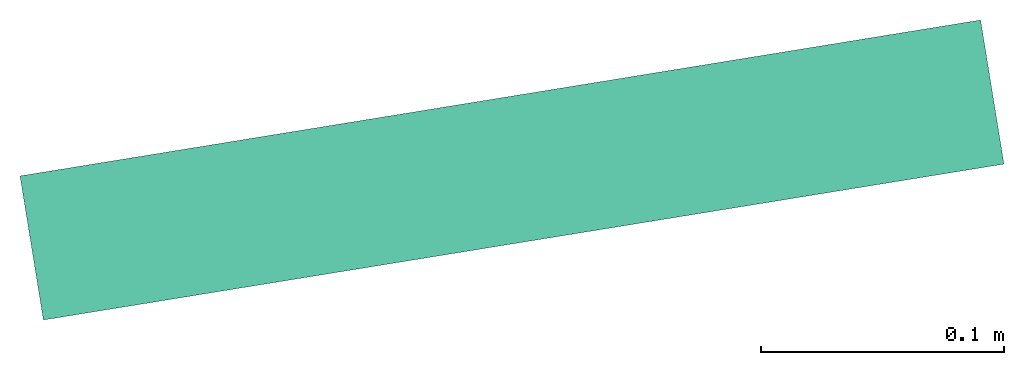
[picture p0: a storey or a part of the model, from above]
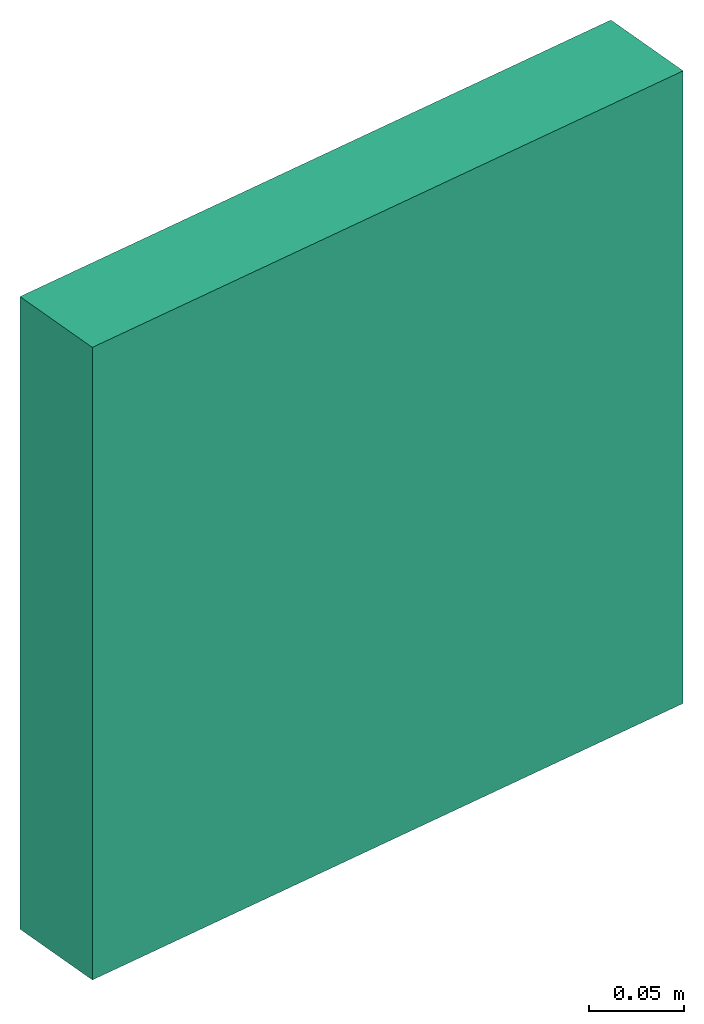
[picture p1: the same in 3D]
Properties of the parts of a building model (IFC2X3), part 1 of 4

# File
Description: ViewDefinition [CoordinationView_V2.0]
File name: BR003-350-201.1 (EDITED).ifc (Edited by Naviate Simple BIM 2022 version 6)
Time: 2026-03-27T08:58:00+01:00
Written by: ODA SDAI 24.12
Made in: Autodesk Revit 25.4.41.14 (ENU) - IFC 25.4.0.27

# IfcProject, 80052
LongName: T3 - Flesland; Phase: Som Bygget

# IfcSite (8)
RefElevation: 0 mm
Name | RefLatitude | RefLongitude
4 x Default | 42, 24, 53, 508911 | -71, -15, -29, -58837
3 x Default | 59, 54, 49, 759826 | 10, 44, 19, 467315
Default | 60, 17, 20, 899658 | 5, 13, 37, 654037

# IfcBuilding (8)
Name
7 x 
TOO | LongName: TOO

# IfcBuildingStorey: Level:8mm Head (19)
Name | LongName | Elevation (mm)
3 x Nivå A | Nivå A | 42100
3 x Nivå B | Nivå B | 44700
5 x Nivå E | Nivå E | 55630
7 x Nivå F | Nivå F | 59000
Nivå C | Nivå C | 48160

# IfcBuildingStorey: Level:Kote (2)
In: TOO
Name | LongName | Elevation (mm)
Nivå F | Nivå F | 59000
Nivå G | Nivå G | 64000

# IfcBuildingStorey: Level:T3 Kote (2)
In: TOO
Name | LongName | Elevation (mm)
Nivå D | Nivå D | 51000
Nivå E | Nivå E | 55630

# IfcAnnotation, Model Lines:32988126
In: Nivå F
ePset_LocationTool - Splitting: ORIGINAL
ePset_Simplebim - Assembly Level: Leaf

# IfcBeam: 223_Bjelker-T3-Prefab DLB:DLB400*815-700*420 (2)
In: Nivå F
Type - PredefinedType: BEAM
Material: Betong Plasstøpt - B1
Pset_BeamCommon - Reference: 223_Bjelker-T3-Prefab DLB:DLB400*815-700*420
ePset_SimplebimBasicQuantities - Area, sides, net (Simplebim): 26.8105 m2; Length (Simplebim): 8550 mm; Height (Simplebim): 815 mm; Volume, net (Simplebim): 3.8646 m3; Width (Simplebim): 700 mm; Weight, as steel (Simplebim): 30337.1 kg
AVINOR - 08_Status: S4; 07_Fase: F30
ePset_Simplebim - Assembly Level: Leaf
ePset_LocationTool - Splitting: ORIGINAL
Name (223_Bjelker-T3-Prefab DLB:DLB400*815-700*420:...)
25848422
25848424

# IfcBeam: A223 - DLB Prefab. Betongbjelke:A223 - DLB Prefab. Betongbjelke - 815 x 700 x 400 mm (2)
In: Nivå F
Type - PredefinedType: BEAM
Material: Concrete - Cast-in-Place Concrete
AVINOR - 08_Status: S3; 07_Fase: F30
Pset_BeamCommon - Reference: A223 - DLB Prefab. Betongbjelke:A223 - DLB Prefab. Betongbjelke - 815 x 700 x 400 mm
ePset_SimplebimBasicQuantities - Weight, as steel (Simplebim): 23976.2 kg; Height (Simplebim): 815 mm; Area, sides, net (Simplebim): 21.3786 m2; Length (Simplebim): 6757.29 mm; Width (Simplebim): 700 mm; Volume, net (Simplebim): 3.0543 m3
ePset_LocationTool - Splitting: ORIGINAL
ePset_Simplebim - Assembly Level: Leaf
Name (A223 - DLB Prefab. Betongbjelke:A223 - DLB Prefab. Betongbjelke - 815 x 700 x 400 mm:...)
15730720
28248135

# IfcBeam: A223 - LB Prefab. Betongbjelke 815x550:A223 - LB Prefab. Betongbjelke - 815 mm x 550 mm (3)
In: Nivå F
Type - PredefinedType: BEAM
ePset_SimplebimBasicQuantities - Height (Simplebim): 815 mm; Width (Simplebim): 550 mm
Pset_BeamCommon - Reference: A223 - LB Prefab. Betongbjelke 815x550:A223 - LB Prefab. Betongbjelke - 815 mm x 550 mm
AVINOR - 08_Status: S3; 07_Fase: F30
ePset_Simplebim - Assembly Level: Leaf
Name (A223 - LB Prefab. Betongbjelke 815x550:A223 - LB Prefab. Betongbjelke - 815 mm x 550 mm:...) | Splitting | Weight, as steel (Simplebim) (kg) | Volume, net (Simplebim) (m3) | Area, sides, net (Simplebim) (m2) | Length (Simplebim) (mm)
18706045 | ORIGINAL | 26575.9 | 3.38547 | 24.5372 | 8703 | Material: Concrete - Cast-in-Place Concrete
18706039 | RESULT | 21742.1 | 2.76969 | 20.2157 | 7120
18706051 | RESULT | 23826.1 | 3.03517 | 22.0788 | 7803

# IfcBeam: Rectangular Hollow Sections_Parameter:RHS100x200x10 (6)
Type - PredefinedType: BEAM
AVINOR - 08_Status: S4; 07_Fase: F90
Pset_BeamCommon - Reference: Rectangular Hollow Sections_Parameter:RHS100x200x10
ePset_SimplebimBasicQuantities - Width (Simplebim): 100 mm; Height (Simplebim): 200 mm
ePset_Simplebim - Assembly Level: Leaf
Name (Rectangular Hollow Sections_Parameter:RHS100x200x10:...) | In | Material | Splitting | Length (Simplebim) (mm) | Volume, net (Simplebim) (m3) | Area, sides, net (Simplebim) (m2) | Weight, as steel (Simplebim) (kg)
27042935 | Nivå F | Metal - Steel 50-355 | ORIGINAL | 4763.41 | 0.0266751 | 5.34622 | 209.4
27042937 | Nivå F | Metal - Steel 50-355 | ORIGINAL | 1605.53 | 0.00899095 | 1.80939 | 70.579
27046365 | Nivå F | Metal - Steel 50-355 | ORIGINAL | 4763.41 | 0.0266751 | 5.34622 | 209.4
27046367 | Nivå F | Metal - Steel 50-355 | ORIGINAL | 1633.53 | 0.00914775 | 1.84075 | 71.8099
29842427 | Nivå G |  | RESULT | 1966 | 0.0100881 | 2.03399 | 79.1917
27042939 | Nivå G |  | RESULT | 2135 | 0.0110374 | 2.22384 | 86.6433

# IfcBuildingElementProxy: 1612510-0001:Junction box1 (10)
In: Nivå F
Type - Material: <Unnamed>
AVINOR - 08_Status: S4; 07_Fase: F90
ePset_SimplebimBasicQuantities - Area, largest surface, net (Simplebim): 0.0121 m2; Volume, net (Simplebim): 0.000515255 m3; Height (Simplebim): 110 mm; Length (Simplebim): 110 mm; Thickness (Simplebim): 46 mm
ePset_LocationTool - Splitting: ORIGINAL
Pset_BuildingElementProxyCommon - Reference: 1612510-0001:Junction box1
ePset_Simplebim - Assembly Level: Leaf
Name (1612510-0001:Junction box1:...)
13268464 | Group: 31
13273142
13273163 | Group: 20
13303722
13303824
13303911
13324208
13324228 | Group: 29
13341823 | Group: 28
14886891 | AVINOR - 05_ID-nummer: +BR003=360.PB114-FA002

# IfcBuildingElementProxy: 248 Sidefoldesjalusi:A248 Sidefoldesjalusi (3)
In: Nivå F
Type - Material: Glass
AVINOR - 08_Status: S4; 07_Fase: F90
ePset_LocationTool - Splitting: ORIGINAL
ePset_SimplebimBasicQuantities - Area, largest surface, net (Simplebim): 0.689 m2; Length (Simplebim): 369.963 mm; Volume, net (Simplebim): 0.0689 m3; Thickness (Simplebim): 260 mm; Height (Simplebim): 2650 mm
Pset_BuildingElementProxyCommon - Reference: 248 Sidefoldesjalusi:A248 Sidefoldesjalusi
ePset_Simplebim - Assembly Level: Leaf
Name (248 Sidefoldesjalusi:A248 Sidefoldesjalusi:...)
26929427
26940893
27625954

# IfcBuildingElementProxy: 258 - gulvboks EL-kvadrat 300 x300:A258 - gulvboks EL-kvadrat 300x300, 258 - gulvboks EL-kvadrat 300 x300:A258 - gulvboks EL-kvadrat 300x300:30005898
In: Nivå F
Type - Material: Default
Pset_BuildingElementProxyCommon - Reference: 258 - gulvboks EL-kvadrat 300 x300:A258 - gulvboks EL-kvadrat 300x300
ePset_SimplebimBasicQuantities - Area, largest surface, net (Simplebim): 0.0587578 m2; Height (Simplebim): 5 mm; Thickness (Simplebim): 300 mm; Length (Simplebim): 300 mm; Volume, net (Simplebim): 0.00045 m3
ePset_LocationTool - Splitting: ORIGINAL
AVINOR - 08_Status: S1; 07_Fase: F30
ePset_Simplebim - Assembly Level: Leaf

# IfcBuildingElementProxy: BRANNSPJELD - - SZ011T:BRANNSPJELD -C-EI60-125 - SZ011T (2)
Type - Material: <Unnamed>
ePset_SimplebimBasicQuantities - Volume, net (Simplebim): 0.00323555 m3; Area, largest surface, net (Simplebim): 0.103933 m2; Thickness (Simplebim): 125 mm; Height (Simplebim): 125 mm; Length (Simplebim): 265 mm
ePset_LocationTool - Splitting: ORIGINAL
Pset_BuildingElementProxyCommon - Reference: BRANNSPJELD - - SZ011T:BRANNSPJELD -C-EI60-125 - SZ011T
AVINOR - 08_Status: S4; 07_Fase: F90
ePset_Simplebim - Assembly Level: Leaf
Group: 360.PB114 A
Name (BRANNSPJELD - - SZ011T:BRANNSPJELD -C-EI60-125 - SZ011T:...) | In | 05_ID-nummer
14787282 | Nivå F | +BR003=360.PB114-SZ005
18961542 | Nivå E | +BR003=360.PB114-SZ021

# IfcBuildingElementProxy: BRANNSPJELD - - SZ011T:BRANNSPJELD -C-EI60-160 - SZ011T, BRANNSPJELD - - SZ011T:BRANNSPJELD -C-EI60-160 - SZ011T:21433908
In: Nivå F
Type - Material: <Unnamed>
ePset_LocationTool - Splitting: ORIGINAL
Pset_BuildingElementProxyCommon - Reference: BRANNSPJELD - - SZ011T:BRANNSPJELD -C-EI60-160 - SZ011T
ePset_SimplebimBasicQuantities - Volume, net (Simplebim): 0.00530113 m3; Area, largest surface, net (Simplebim): 0.133035 m2; Thickness (Simplebim): 160 mm; Height (Simplebim): 160 mm; Length (Simplebim): 265 mm
AVINOR - 08_Status: S4; 07_Fase: F90; 05_ID-nummer: +BR003=360.PB114-SZ028
ePset_Simplebim - Assembly Level: Leaf
Group: 360.PB114 T

# IfcBuildingElementProxy: BRANNSPJELD - - SZ011T:BRANNSPJELD -C-EI60-400 - SZ011T (2)
In: Nivå F
Type - Material: <Unnamed>
ePset_SimplebimBasicQuantities - Area, largest surface, net (Simplebim): 0.561004 m2; Volume, net (Simplebim): 0.0558869 m3; Thickness (Simplebim): 400 mm; Height (Simplebim): 400 mm; Length (Simplebim): 447 mm
Pset_BuildingElementProxyCommon - Reference: BRANNSPJELD - - SZ011T:BRANNSPJELD -C-EI60-400 - SZ011T
ePset_LocationTool - Splitting: ORIGINAL
AVINOR - 08_Status: S4; 07_Fase: F90
ePset_Simplebim - Assembly Level: Leaf
Name (BRANNSPJELD - - SZ011T:BRANNSPJELD -C-EI60-400 - SZ011T:...) | 05_ID-nummer | Group
21341083 | +BR003=360.PB114-SZ025 | 360.PB114 A
21408593 | +BR003=360.PB114-SZ026 | 360.PB114 T

# IfcBuildingElementProxy: BRANNSPJELD - - SZ011T:BRANNSPJELD -C-EI60-500 - SZ011T (5)
In: Nivå F
Type - Material: <Unnamed>
AVINOR - 08_Status: S4; 07_Fase: F90
Pset_BuildingElementProxyCommon - Reference: BRANNSPJELD - - SZ011T:BRANNSPJELD -C-EI60-500 - SZ011T
ePset_LocationTool - Splitting: ORIGINAL
ePset_SimplebimBasicQuantities - Area, largest surface, net (Simplebim): 0.701255 m2; Thickness (Simplebim): 447 mm; Height (Simplebim): 500 mm; Length (Simplebim): 500 mm; Volume, net (Simplebim): 0.0873233 m3
ePset_Simplebim - Assembly Level: Leaf
Name (BRANNSPJELD - - SZ011T:BRANNSPJELD -C-EI60-500 - SZ011T:...) | 05_ID-nummer | Group
13302451 | +BR003=360.PB114-SZ007 | 360.PB114 A
13302491 | +BR003=360.PB114-SZ015 | 360.PB114 T
13302806 | +BR003=360.PB114-SZ008 | 360.PB114 A
14775724 | +BR003=360.PB114-SZ001 | 360.PB114 A
14775863 | +BR003=360.PB114-SZ009 | 360.PB114 T

# IfcBuildingElementProxy: BRANNSPJELD - 1 - SZ06T:BRANNSPJELD -C-EI120-200 - SZ06T, BRANNSPJELD - 1 - SZ06T:BRANNSPJELD -C-EI120-200 - SZ06T:18961634
In: Nivå E
Type - Material: <Unnamed>
AVINOR - 08_Status: S4; 07_Fase: F90; 05_ID-nummer: +BR003=360.PB114-SZ022
ePset_LocationTool - Splitting: ORIGINAL
Pset_BuildingElementProxyCommon - Reference: BRANNSPJELD - 1 - SZ06T:BRANNSPJELD -C-EI120-200 - SZ06T
ePset_SimplebimBasicQuantities - Height (Simplebim): 196 mm; Thickness (Simplebim): 196 mm; Length (Simplebim): 363 mm; Volume, net (Simplebim): 0.0108969 m3; Area, largest surface, net (Simplebim): 0.223234 m2
ePset_Simplebim - Assembly Level: Leaf
Group: 360.PB114 A

# IfcBuildingElementProxy: Bryter 1-polet m_boks:2006015 (5)
In: Nivå F
Type - Material: Material1
AVINOR - 08_Status: S4; 07_Fase: F90; 05_ID-nummer: +BR003=439.OO001-XS001T
Pset_BuildingElementProxyCommon - Reference: Bryter 1-polet m_boks:2006015
ePset_LocationTool - Splitting: ORIGINAL
ePset_SimplebimBasicQuantities - Volume, net (Simplebim): 0.000041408 m3; Thickness (Simplebim): 12 mm; Length (Simplebim): 60 mm; Height (Simplebim): 60 mm; Area, largest surface, net (Simplebim): 0.0036 m2
ePset_Simplebim - Assembly Level: Leaf
Name (Bryter 1-polet m_boks:2006015:...)
13268543
13273152
13273153
13273158
13322008

# IfcBuildingElementProxy: Bryter 2-polet påvegg:2006015, Bryter 2-polet påvegg:2006015:13993074
In: Nivå F
Type - Material: Material1
ePset_LocationTool - Splitting: ORIGINAL
AVINOR - 08_Status: S4; 07_Fase: F90; 05_ID-nummer: +BR003=439.OO001-XS001T
ePset_SimplebimBasicQuantities - Volume, net (Simplebim): 0.000041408 m3; Thickness (Simplebim): 12 mm; Length (Simplebim): 60 mm; Height (Simplebim): 60 mm; Area, largest surface, net (Simplebim): 0.0036 m2
Pset_BuildingElementProxyCommon - Reference: Bryter 2-polet påvegg:2006015
ePset_Simplebim - Assembly Level: Leaf

# IfcBuildingElementProxy: Dobbel stikk i kanal 2P+J hor innfelt:RECESSED-SOCKET-2(HOR) (3)
In: Nivå F
Type - Material: <Unnamed>
ePset_SimplebimBasicQuantities - Area, largest surface, net (Simplebim): 0.0085 m2; Volume, net (Simplebim): 0.0000446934 m3; Thickness (Simplebim): 74.5128 mm; Height (Simplebim): 76.1056 mm; Length (Simplebim): 110.062 mm
Pset_BuildingElementProxyCommon - Reference: Dobbel stikk i kanal 2P+J hor innfelt:RECESSED-SOCKET-2(HOR)
ePset_LocationTool - Splitting: ORIGINAL
AVINOR - 08_Status: S4; 07_Fase: F90; 05_ID-nummer: +BR003=439.OO001-UE001T
ePset_Simplebim - Assembly Level: Leaf
Name (Dobbel stikk i kanal 2P+J hor innfelt:RECESSED-SOCKET-2(HOR):...) | Group
13268198 | =433.PF111-KW38
13268258 | =433.PF111-KW38
13321827 | 37

# IfcBuildingElementProxy: Dobbel stikk i tak m_boks 2P+J PH:Earthed reces socket c2 (6)
In: Nivå F
Type - Material: <Unnamed>
ePset_LocationTool - Splitting: ORIGINAL
ePset_SimplebimBasicQuantities - Area, largest surface, net (Simplebim): 0.010086 m2; Height (Simplebim): 19 mm; Thickness (Simplebim): 82 mm; Length (Simplebim): 123 mm; Volume, net (Simplebim): 0.000118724 m3
Pset_BuildingElementProxyCommon - Reference: Dobbel stikk i tak m_boks 2P+J PH:Earthed reces socket c2
AVINOR - 08_Status: S4; 07_Fase: F90; 05_ID-nummer: +BR003=439.OO001-UE001T
ePset_Simplebim - Assembly Level: Leaf
Name (Dobbel stikk i tak m_boks 2P+J PH:Earthed reces socket c2:...)
13296715
13296716 | Group: 2
13296727
13296728 | Group: 23
13296735
13296736 | Group: 25

# IfcBuildingElementProxy: Dobbel stikk på vegg 2P+J hor PH:EARTHED-SOCKET-2(HOR) (22)
In: Nivå F
Type - Material: <Unnamed>
ePset_SimplebimBasicQuantities - Thickness (Simplebim): 45.1 mm; Length (Simplebim): 98.2 mm; Area, largest surface, net (Simplebim): 0.006174 m2; Height (Simplebim): 63.2 mm; Volume, net (Simplebim): 0.0000063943 m3
Pset_BuildingElementProxyCommon - Reference: Dobbel stikk på vegg 2P+J hor PH:EARTHED-SOCKET-2(HOR)
ePset_LocationTool - Splitting: ORIGINAL
AVINOR - 08_Status: S4; 07_Fase: F90; 05_ID-nummer: +BR003=439.OO001-UE001T
ePset_Simplebim - Assembly Level: Leaf
Name (Dobbel stikk på vegg 2P+J hor PH:EARTHED-SOCKET-2(HOR):...) | Group
13264661 | 1
13264669 | 3
13264673
13264676 | 4
13268019 | 18
13268034 | 13
13268035 | =433.PF111-KW42
13268036 | 13
13268037 | =433.PF111-KW42
13268038 | 13
13268039 | =433.PF111-KW42
13268040 | 13
13268041 | =433.PF111-KW42
13268047 | 30
13268048 | 30
13268049 | 30
13268050 | 30
13268665 | 17
13268686 | 17
13268706 | 17
13268745 | 14
18297994 | 39

# IfcBuildingElementProxy: Dobbel stikk på vegg 2P+J vert PH:EARTHED-SOCKET-2(VER) (3)
In: Nivå F
Type - Material: <Unnamed>
Pset_BuildingElementProxyCommon - Reference: Dobbel stikk på vegg 2P+J vert PH:EARTHED-SOCKET-2(VER)
ePset_LocationTool - Splitting: ORIGINAL
ePset_SimplebimBasicQuantities - Thickness (Simplebim): 45.1 mm; Height (Simplebim): 98.2 mm; Area, largest surface, net (Simplebim): 0.006174 m2; Length (Simplebim): 63.2 mm; Volume, net (Simplebim): 0.00000606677 m3
AVINOR - 08_Status: S4; 07_Fase: F90; 05_ID-nummer: +BR003=439.OO001-UE001T
ePset_Simplebim - Assembly Level: Leaf
Name (Dobbel stikk på vegg 2P+J vert PH:EARTHED-SOCKET-2(VER):...) | Group
4317817 | =433.PF111-KW6
4317895 | =433.PF111-KW6
16224344 | =433.PF111-KW49

# IfcBuildingElementProxy: Dobbel stikk vegg innf 1½ boks 2P+J vert PH:RECESSED-EARTHED-SOCKET-2(VER) (6)
In: Nivå F
Type - Material: Material3, Material2, Material1
ePset_SimplebimBasicQuantities - Thickness (Simplebim): 25.7805 mm; Volume, net (Simplebim): 0.000114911 m3; Length (Simplebim): 139.716 mm; Height (Simplebim): 144.742 mm; Area, largest surface, net (Simplebim): 0.00984 m2
Pset_BuildingElementProxyCommon - Reference: Dobbel stikk vegg innf 1½ boks 2P+J vert PH:RECESSED-EARTHED-SOCKET-2(VER)
AVINOR - 08_Status: S4; 07_Fase: F90; 05_ID-nummer: +BR003=439.OO001-UE001T
ePset_LocationTool - Splitting: ORIGINAL
ePset_Simplebim - Assembly Level: Leaf
Name (Dobbel stikk vegg innf 1½ boks 2P+J vert PH:RECESSED-EARTHED-SOCKET-2(VER):...) | Group
4300604 | =433.PF111-KW10
10222701 | =433.PF111-KW10
13264690 | =433.PF111-KW41
13264691
13303512 | 12
18211983 | =433.PF111-KW50

# IfcBuildingElementProxy: Dobbel stikk vegg innf 2P+J hor PH:RECESSED-SOCKET-2(HOR) (3)
In: Nivå F
Type - Material: <Unnamed>
ePset_LocationTool - Splitting: ORIGINAL
ePset_SimplebimBasicQuantities - Area, largest surface, net (Simplebim): 0.0085 m2; Volume, net (Simplebim): 0.0000446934 m3; Thickness (Simplebim): 74.5128 mm; Height (Simplebim): 76.1056 mm; Length (Simplebim): 110.062 mm
Pset_BuildingElementProxyCommon - Reference: Dobbel stikk vegg innf 2P+J hor PH:RECESSED-SOCKET-2(HOR)
AVINOR - 08_Status: S4; 07_Fase: F90; 05_ID-nummer: +BR003=439.OO001-UE001T
ePset_Simplebim - Assembly Level: Leaf
Name (Dobbel stikk vegg innf 2P+J hor PH:RECESSED-SOCKET-2(HOR):...)
13268002
13268003
14002127

# IfcBuildingElementProxy: Dobbelstikk vertikal:Dobbelstikk vertikal, Dobbelstikk vertikal:Dobbelstikk vertikal:30331455
In: Nivå F
Type - Material: Material3, Material1, Material2
ePset_SimplebimBasicQuantities - Volume, net (Simplebim): 0.000114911 m3; Length (Simplebim): 139.716 mm; Thickness (Simplebim): 25.7817 mm; Height (Simplebim): 144.742 mm; Area, largest surface, net (Simplebim): 0.00984 m2
Pset_BuildingElementProxyCommon - Reference: Dobbelstikk vertikal:Dobbelstikk vertikal
ePset_LocationTool - Splitting: ORIGINAL
ePset_Simplebim - Assembly Level: Leaf

# IfcBuildingElementProxy: El-ford-Skap:El-ford-Skap_001 (2)
In: Nivå F
Type - Material: <Unnamed>
ePset_LocationTool - Splitting: ORIGINAL
ePset_SimplebimBasicQuantities - Height (Simplebim): 2000 mm
AVINOR - 08_Status: S4; 07_Fase: F90
Pset_BuildingElementProxyCommon - Reference: El-ford-Skap:El-ford-Skap_001
ePset_Simplebim - Assembly Level: Leaf
Name (El-ford-Skap:...) | Volume, net (Simplebim) (m3) | Area, largest surface, net (Simplebim) (m2) | Thickness (Simplebim) (mm) | Length (Simplebim) (mm) | 05_ID-nummer | Group
=433.PF111:1945846 | 1.6 | 4 | 400 | 2000 | +BR003=433.PF111 | =433.PF111-KW10; =433.PF111-KW1; =433.PF111-KW6; =433.PF111-KW27; =433.PF111-KW41; =433.PF111-KW42; =433.PF111-KW38; =433.PF111-KW49; =433.PF111-KW50
=435.PF111:13223778 | 0.36 | 1.2 | 300 | 600 | +BR003=435.PF111 | 1; 3; 4; 18; 13; 30; 31; 17; 15; 14; 20; 2; 23; 25; 7; 8; 12; 37; 29; 39

# IfcBuildingElementProxy: El-ford-stativ:El-ford-stativ_001 (2)
In: Nivå F
Type - Material: <Unnamed>
ePset_LocationTool - Splitting: ORIGINAL
AVINOR - 08_Status: S4; 07_Fase: F90
Pset_BuildingElementProxyCommon - Reference: El-ford-stativ:El-ford-stativ_001
ePset_SimplebimBasicQuantities - Length (Simplebim): 600 mm; Thickness (Simplebim): 300 mm
ePset_Simplebim - Assembly Level: Leaf
Name (El-ford-stativ:El-ford-stativ_001:...) | Volume, net (Simplebim) (m3) | Area, largest surface, net (Simplebim) (m2) | Height (Simplebim) (mm)
1945912 | 0.36 | 1.2 | 2000
1946078 | 0.108 | 0.36 | 600

# IfcBuildingElementProxy: FANCOIL--LC006T:FANCOIL--LC006T, FANCOIL--LC006T:FANCOIL--LC006T:20416227
In: Nivå F
Type - Material: <Unnamed>
Pset_BuildingElementProxyCommon - Reference: FANCOIL--LC006T:FANCOIL--LC006T
ePset_SimplebimBasicQuantities - Volume, net (Simplebim): 0.126 m3; Height (Simplebim): 350 mm; Thickness (Simplebim): 600 mm; Length (Simplebim): 600 mm; Area, largest surface, net (Simplebim): 0.36 m2
ePset_LocationTool - Splitting: ORIGINAL
AVINOR - 05_ID-nummer: +BR003=370.PB102-LC013; 08_Status: S4; 07_Fase: F90
ePset_Simplebim - Assembly Level: Leaf
Group: 370.PB102 T

# IfcBuildingElementProxy: Gulvboks 300x300:CONNECTION BOX-EF-POWER-BALANC, Gulvboks 300x300:CONNECTION BOX-EF-POWER-BALANC:5003242
In: Nivå F
Type - Material: <Unnamed>
Pset_BuildingElementProxyCommon - Reference: Gulvboks 300x300:CONNECTION BOX-EF-POWER-BALANC
ePset_SimplebimBasicQuantities - Height (Simplebim): 70 mm; Thickness (Simplebim): 300 mm; Length (Simplebim): 300 mm; Area, largest surface, net (Simplebim): 0.09 m2; Volume, net (Simplebim): 0.0063 m3
ePset_LocationTool - Splitting: ORIGINAL
AVINOR - 08_Status: S4; 07_Fase: F90; 05_ID-nummer: +BR003=411.OO002-KK005T
ePset_Simplebim - Assembly Level: Leaf

# IfcBuildingElementProxy: Høyttaler innfelt 16cm:Bass speaker PC-2369EN /6W (7)
In: Nivå F
Type - Material: Material1, Material2
ePset_LocationTool - Splitting: ORIGINAL
ePset_SimplebimBasicQuantities - Area, largest surface, net (Simplebim): 0.0479856 m2; Length (Simplebim): 242.889 mm; Height (Simplebim): 170.098 mm; Volume, net (Simplebim): 0.00448694 m3; Thickness (Simplebim): 229.877 mm
AVINOR - 08_Status: S1; 07_Fase: F30
Pset_BuildingElementProxyCommon - Reference: Høyttaler innfelt 16cm:Bass speaker PC-2369EN /6W
ePset_Simplebim - Assembly Level: Leaf
Name (Høyttaler innfelt 16cm:Bass speaker PC-2369EN /6W:...)
7143913
7143918
7143919
7143920
7143921
7143936
9532946

# IfcBuildingElementProxy: INNREGULERINGSPJELD - - SR001T:INNREGULERINGSPJELD - IRIS-012 - SR001T, INNREGULERINGSPJELD - - SR001T:INNREGULERINGSPJELD - IRIS-012 - SR001T:14814005
In: Nivå F
Type - Material: <Unnamed>
ePset_LocationTool - Splitting: ORIGINAL
AVINOR - 08_Status: S4; 07_Fase: F90; 05_ID-nummer: +BR003=360.PB114-SR001T
ePset_SimplebimBasicQuantities - Volume, net (Simplebim): 0.000561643 m3; Area, largest surface, net (Simplebim): 0.0180412 m2; Thickness (Simplebim): 46 mm; Height (Simplebim): 125 mm; Length (Simplebim): 125 mm
Pset_BuildingElementProxyCommon - Reference: INNREGULERINGSPJELD - - SR001T:INNREGULERINGSPJELD - IRIS-012 - SR001T
ePset_Simplebim - Assembly Level: Leaf
Group: 360.PB114 A

# IfcBuildingElementProxy: INNREGULERINGSPJELD - - SR001T:INNREGULERINGSPJELD - IRIS-050 - SR001T (2)
In: Nivå F
Type - Material: <Unnamed>
Pset_BuildingElementProxyCommon - Reference: INNREGULERINGSPJELD - - SR001T:INNREGULERINGSPJELD - IRIS-050 - SR001T
ePset_SimplebimBasicQuantities - Thickness (Simplebim): 66 mm; Volume, net (Simplebim): 0.0128934 m3; Area, largest surface, net (Simplebim): 0.195354 m2; Height (Simplebim): 500 mm; Length (Simplebim): 500 mm
AVINOR - 08_Status: S4; 07_Fase: F90; 05_ID-nummer: +BR003=360.PB114-SR001T
ePset_LocationTool - Splitting: ORIGINAL
ePset_Simplebim - Assembly Level: Leaf
Name (INNREGULERINGSPJELD - - SR001T:INNREGULERINGSPJELD - IRIS-050 - SR001T:...) | Group
14747202 | 360.PB114 A
14747242 | 360.PB114 T

# IfcBuildingElementProxy: KJØLEAGGREGAT--IL - Starcold Aggregat:KJØLEAGGREGATMC LC1A B 020 MTIL - Starcold AggregaT, KJØLEAGGREGAT--IL - Starcold Aggregat:KJØLEAGGREGATMC LC1A B 020 MTIL - Starcold AggregaT:22178376
In: Nivå F
Type - Material: <Unnamed>
ePset_LocationTool - Splitting: ORIGINAL
ePset_SimplebimBasicQuantities - Area, largest surface, net (Simplebim): 0.920419 m2; Height (Simplebim): 1040.02 mm; Volume, net (Simplebim): 0.699519 m3; Thickness (Simplebim): 760 mm; Length (Simplebim): 885 mm
AVINOR - 05_ID-nummer: Kjøleaggregat-kom.areal; 08_Status: S4; 07_Fase: F90
Pset_BuildingElementProxyCommon - Reference: KJØLEAGGREGAT--IL - Starcold Aggregat:KJØLEAGGREGATMC LC1A B 020 MTIL - Starcold AggregaT
ePset_Simplebim - Assembly Level: Leaf

# IfcBuildingElementProxy: KJØLEAGGREGAT--IL - Starcold Aggregat:KJØLEAGGREGATMC LC4 B 050 MTIL - Starcold AggregaT, KJØLEAGGREGAT--IL - Starcold Aggregat:KJØLEAGGREGATMC LC4 B 050 MTIL - Starcold AggregaT:22178189
In: Nivå F
Type - Material: <Unnamed>
AVINOR - 05_ID-nummer: Kjøleaggregat-kom.areal; 08_Status: S4; 07_Fase: F90
ePset_LocationTool - Splitting: ORIGINAL
Pset_BuildingElementProxyCommon - Reference: KJØLEAGGREGAT--IL - Starcold Aggregat:KJØLEAGGREGATMC LC4 B 050 MTIL - Starcold AggregaT
ePset_SimplebimBasicQuantities - Volume, net (Simplebim): 1.05916 m3; Area, largest surface, net (Simplebim): 1.39363 m2; Height (Simplebim): 1040.02 mm; Thickness (Simplebim): 760 mm; Length (Simplebim): 1340 mm
ePset_Simplebim - Assembly Level: Leaf

# IfcBuildingElementProxy: Koblingsboks skjult:CABLE CLIP 1 - WALL - 2, Koblingsboks skjult:CABLE CLIP 1 - WALL - 2:13273173
In: Nivå F
Type - Material: <Unnamed>
ePset_SimplebimBasicQuantities - Volume, net (Simplebim): 0.0000139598 m3; Length (Simplebim): 110.24 mm; Area, largest surface, net (Simplebim): 0.00952342 m2; Thickness (Simplebim): 55.7518 mm; Height (Simplebim): 100.984 mm
Pset_BuildingElementProxyCommon - Reference: Koblingsboks skjult:CABLE CLIP 1 - WALL - 2
AVINOR - 08_Status: S4; 07_Fase: F90; 05_ID-nummer: +BR003=439.OO001-UX001T
ePset_LocationTool - Splitting: ORIGINAL
ePset_Simplebim - Assembly Level: Leaf

# IfcBuildingElementProxy: LYDDEMPER - - QL004T:LYDDEMPER - 125-300 - QL004T, LYDDEMPER - - QL004T:LYDDEMPER - 125-300 - QL004T:14814244
In: Nivå A
Type - Material: <Unnamed>
ePset_LocationTool - Splitting: ORIGINAL
ePset_SimplebimBasicQuantities - Area, largest surface, net (Simplebim): 0.158418 m2; Volume, net (Simplebim): 0.00650987 m3; Thickness (Simplebim): 165 mm; Height (Simplebim): 165 mm; Length (Simplebim): 306 mm
Pset_BuildingElementProxyCommon - Reference: LYDDEMPER - - QL004T:LYDDEMPER - 125-300 - QL004T
AVINOR - 08_Status: S4; 07_Fase: F90; 05_ID-nummer: +BR003=360.PB114-QL004T
ePset_Simplebim - Assembly Level: Leaf
Group: 360.PB114 A

# IfcBuildingElementProxy: LYDDEMPER - - QL004T:LYDDEMPER - 160-300 - QL004T, LYDDEMPER - - QL004T:LYDDEMPER - 160-300 - QL004T:19855073
In: Nivå E
Type - Material: <Unnamed>
ePset_LocationTool - Splitting: ORIGINAL
Pset_BuildingElementProxyCommon - Reference: LYDDEMPER - - QL004T:LYDDEMPER - 160-300 - QL004T
ePset_SimplebimBasicQuantities - Volume, net (Simplebim): 0.00956454 m3; Thickness (Simplebim): 200 mm; Height (Simplebim): 200 mm; Length (Simplebim): 306 mm; Area, largest surface, net (Simplebim): 0.192022 m2
AVINOR - 08_Status: S4; 07_Fase: F90; 05_ID-nummer: +BR003=360.PB114-QL004T
ePset_Simplebim - Assembly Level: Leaf
Group: 360.PB114 A

# IfcBuildingElementProxy: LYDDEMPER - - QL005T:LYDDEMPER - 125-600 - QL005T (2)
In: Nivå F
Type - Material: <Unnamed>
AVINOR - 08_Status: S4; 07_Fase: F90; 05_ID-nummer: +BR003=360.PB114-QL005T
ePset_SimplebimBasicQuantities - Volume, net (Simplebim): 0.0133176 m3; Thickness (Simplebim): 165 mm; Height (Simplebim): 165 mm; Length (Simplebim): 626 mm; Area, largest surface, net (Simplebim): 0.324083 m2
ePset_LocationTool - Splitting: ORIGINAL
ePset_Simplebim - Assembly Level: Leaf
Pset_BuildingElementProxyCommon - Reference: LYDDEMPER - - QL005T:LYDDEMPER - 125-600 - QL005T
Name (LYDDEMPER - - QL005T:LYDDEMPER - 125-600 - QL005T:...) | Group
21373703 | 360.PB114 A
21412222 | 360.PB114 T

# IfcBuildingElementProxy: LYDDEMPER - - QL006T:LYDDEMPER - 500-900 - QL006T, LYDDEMPER - - QL006T:LYDDEMPER - 500-900 - QL006T:21412104
In: Nivå F
Type - Material: <Unnamed>
ePset_LocationTool - Splitting: ORIGINAL
AVINOR - 08_Status: S4; 07_Fase: F90; 05_ID-nummer: +BR003=360.PB114-QL006T
Pset_BuildingElementProxyCommon - Reference: LYDDEMPER - - QL006T:LYDDEMPER - 500-900 - QL006T
ePset_Simplebim - Assembly Level: Leaf
ePset_SimplebimBasicQuantities - Thickness (Simplebim): 540 mm; Height (Simplebim): 540 mm; Area, largest surface, net (Simplebim): 1.5181 m2; Volume, net (Simplebim): 0.204164 m3; Length (Simplebim): 896 mm
Group: 360.PB114 T

# IfcBuildingElementProxy: LYDDEMPER - - QL007T:LYDDEMPER - 315-1200 - QL007T, LYDDEMPER - - QL007T:LYDDEMPER - 315-1200 - QL007T:21354941
In: Nivå F
Type - Material: <Unnamed>
AVINOR - 08_Status: S4; 07_Fase: F90; 05_ID-nummer: +BR003=360.PB114-QL007T
ePset_SimplebimBasicQuantities - Volume, net (Simplebim): 0.120734 m3; Area, largest surface, net (Simplebim): 1.36558 m2; Thickness (Simplebim): 355 mm; Height (Simplebim): 355 mm; Length (Simplebim): 1226 mm
ePset_LocationTool - Splitting: ORIGINAL
Pset_BuildingElementProxyCommon - Reference: LYDDEMPER - - QL007T:LYDDEMPER - 315-1200 - QL007T
ePset_Simplebim - Assembly Level: Leaf
Group: 360.PB114 A

# IfcBuildingElementProxy: Move-detector-2-0002:MOVE-DETECTOR-2 (3)
In: Nivå F
Type - Material: <Unnamed>
AVINOR - 08_Status: S4; 07_Fase: F90; 05_ID-nummer: +BR003=439.OO001-XS001T
Pset_BuildingElementProxyCommon - Reference: Move-detector-2-0002:MOVE-DETECTOR-2
ePset_SimplebimBasicQuantities - Thickness (Simplebim): 72.7557 mm; Volume, net (Simplebim): 0.0000355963 m3; Height (Simplebim): 57.7879 mm; Area, largest surface, net (Simplebim): 0.006724 m2; Length (Simplebim): 87.7235 mm
ePset_Simplebim - Assembly Level: Leaf
ePset_LocationTool - Splitting: ORIGINAL
Name (Move-detector-2-0002:MOVE-DETECTOR-2:...) | Group
6220780 | =433.PF111-KW27
6220791 | =433.PF111-KW1
6220806 | =433.PF111-KW1

# IfcBuildingElementProxy: Stikk 3 x 16 A-0001:Stikk 3 x 16 A (2)
In: Nivå F
Type - Material: <Unnamed>
ePset_LocationTool - Splitting: ORIGINAL
Pset_BuildingElementProxyCommon - Reference: Stikk 3 x 16 A-0001:Stikk 3 x 16 A
ePset_SimplebimBasicQuantities - Height (Simplebim): 134.272 mm; Thickness (Simplebim): 79.2 mm; Length (Simplebim): 106.679 mm; Volume, net (Simplebim): 0.001065 m3; Area, largest surface, net (Simplebim): 0.0084688 m2
AVINOR - 08_Status: S4; 07_Fase: F90; 05_ID-nummer: +BR003=439.OO001-UE001T
ePset_Simplebim - Assembly Level: Leaf
Name (Stikk 3 x 16 A-0001:Stikk 3 x 16 A:...)
13264700
13268725 | Group: 15

# IfcBuildingElementProxy: Styrepanel_FC:Styrepanel-FC, Styrepanel_FC:Styrepanel-FC:13981144
In: Nivå F
Type - Material: <Unnamed>
Pset_BuildingElementProxyCommon - Reference: Styrepanel_FC:Styrepanel-FC
ePset_LocationTool - Splitting: ORIGINAL
AVINOR - 08_Status: S4; 07_Fase: F90; 05_ID-nummer: +BR003=370.PB103-LC013
ePset_SimplebimBasicQuantities - Volume, net (Simplebim): 0.0000430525 m3; Height (Simplebim): 67.999 mm; Area, largest surface, net (Simplebim): 0.006724 m2; Length (Simplebim): 86.2572 mm; Thickness (Simplebim): 62.833 mm
ePset_Simplebim - Assembly Level: Leaf

# IfcBuildingElementProxy: TAPPEVANN KURS - 12 - - OR:TAPPEVANN KURS - 12 - 12 - OR001T, TAPPEVANN KURS - 12 - - OR:TAPPEVANN KURS - 12 - 12 - OR001T:18816543
In: Nivå F
Type - Material: <Unnamed>
Pset_BuildingElementProxyCommon - Reference: TAPPEVANN KURS - 12 - - OR:TAPPEVANN KURS - 12 - 12 - OR001T
AVINOR - 08_Status: S4; 07_Fase: F90; 05_ID-nummer: +BR003=310.TO100-OR041
ePset_SimplebimBasicQuantities - Volume, net (Simplebim): 0.04425 m3; Area, largest surface, net (Simplebim): 0.375 m2; Thickness (Simplebim): 118 mm; Height (Simplebim): 500 mm; Length (Simplebim): 750 mm
ePset_LocationTool - Splitting: ORIGINAL
ePset_Simplebim - Assembly Level: Leaf
Group: 310.TO100 78

# IfcBuildingElementProxy: TD rekkverk innfesting profiøl2:TD rekkverk innfesting profiøl, TD rekkverk innfesting profiøl2:TD rekkverk innfesting profiøl:30212482
In: Nivå F
Type - Material: <Unnamed>
AVINOR - 08_Status: S4; 07_Fase: F90
Pset_BuildingElementProxyCommon - Reference: TD rekkverk innfesting profiøl2:TD rekkverk innfesting profiøl
ePset_LocationTool - Splitting: ORIGINAL
ePset_SimplebimBasicQuantities - Thickness (Simplebim): 2045.01 mm; Height (Simplebim): 3797.46 mm; Volume, net (Simplebim): 0.0305185 m3; Area, largest surface, net (Simplebim): 1.20356 m2; Length (Simplebim): 7397.84 mm
ePset_Simplebim - Assembly Level: Leaf

# IfcBuildingElementProxy: Tempraturføler:FLOOR-HEATER-CONTROLLER-1 (3)
In: Nivå F
Type - Material: <Unnamed>
Pset_BuildingElementProxyCommon - Reference: Tempraturføler:FLOOR-HEATER-CONTROLLER-1
ePset_LocationTool - Splitting: ORIGINAL
ePset_SimplebimBasicQuantities - Volume, net (Simplebim): 0.0000430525 m3; Height (Simplebim): 67.999 mm; Area, largest surface, net (Simplebim): 0.006724 m2; Length (Simplebim): 86.2572 mm; Thickness (Simplebim): 62.833 mm
AVINOR - 08_Status: S4; 07_Fase: F90
ePset_Simplebim - Assembly Level: Leaf
Name (Tempraturføler:FLOOR-HEATER-CONTROLLER-1:...) | 05_ID-nummer
13298440 | +BR003=360.PB116-RT601
13334418 | +BR003=360.PB114-RT611
13977273 | +BR003=360.PB114-RT612

# IfcBuildingElementProxy: Trykk knapp bryter:2006015 (2)
In: Nivå F
Type - Material: Material1
AVINOR - 08_Status: S4; 07_Fase: F90; 05_ID-nummer: +BR003=439.OO001-XS001T
ePset_SimplebimBasicQuantities - Volume, net (Simplebim): 0.000041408 m3; Thickness (Simplebim): 12 mm; Length (Simplebim): 60 mm; Height (Simplebim): 60 mm; Area, largest surface, net (Simplebim): 0.0036 m2
ePset_LocationTool - Splitting: ORIGINAL
Pset_BuildingElementProxyCommon - Reference: Trykk knapp bryter:2006015
ePset_Simplebim - Assembly Level: Leaf
Name (Trykk knapp bryter:2006015:...)
13324011
13338986

# IfcBuildingElementProxy: Video-camera-3-0001:Video camera 3, Video-camera-3-0001:Video camera 3:10157307
In: Nivå F
Type - Material: <Unnamed>
ePset_LocationTool - Splitting: ORIGINAL
ePset_SimplebimBasicQuantities - Volume, net (Simplebim): 0.0000524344 m3; Area, largest surface, net (Simplebim): 0.0219284 m2; Thickness (Simplebim): 70 mm; Height (Simplebim): 115 mm; Length (Simplebim): 137.5 mm
AVINOR - 08_Status: S1; 07_Fase: F30
Pset_BuildingElementProxyCommon - Reference: Video-camera-3-0001:Video camera 3
ePset_Simplebim - Assembly Level: Leaf

# IfcBuildingElementProxy: Wieland stikk i tak m_boks 2P+dali+J PH:Earthed reces socket c2 (2)
In: Nivå F
Type - Material: <Unnamed>
Pset_BuildingElementProxyCommon - Reference: Wieland stikk i tak m_boks 2P+dali+J PH:Earthed reces socket c2
ePset_LocationTool - Splitting: ORIGINAL
ePset_SimplebimBasicQuantities - Area, largest surface, net (Simplebim): 0.010086 m2; Height (Simplebim): 19 mm; Thickness (Simplebim): 82 mm; Length (Simplebim): 123 mm; Volume, net (Simplebim): 0.000118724 m3
AVINOR - 08_Status: S4; 07_Fase: F90; 05_ID-nummer: +BR003=439.OO001-UE001T
ePset_Simplebim - Assembly Level: Leaf
Name (Wieland stikk i tak m_boks 2P+dali+J PH:Earthed reces socket c2:...) | Group
13296759 | 7
13296777 | 8

# IfcColumn: A222 - Rektangulær Betongsøyle:A222 - Rektangulær Betongsøyle - 650 x 650 mm (2)
In: Nivå D
Type - PredefinedType: COLUMN; Material: A200 - Betong
ePset_SimplebimBasicQuantities - Volume, net (Simplebim): 0.32955 m3; Weight, as steel (Simplebim): 2586.97 kg; Depth (Simplebim): 650 mm; Width (Simplebim): 650 mm; Height (Simplebim): 780 mm
Pset_ColumnCommon - Reference: A222 - Rektangulær Betongsøyle:A222 - Rektangulær Betongsøyle - 650 x 650 mm
ePset_LocationTool - Splitting: RESULT
AVINOR - 08_Status: S4; 07_Fase: F30
ePset_Simplebim - Assembly Level: Leaf
Name (A222 - Rektangulær Betongsøyle:A222 - Rektangulær Betongsøyle - 650 x 650 mm:...) | Area, sides, net (Simplebim) (m2)
1326796 | 2.028
12709641 | 2.02802

# IfcColumn: A222 - Sirkulær Stålsøyle:A222 - Sirkulær Stålsøyle - Ø 101,6 x 6, A222 - Sirkulær Stålsøyle:A222 - Sirkulær Stålsøyle - Ø 101,6 x 6:26264219
In: Nivå F
Type - PredefinedType: COLUMN; Material: <Unnamed>
AVINOR - 08_Status: S4; 07_Fase: F90
Pset_ColumnCommon - Reference: A222 - Sirkulær Stålsøyle:A222 - Sirkulær Stålsøyle - Ø 101,6 x 6
ePset_LocationTool - Splitting: ORIGINAL
ePset_SimplebimBasicQuantities - Weight, as steel (Simplebim): 50.6669 kg; Area, sides, net (Simplebim): 2.15968 m2; Volume, net (Simplebim): 0.00645438 m3; Depth (Simplebim): 101.6 mm; Width (Simplebim): 101.6 mm; Height (Simplebim): 3600 mm
ePset_Simplebim - Assembly Level: Leaf

# IfcColumn: A222 - Sirkulær Stålsøyle:A222 - Sirkulær Stålsøyle 1 - Ø 200 mm (4)
In: Nivå F
Type - PredefinedType: COLUMN; Material: <Unnamed>
Pset_ColumnCommon - Reference: A222 - Sirkulær Stålsøyle:A222 - Sirkulær Stålsøyle 1 - Ø 200 mm
ePset_SimplebimBasicQuantities - Volume, net (Simplebim): 0.0215577 m3; Depth (Simplebim): 200 mm; Width (Simplebim): 200 mm; Height (Simplebim): 3630 mm; Weight, as steel (Simplebim): 169.228 kg; Area, sides, net (Simplebim): 4.32801 m2
ePset_LocationTool - Splitting: ORIGINAL
AVINOR - 07_Fase: F30
ePset_Simplebim - Assembly Level: Leaf
Name (A222 - Sirkulær Stålsøyle:A222 - Sirkulær Stålsøyle 1 - Ø 200 mm:...) | 08_Status
6231926 | S4
6292362 | S4
15355509 | S3
22638513 | S3

# IfcCovering: Compound Ceiling:A256 A01 Akustiske plater direkkemonert (3)
In: Nivå E
Type - PredefinedType: CEILING
AVINOR - 08_Status: S4; 07_Fase: F90
Pset_CoveringCommon - Reference: Compound Ceiling:A256 A01 Akustiske plater direkkemonert
ePset_SimplebimBasicQuantities - Height (Simplebim): 50 mm
ePset_Simplebim - Assembly Level: Leaf
Name (Compound Ceiling:A256 A01 Akustiske plater direkkemonert:...) | Splitting | Volume, net (Simplebim) (m3) | Area, largest surface, net (Simplebim) (m2) | Width (Simplebim) (mm) | Length (Simplebim) (mm)
24465687 | ORIGINAL | 0.972 | 19.44 | 3000 | 7200 | Material: A256 - Akustiskeplater 50 mm
24464451 | RESULT | 2.21277 | 38.1208 | 6624 | 7572
24464419 | RESULT | 2.7256 | 54.5121 | 7200 | 7572

# IfcCovering: Compound Ceiling:A256 G01 GIPS BRANN HIMLING (3)
In: Nivå G
Type - PredefinedType: CEILING
Material: A257 - Brannplate 150 mm
ePset_LocationTool - Splitting: ORIGINAL
Pset_CoveringCommon - Reference: Compound Ceiling:A256 G01 GIPS BRANN HIMLING
AVINOR - 08_Status: S4; 07_Fase: F90
ePset_Simplebim - Assembly Level: Leaf
Name (Compound Ceiling:A256 G01 GIPS BRANN HIMLING:...) | Height (Simplebim) (mm) | Volume, net (Simplebim) (m3) | Length (Simplebim) (mm) | Area, largest surface, net (Simplebim) (m2) | Width (Simplebim) (mm)
27513999 | 1489.55 | 0.274479 | 2269.21 | 1.82986 | 1258.05
27514007 | 150 | 0.1653 | 1655.85 | 1.10204 | 1093.7
27514015 | 1148.13 | 0.203152 | 1728.3 | 1.35435 | 1113.11

# IfcCovering: Compound Ceiling:A257 - Gipshimling (KA) (3)
In: Nivå F
Type - PredefinedType: CEILING
Material: _NSW Stålstender, uisolert 50 mm, A240 - Gipsplate 13 mm
AVINOR - 08_Status: S4; 07_Fase: F90
ePset_LocationTool - Splitting: ORIGINAL
Pset_CoveringCommon - Reference: Compound Ceiling:A257 - Gipshimling (KA)
ePset_SimplebimBasicQuantities - Height (Simplebim): 63 mm
ePset_Simplebim - Assembly Level: Leaf
Name (Compound Ceiling:A257 - Gipshimling (KA):...) | Width (Simplebim) (mm) | Length (Simplebim) (mm) | Volume, net (Simplebim) (m3) | Area, largest surface, net (Simplebim) (m2)
32811285 | 502 | 3218.01 | 0.101773 | 1.61544
32864442 | 801.996 | 2436.89 | 0.0425699 | 0.675769
32891987 | 777 | 2945 | 0.144161 | 2.28826

# IfcCovering: Compound Ceiling:A257 MF02 Ansatte Hygiene Himling 600 x 600, Compound Ceiling:A257 MF02 Ansatte Hygiene Himling 600 x 600:32802025
In: Nivå F
Type - PredefinedType: CEILING
Material: _NSW Standard 80 mm, _NSW Himlingsplate 600x600 mm 20 mm
Pset_CoveringCommon - Reference: Compound Ceiling:A257 MF02 Ansatte Hygiene Himling 600 x 600
AVINOR - 08_Status: S4; 07_Fase: F90
ePset_SimplebimBasicQuantities - Length (Simplebim): 3813.17 mm; Volume, net (Simplebim): 0.689599 m3; Area, largest surface, net (Simplebim): 6.89605 m2; Height (Simplebim): 100 mm; Width (Simplebim): 2532.5 mm
ePset_LocationTool - Splitting: ORIGINAL
ePset_Simplebim - Assembly Level: Leaf

# IfcCovering: Compound Ceiling:A257 X513A - 600x600 (KA) (3)
In: Nivå F
Type - PredefinedType: CEILING
Material: A257 - Mineralull - 600 x 600mm 50 mm
AVINOR - 08_Status: S4; 07_Fase: F90
ePset_SimplebimBasicQuantities - Height (Simplebim): 50 mm
Pset_CoveringCommon - Reference: Compound Ceiling:A257 X513A - 600x600 (KA)
ePset_LocationTool - Splitting: ORIGINAL
ePset_Simplebim - Assembly Level: Leaf
Name (Compound Ceiling:A257 X513A - 600x600 (KA):...) | Area, largest surface, net (Simplebim) (m2) | Width (Simplebim) (mm) | Length (Simplebim) (mm) | Volume, net (Simplebim) (m3)
26466281 | 10.2241 | 2661 | 4335 | 0.511207
32802382 | 7.69772 | 2182.5 | 4043.01 | 0.384887
32858950 | 61.9636 | 8787.05 | 16015.6 | 3.09817

# IfcCovering: Duct Insulation:EI 120-60 (24)
Type - PredefinedType: INSULATION
Pset_CoveringCommon - Reference: Duct Insulation:EI 120-60
AVINOR - 08_Status: S4; 07_Fase: F90; 05_ID-nummer: +BR003=360.TO001-BI003T
ePset_Simplebim - Assembly Level: Leaf
Name (Duct Insulation:EI 120-60:...) | In | Splitting | Area, largest surface, net (Simplebim) (m2) | Height (Simplebim) (mm) | Width (Simplebim) (mm) | Length (Simplebim) (mm) | Volume, net (Simplebim) (m3)
13302590 | Nivå F | ORIGINAL | 0.592115 | 560 | 337.106 | 560 | 0.082497
13302592 | Nivå F | ORIGINAL | 0.838713 | 560 | 477.5 | 560 | 0.116854
13307113 | Nivå E | ORIGINAL | 2.50197 | 690 | 690 | 1155.65 | 0.429938
14001325 | Nivå E | ORIGINAL | 0.878004 | 30.8 | 1060 | 1060 | 0.0270424
14508694 | Nivå E | ORIGINAL | 0.8056 | 70 | 760 | 1060 | 0.056392
14508698 | Nivå E | ORIGINAL | 0.9116 | 100 | 860 | 1060 | 0.08586
14508733 | Nivå F | ORIGINAL | 0.446948 | 560 | 254.458 | 560 | 0.0622714
14508823 | Nivå F | ORIGINAL | 0.315662 | 560 | 179.714 | 560 | 0.04398
14508933 | Nivå F | ORIGINAL | 0.372028 | 20 | 690 | 690 | 0.00744065
14508988 | Nivå F | ORIGINAL | 7.70717 | 690 | 690 | 3560 | 1.32444
14746732 | Nivå F | ORIGINAL | 0.463623 | 460 | 321.491 | 460 | 0.0529814
14746733 | Nivå F | ORIGINAL | 2.10727 | 560 | 560 | 1199.72 | 0.293597
14746734 | Nivå F | ORIGINAL | 0.446948 | 560 | 254.458 | 560 | 0.0622714
14746735 | Nivå F | ORIGINAL | 0.164799 | 460 | 102.734 | 460 | 0.0169305
14747217 | Nivå F | ORIGINAL | 0.244721 | 560 | 70 | 560 | 0.0171305
14747254 | Nivå F | ORIGINAL | 1.08467 | 560 | 560 | 617.529 | 0.151123
14747255 | Nivå F | ORIGINAL | 0.244721 | 560 | 70 | 560 | 0.0171305
14775776 | Nivå F | ORIGINAL | 0.446194 | 560 | 254.029 | 560 | 0.0621664
14775896 | Nivå F | ORIGINAL | 0.257322 | 560 | 146.5 | 560 | 0.0358517
18182407 | Nivå F | ORIGINAL | 7.74385 | 690 | 690 | 3576.85 | 1.33071
18182411 | Nivå F | ORIGINAL | 0.372047 | 20 | 690 | 690 | 0.00744065
19881608 | Nivå E | ORIGINAL | 0.8056 | 100 | 760 | 1060 | 0.0717933
14001284 | Nivå E | RESULT | 0.878004 | 390 | 1060 | 1060 | 0.34242
14776177 | Nivå E | RESULT | 0.372028 | 690 | 690 | 980 | 0.364592

# IfcCovering: Duct Insulation:EI 60-30 (26)
In: Nivå F
Type - PredefinedType: INSULATION
Pset_CoveringCommon - Reference: Duct Insulation:EI 60-30
ePset_LocationTool - Splitting: ORIGINAL
AVINOR - 08_Status: S4; 07_Fase: F90; 05_ID-nummer: +BR003=360.TO001-BI002T
ePset_Simplebim - Assembly Level: Leaf
Name (Duct Insulation:EI 60-30:...) | Area, largest surface, net (Simplebim) (m2) | Length (Simplebim) (mm) | Volume, net (Simplebim) (m3) | Height (Simplebim) (mm) | Width (Simplebim) (mm)
13302593 | 6.53265 | 3721.25 | 0.909284 | 560 | 560
14746964 | 4.9065 | 2794.75 | 0.683235 | 560 | 560
21872183 | 0.562069 | 560 | 0.0783108 | 560 | 320
21872184 | 0.244721 | 560 | 0.00489443 | 560 | 20
21872185 | 2.07176 | 1179.5 | 0.288649 | 560 | 560
21872186 | 0.378628 | 580.612 | 0.0506447 | 560 | 329.642
21872187 | 0.932258 | 731.84 | 0.129888 | 560 | 717.696
21872188 | 0.378628 | 580.612 | 0.0506447 | 560 | 329.642
21872189 | 3.57958 | 1655 | 0.614112 | 690 | 690
21872190 | 0.109522 | 375 | 0.0035047 | 375 | 32
21872191 | 0.257609 | 375 | 0.023999 | 375 | 219.125
21872192 | 0.524905 | 502.5 | 0.0494316 | 375 | 502.5
21872193 | 0.109522 | 375 | 0.0068749 | 375 | 75
21872194 | 0.109522 | 375 | 0.0068749 | 375 | 75
21872196 | 1.01795 | 1047.9 | 0.0784648 | 310 | 310
21872197 | 3.22285 | 1836.09 | 0.448685 | 560 | 560
21872198 | 0.109522 | 375 | 0.0080299 | 375 | 73.3177
21872199 | 0.372033 | 690 | 0.0229842 | 690 | 75
21872200 | 0.14119 | 375 | 0.0131864 | 120 | 375
21872201 | 0.524905 | 502.5 | 0.0494316 | 502.5 | 375
21872202 | 1.0467 | 1077.5 | 0.0806578 | 310 | 310
21872207 | 1.99994 | 1701.87 | 0.186416 | 375 | 375
21872209 | 0.313735 | 375 | 0.0292277 | 375 | 266.866
21872210 | 0.400392 | 690 | 0.0171021 | 690 | 75
21872222 | 0.905926 | 628.198 | 0.103526 | 460 | 460
21872223 | 0.164799 | 460 | 0.0169351 | 460 | 102.762

# IfcCovering: Duct Insulation:MuT030 (11)
In: Nivå F
Type - PredefinedType: INSULATION
Pset_CoveringCommon - Reference: Duct Insulation:MuT030
AVINOR - 08_Status: S4; 07_Fase: F90; 05_ID-nummer: +BR003=360.TO001-BI001T
ePset_LocationTool - Splitting: ORIGINAL
ePset_Simplebim - Assembly Level: Leaf
Name (Duct Insulation:MuT030:...) | Volume, net (Simplebim) (m3) | Area, largest surface, net (Simplebim) (m2) | Height (Simplebim) (mm) | Width (Simplebim) (mm) | Length (Simplebim) (mm)
13302503 | 0.259405 | 1.86186 | 560 | 560 | 1060
21393104 | 0.585964 | 3.41567 | 690 | 690 | 1579.24
21393107 | 0.0229842 | 0.372033 | 690 | 75 | 690
21438425 | 0.0195844 | 0.372033 | 690 | 75 | 690
21438426 | 0.083496 | 0.730646 | 460 | 460 | 506.654
21438427 | 0.00661336 | 0.164799 | 454.712 | 157.819 | 460
21438428 | 0.0163405 | 0.158483 | 460 | 163.056 | 465.793
21438429 | 0.0163405 | 0.158483 | 460 | 163.056 | 465.793
21438430 | 1.38069 | 12.0984 | 460 | 460 | 8396.14
21438448 | 0.0974432 | 0.883822 | 460 | 630 | 630
21438449 | 0.278723 | 2.43849 | 460 | 460 | 1691.65

# IfcCurtainWall: Curtain Wall:Curtain Wall Standard (Bruk kun denne) (8)
In: Nivå F
AVINOR - 08_Status: S4; 07_Fase: F90
ePset_Simplebim - Assembly Level: Topmost
Pset_CurtainWallCommon - Reference: Curtain Wall:Curtain Wall Standard (Bruk kun denne)
Name (Curtain Wall:Curtain Wall Standard (Bruk kun denne):...) | Length (mm) | Volume, net (Simplebim) (m3) | Width (mm) | Height (mm)
13081258 | 8525.66 | 0.313713 | 250 | 3850
13081260 | 3941.6 | 0.134817 | 3166 | 1152.5
15231151 | 7723.83 | 0.208128 | 2116.5 | 3850
15503758 | 5765.06 | 0.295612 | 1782.37 | 3850
19705789 | 11317.8 | 0.369081 | 3262.92 | 3850
25312360 | 5539.39 | 0.24717 | 1507.93 | 2705
25313333 | 7310.09 | 0.0795548 | 1967 | 3849.96
28230179 | 7587.69 | 0.0317344 | 2051.05 | 3844.15

# IfcDistributionControlElement: Brannalarm Røykdetektor:SMOKE DETECTOR2 (10)
Type - Material: <Unnamed>
ePset_Simplebim - Assembly Level: Leaf
ePset_LocationTool - Splitting: ORIGINAL
AVINOR - 08_Status: S4; 07_Fase: F90
Name (Brannalarm Røykdetektor:SMOKE DETECTOR2:...) | In | 05_ID-nummer
4973888 | Nivå E | +BR003=542.PD209-RY1007
4973891 | Nivå E | +BR003=542.PD209-RY1012
4973894 | Nivå E | +BR003=542.PD209-RY1013
4990544 | Nivå E | +BR003=542.PD209-RY1015
4990579 | Nivå E | +BR003=542.PD209-RY1014
5070041 | Nivå F | +BR003=542.SF210-RY3006
5070212 | Nivå F | +BR003=542.SF210-RY3010
13326346 | Nivå F
13326348 | Nivå F | +BR003=542.SF210-RY3003
13326350 | Nivå F

# IfcDistributionControlElement: Brannalarm adresseledd:I/O UNIT, Brannalarm adresseledd:I/O UNIT:5309031
In: Nivå F
Type - Material: <Unnamed>
AVINOR - 08_Status: S4; 07_Fase: F90; 05_ID-nummer: +BR003=542.SF210-XZ3013
ePset_Simplebim - Assembly Level: Leaf
ePset_LocationTool - Splitting: ORIGINAL

# IfcDistributionPort (793)
Description: Flow
ePset_Simplebim - Assembly Level: Leaf
Name | FlowDirection | Group
Port_1902943_0 | SOURCEANDSINK
Port_1902943_1 | SOURCEANDSINK
Port_1903541_0 | SOURCEANDSINK
Port_1903541_1 | SOURCEANDSINK
Port_1903542_0 | SOURCEANDSINK
Port_1903542_1 | SOURCEANDSINK
Port_1903543_0 | SOURCEANDSINK
Port_1903543_1 | SOURCEANDSINK
Port_1903544_0 | SOURCEANDSINK
Port_1903544_1 | SOURCEANDSINK
Port_1903545_0 | SOURCEANDSINK
Port_1903545_1 | SOURCEANDSINK
Port_1945846_1 | SOURCEANDSINK
Port_1945912_1 | SOURCEANDSINK
Port_1946078_1 | SOURCEANDSINK
Port_1988257_0 | SOURCEANDSINK
Port_8618461_3 | SOURCEANDSINK
Port_1988257_1 | SOURCEANDSINK
Port_1988449_0 | SOURCEANDSINK
Port_13223399_1 | SOURCEANDSINK
Port_1988449_1 | SOURCEANDSINK
Port_13316142_1 | SOURCEANDSINK
Port_1988907_0 | SOURCEANDSINK
Port_8618634_3 | SOURCEANDSINK
Port_1988907_1 | SOURCEANDSINK
Port_1989701_0 | SOURCEANDSINK
Port_8618412_2 | SOURCEANDSINK
Port_1989701_1 | SOURCEANDSINK
Port_1990549_0 | SOURCEANDSINK
Port_8618442_2 | SOURCEANDSINK
Port_1990549_1 | SOURCEANDSINK
Port_13318090_1 | SOURCEANDSINK
Port_2405185_0 | SOURCEANDSINK
Port_2405185_1 | SOURCEANDSINK
Port_2405336_0 | SOURCEANDSINK
Port_2405336_1 | SOURCEANDSINK
Port_2405544_0 | SOURCEANDSINK
Port_2405544_1 | SOURCEANDSINK
Port_4317412_1 | SOURCEANDSINK
Port_6220791_1 | SOURCEANDSINK
Port_4317626_1 | SOURCEANDSINK
Port_6220806_1 | SOURCEANDSINK
Port_4317817_1 | SOURCEANDSINK
Port_4317895_1 | SOURCEANDSINK
Port_5003242_1 | SOURCEANDSINK
Port_5003254_1 | SOURCEANDSINK
Port_5003262_1 | SOURCEANDSINK
Port_5003266_1 | SOURCEANDSINK
Port_5003278_1 | SOURCEANDSINK
Port_5003288_1 | SOURCEANDSINK
Port_5003290_1 | SOURCEANDSINK
Port_5003292_0 | SOURCEANDSINK
Port_5003296_0 | SOURCEANDSINK
Port_5070041_1 | SOURCEANDSINK
Port_5070212_1 | SOURCEANDSINK
Port_5073298_1 | SOURCEANDSINK
2 x Port_5073299_1 | SOURCEANDSINK
Port_6220780_1 | SOURCEANDSINK
Port_5309031_1 | SOURCEANDSINK
Port_5957535_0 | SOURCEANDSINK
Port_5957535_1 | SOURCEANDSINK
Port_5957543_1 | SOURCEANDSINK
Port_5957539_0 | SOURCEANDSINK
Port_5957543_2 | SOURCEANDSINK
Port_5957539_1 | SOURCEANDSINK
Port_5957554_1 | SOURCEANDSINK
Port_5957546_0 | SOURCEANDSINK
Port_5957554_2 | SOURCEANDSINK
Port_5957546_1 | SOURCEANDSINK
Port_5957750_0 | SOURCEANDSINK
Port_5957750_1 | SOURCEANDSINK
Port_5957775_1 | SOURCEANDSINK
Port_5957767_0 | SOURCEANDSINK
Port_5957775_2 | SOURCEANDSINK
Port_5957767_1 | SOURCEANDSINK
Port_5957814_1 | SOURCEANDSINK
Port_5957778_0 | SOURCEANDSINK
Port_5957814_2 | SOURCEANDSINK
Port_5957778_1 | SOURCEANDSINK
Port_5957897_0 | SOURCEANDSINK
Port_5957897_1 | SOURCEANDSINK
Port_5957940_1 | SOURCEANDSINK
Port_5957930_0 | SOURCEANDSINK
Port_5957940_2 | SOURCEANDSINK
Port_5957930_1 | SOURCEANDSINK
Port_5957949_1 | SOURCEANDSINK
Port_5957943_0 | SOURCEANDSINK
Port_5957949_2 | SOURCEANDSINK
Port_5957943_1 | SOURCEANDSINK
Port_8091606_0 | SOURCEANDSINK
Port_8091606_1 | SOURCEANDSINK
Port_8170513_0 | SOURCEANDSINK
Port_8170513_1 | SOURCEANDSINK
Port_8170536_0 | SOURCEANDSINK
Port_8170536_1 | SOURCEANDSINK
Port_8618412_1 | SOURCEANDSINK
Port_8618442_1 | SOURCEANDSINK
Port_13317038_0 | SOURCEANDSINK
Port_8618442_3 | SOURCEANDSINK
Port_13316551_1 | SOURCEANDSINK
Port_8618461_1 | SOURCEANDSINK
Port_8618635_0 | SOURCEANDSINK
Port_8618461_2 | SOURCEANDSINK
Port_8803187_0 | SOURCEANDSINK
Port_8618634_1 | SOURCEANDSINK
Port_13223400_0 | SOURCEANDSINK
Port_8618634_2 | SOURCEANDSINK
Port_8618635_1 | SOURCEANDSINK
Port_8666939_0 | SOURCEANDSINK
Port_8666939_1 | SOURCEANDSINK
Port_8666940_0 | SOURCEANDSINK
Port_8666940_1 | SOURCEANDSINK
Port_8803181_1 | SOURCEANDSINK
Port_8803188_1 | SOURCEANDSINK
Port_8803187_1 | SOURCEANDSINK
Port_8803188_2 | SOURCEANDSINK
Port_10222701_1 | SOURCEANDSINK
Port_11383836_1 | SOURCEANDSINK
Port_11383837_1 | SOURCEANDSINK
Port_11385658_1 | SOURCEANDSINK
Port_11385659_1 | SOURCEANDSINK
Port_13223280_0 | SOURCEANDSINK
Port_13267997_1 | SOURCEANDSINK
Port_13223280_1 | SOURCEANDSINK
Port_13223378_0 | SOURCEANDSINK
Port_13267999_2 | SOURCEANDSINK
Port_13223378_1 | SOURCEANDSINK
Port_13268001_2 | SOURCEANDSINK
Port_13223399_2 | SOURCEANDSINK
Port_13223400_1 | SOURCEANDSINK
Port_13223399_3 | SOURCEANDSINK
Port_13267996_0 | SOURCEANDSINK
Port_13223778_1 | SOURCEANDSINK
Port_13224324_0 | SOURCEANDSINK
Port_13224324_1 | SOURCEANDSINK
Port_13317116_1 | SOURCEANDSINK
Port_13264669_1 | SOURCEANDSINK
Port_13264673_1 | SOURCEANDSINK
Port_13264691_1 | SOURCEANDSINK
Port_13264700_1 | SOURCEANDSINK
Port_13267995_0 | SOURCEANDSINK
Port_13267997_2 | SOURCEANDSINK
Port_13267995_1 | SOURCEANDSINK
Port_13268001_1 | SOURCEANDSINK
Port_13267996_1 | SOURCEANDSINK
Port_13267999_1 | SOURCEANDSINK
Port_13267996_2 | SOURCEANDSINK
Port_13268119_1 | SOURCEANDSINK
Port_13268002_1 | SOURCEANDSINK
Port_13268003_1 | SOURCEANDSINK
Port_13268035_1 | SOURCEANDSINK
Port_13268037_1 | SOURCEANDSINK
Port_13268040_1 | SOURCEANDSINK
Port_13268041_1 | SOURCEANDSINK
Port_13268047_1 | SOURCEANDSINK
2 x Port_13268048_1 | SOURCEANDSINK
2 x Port_13268049_1 | SOURCEANDSINK
Port_13268050_1 | SOURCEANDSINK
Port_13268119_0 | SOURCEANDSINK
Port_13268120_2 | SOURCEANDSINK
Port_13268120_0 | SOURCEANDSINK
Port_13268120_1 | SOURCEANDSINK
Port_13268198_1 | SOURCEANDSINK
Port_13268258_1 | SOURCEANDSINK
Port_13268543_1 | SOURCEANDSINK
Port_13268665_1 | SOURCEANDSINK
2 x Port_13268686_1 | SOURCEANDSINK
Port_13268706_1 | SOURCEANDSINK
Port_13273142_1 | SOURCEANDSINK
Port_13273152_1 | SOURCEANDSINK
Port_13273153_1 | SOURCEANDSINK
Port_13273158_1 | SOURCEANDSINK
Port_13273173_1 | SOURCEANDSINK
Port_13296715_1 | SOURCEANDSINK
Port_13296727_1 | SOURCEANDSINK
Port_13296735_1 | SOURCEANDSINK
Port_13298440_1 | SOURCEANDSINK
Port_13302147_0 | SOURCEANDSINK
Port_13302147_1 | SOURCEANDSINK
Port_13302154_0 | SOURCEANDSINK
Port_13302154_1 | SOURCEANDSINK
Port_13302160_0 | SOURCEANDSINK
Port_13302160_1 | SOURCEANDSINK
Port_13303722_1 | SOURCEANDSINK
Port_13303824_1 | SOURCEANDSINK
Port_13303911_1 | SOURCEANDSINK
Port_13316070_0 | SOURCEANDSINK
Port_13317290_1 | SOURCEANDSINK
Port_13316070_1 | SOURCEANDSINK
Port_13316142_2 | SOURCEANDSINK
Port_13316551_0 | SOURCEANDSINK
Port_13317330_1 | SOURCEANDSINK
Port_13316600_0 | SOURCEANDSINK
Port_13317290_2 | SOURCEANDSINK
Port_13316600_1 | SOURCEANDSINK
Port_13317333_1 | SOURCEANDSINK
Port_13316601_0 | SOURCEANDSINK
Port_13317330_2 | SOURCEANDSINK
Port_13316601_1 | SOURCEANDSINK
Port_13317333_2 | SOURCEANDSINK
Port_13316832_0 | SOURCEANDSINK
Port_13317116_2 | SOURCEANDSINK
Port_13316832_1 | SOURCEANDSINK
Port_13317119_2 | SOURCEANDSINK
Port_13317038_1 | SOURCEANDSINK
Port_13317119_1 | SOURCEANDSINK
Port_13317825_0 | SOURCEANDSINK
Port_13317912_1 | SOURCEANDSINK
Port_13317825_1 | SOURCEANDSINK
Port_13317840_0 | SOURCEANDSINK
Port_13318069_2 | SOURCEANDSINK
Port_13317840_1 | SOURCEANDSINK
Port_13318093_1 | SOURCEANDSINK
Port_13317873_0 | SOURCEANDSINK
Port_13317912_2 | SOURCEANDSINK
Port_13317873_1 | SOURCEANDSINK
Port_13318069_1 | SOURCEANDSINK
Port_13318005_0 | SOURCEANDSINK
Port_13318090_2 | SOURCEANDSINK
Port_13318005_1 | SOURCEANDSINK
Port_13318093_2 | SOURCEANDSINK
Port_13322008_1 | SOURCEANDSINK
Port_13324011_1 | SOURCEANDSINK
Port_13324208_1 | SOURCEANDSINK
Port_13326346_1 | SOURCEANDSINK
Port_13326348_1 | SOURCEANDSINK
Port_13326350_1 | SOURCEANDSINK
Port_13334418_1 | SOURCEANDSINK
Port_13338986_1 | SOURCEANDSINK
Port_13339049_0 | SOURCEANDSINK
Port_13339049_1 | SOURCEANDSINK
Port_13339050_0 | SOURCEANDSINK
Port_13339050_1 | SOURCEANDSINK
Port_13339053_0 | SOURCEANDSINK
Port_13339053_1 | SOURCEANDSINK
Port_13339064_1 | SOURCEANDSINK
Port_13339065_1 | SOURCEANDSINK
Port_13977273_1 | SOURCEANDSINK
Port_13981144_1 | SOURCEANDSINK
Port_13993074_1 | SOURCEANDSINK
Port_14002127_1 | SOURCEANDSINK
Port_14886891_1 | SOURCEANDSINK
Port_15203444_1 | SOURCEANDSINK
Port_16489651_0 | SOURCEANDSINK
Port_16489651_1 | SOURCEANDSINK
InPort_2797467_0 | SINK | 360.PB114 T
OutPort_21393105_2 | SOURCE | 360.PB114 T
InPort_21393109_1 | SINK | 360.PB114 T
OutPort_2797467_1 | SOURCE | 360.PB114 T
InPort_21393115_1 | SINK | 360.PB114 T
OutPort_2797467_3 | SOURCE | 360.PB114 T
InPort_21434715_1 | SINK | 360.PB114 T
OutPort_2797467_4 | SOURCE | 360.PB114 T
Port_2801698_0 | SOURCEANDSINK | 360.PB114 T
Port_2801698_1 | SOURCEANDSINK | 360.PB114 T
Port_14508826_2 | SOURCEANDSINK | 360.PB114 T
InPort_14001323_1 | SINK | 360.PB116 T
InPort_18182408_2 | SINK | 360.PB114 A
OutPort_12068523_0 | SOURCE | 360.PB114 A
InPort_12068523_4 | SINK | 360.PB114 A
OutPort_14508731_1 | SOURCE | 360.PB114 A
InPort_12068523_5 | SINK | 360.PB114 A
OutPort_14508734_1 | SOURCE | 360.PB114 A
InPort_13302451_1 | SINK | 360.PB114 A
OutPort_21341208_0 | SOURCE | 360.PB114 A
InPort_13302469_1 | SINK | 360.PB114 A
OutPort_13302451_2 | SOURCE | 360.PB114 A
InPort_13302469_4 | SINK | 360.PB114 A
OutPort_14508760_1 | SOURCE | 360.PB114 A
InPort_21393102_0 | SINK | 360.PB114 T
OutPort_13302491_1 | SOURCE | 360.PB114 T
InPort_13302491_2 | SINK | 360.PB114 T
OutPort_13302501_1 | SOURCE | 360.PB114 T
InPort_13302501_0 | SINK | 360.PB114 T
OutPort_14775863_1 | SOURCE | 360.PB114 T
InPort_13302806_1 | SINK | 360.PB114 A
InPort_13302816_0 | SINK | 360.PB114 A
OutPort_13302806_2 | SOURCE | 360.PB114 A
InPort_14508734_2 | SINK | 360.PB114 A
OutPort_13302816_1 | SOURCE | 360.PB114 A
InPort_19881609_2 | SINK | 360.PB116 T
OutPort_14508688_0 | SOURCE | 360.PB116 T
InPort_14508688_1 | SINK | 360.PB116 T
OutPort_19881607_2 | SOURCE | 360.PB116 T
InPort_19881607_1 | SINK | 360.PB116 T
OutPort_14508693_0 | SOURCE | 360.PB116 T
InPort_14508693_1 | SINK | 360.PB116 T
OutPort_14508697_2 | SOURCE | 360.PB116 T
InPort_14508697_1 | SINK | 360.PB116 T
InPort_14508731_2 | SINK | 360.PB114 A
OutPort_14747214_0 | SOURCE | 360.PB114 A
InPort_14508760_2 | SINK | 360.PB114 A
OutPort_14508758_0 | SOURCE | 360.PB114 A
InPort_14508758_1 | SINK | 360.PB114 A
OutPort_14508763_1 | SOURCE | 360.PB114 A
InPort_14508763_2 | SINK | 360.PB114 A
OutPort_14814017_0 | SOURCE | 360.PB114 A
InPort_14787282_1 | SINK | 360.PB114 A
OutPort_14508765_0 | SOURCE | 360.PB114 A
InPort_14508765_1 | SINK | 360.PB114 A
OutPort_14508769_1 | SOURCE | 360.PB114 A
InPort_14508821_1 | SINK | 360.PB114 T
OutPort_14508980_3 | SOURCE | 360.PB114 T
InPort_14747252_0 | SINK | 360.PB114 T
OutPort_14508821_2 | SOURCE | 360.PB114 T
Port_14508826_1 | SOURCEANDSINK | 360.PB114 T
Port_14508980_2 | SOURCEANDSINK | 360.PB114 T
Port_14508930_1 | SOURCEANDSINK | 360.PB114 T
Port_14508930_2 | SOURCEANDSINK | 360.PB114 T
Port_14508980_0 | SOURCEANDSINK | 360.PB114 T
OutPort_14551285_1 | SOURCE | 360.PB116 A
InPort_14551285_2 | SINK | 360.PB116 A
OutPort_14551331_0 | SOURCE | 360.PB116 A
InPort_14551331_2 | SINK | 360.PB116 A
OutPort_14551374_1 | SOURCE | 360.PB116 A
InPort_14551331_3 | SINK | 360.PB116 A
OutPort_14551481_1 | SOURCE | 360.PB116 A
InPort_14551331_4 | SINK | 360.PB116 A
OutPort_14551509_1 | SOURCE | 360.PB116 A
InPort_14551374_2 | SINK | 360.PB116 A
InPort_14551509_2 | SINK | 360.PB116 A
InPort_14551481_2 | SINK | 360.PB116 A
InPort_14775724_1 | SINK | 360.PB114 A
OutPort_14746962_0 | SOURCE | 360.PB114 A
InPort_14747010_0 | SINK | 360.PB114 T
OutPort_14747242_1 | SOURCE | 360.PB114 T
InPort_14747202_1 | SINK | 360.PB114 A
OutPort_14775746_0 | SOURCE | 360.PB114 A
InPort_14747214_1 | SINK | 360.PB114 A
OutPort_14747202_2 | SOURCE | 360.PB114 A
InPort_14747242_2 | SINK | 360.PB114 T
OutPort_14747252_1 | SOURCE | 360.PB114 T
InPort_14775746_1 | SINK | 360.PB114 A
OutPort_14775724_2 | SOURCE | 360.PB114 A
InPort_14775863_2 | SINK | 360.PB114 T
OutPort_14775865_1 | SOURCE | 360.PB114 T
InPort_14814404_0 | SINK | 360.PB114 A
OutPort_14787282_2 | SOURCE | 360.PB114 A
InPort_14814005_1 | SINK | 360.PB114 A
OutPort_14814388_0 | SOURCE | 360.PB114 A
InPort_14814017_1 | SINK | 360.PB114 A
OutPort_14814005_2 | SOURCE | 360.PB114 A
InPort_14814244_1 | SINK | 360.PB114 A
OutPort_14814404_1 | SOURCE | 360.PB114 A
InPort_14814388_1 | SINK | 360.PB114 A
OutPort_14814244_2 | SOURCE | 360.PB114 A
InPort_14984020_1 | SINK | 360.PB116 T
InPort_18182405_1 | SINK | 360.PB114 A
OutPort_18182408_1 | SOURCE | 360.PB114 A
InPort_18929419_1 | SINK | 360.PB116 T
OutPort_19881609_1 | SOURCE | 360.PB116 T
InPort_18961029_1 | SINK | 360.PB114 A
OutPort_18958509_1 | SOURCE | 360.PB114 A
InPort_18968580_0 | SINK | 360.PB114 A
OutPort_18958537_1 | SOURCE | 360.PB114 A
InPort_18960790_0 | SINK | 360.PB114 A
OutPort_18968418_1 | SOURCE | 360.PB114 A
InPort_18960824_1 | SINK | 360.PB114 A
OutPort_18960790_1 | SOURCE | 360.PB114 A
InPort_18960800_0 | SINK | 360.PB114 A
OutPort_18960824_2 | SOURCE | 360.PB114 A
InPort_18960837_1 | SINK | 360.PB114 A
OutPort_18960800_1 | SOURCE | 360.PB114 A
InPort_18961107_0 | SINK | 360.PB114 A
OutPort_18960837_2 | SOURCE | 360.PB114 A
InPort_18961542_1 | SINK | 360.PB114 A
OutPort_18961029_0 | SOURCE | 360.PB114 A
InPort_18961123_2 | SINK | 360.PB114 A
OutPort_18961107_1 | SOURCE | 360.PB114 A
InPort_18961165_0 | SINK | 360.PB114 A
OutPort_18961123_1 | SOURCE | 360.PB114 A
InPort_18961185_1 | SINK | 360.PB114 A
OutPort_18961165_1 | SOURCE | 360.PB114 A
OutPort_18961185_2 | SOURCE | 360.PB114 A
InPort_18961567_1 | SINK | 360.PB114 A
OutPort_18961542_2 | SOURCE | 360.PB114 A
InPort_18969051_2 | SINK | 360.PB114 A
OutPort_18961567_0 | SOURCE | 360.PB114 A
InPort_18968418_2 | SINK | 360.PB114 A
OutPort_18961634_1 | SOURCE | 360.PB114 A
InPort_18961634_2 | SINK | 360.PB114 A
OutPort_19854624_1 | SOURCE | 360.PB114 A
InPort_18969027_3 | SINK | 360.PB114 A
OutPort_18968580_1 | SOURCE | 360.PB114 A
InPort_18969027_1 | SINK | 360.PB114 A
OutPort_18969051_1 | SOURCE | 360.PB114 A
InPort_19855075_0 | SINK | 360.PB114 A
OutPort_18969027_2 | SOURCE | 360.PB114 A
InPort_19854624_2 | SINK | 360.PB114 A
OutPort_19854931_0 | SOURCE | 360.PB114 A
InPort_19854945_0 | SINK | 360.PB114 A
OutPort_19855073_1 | SOURCE | 360.PB114 A
InPort_19855073_2 | SINK | 360.PB114 A
OutPort_19855075_1 | SOURCE | 360.PB114 A
InPort_21339646_0 | SINK | 360.PB114 A
OutPort_21596523_1 | SOURCE | 360.PB114 A
InPort_21620656_0 | SINK | 360.PB114 A
OutPort_21339646_1 | SOURCE | 360.PB114 A
InPort_21341093_0 | SINK | 360.PB114 A
OutPort_21341083_2 | SOURCE | 360.PB114 A
InPort_21374538_2 | SINK | 360.PB114 A
OutPort_21341093_1 | SOURCE | 360.PB114 A
InPort_21341208_1 | SINK | 360.PB114 A
OutPort_21341210_1 | SOURCE | 360.PB114 A
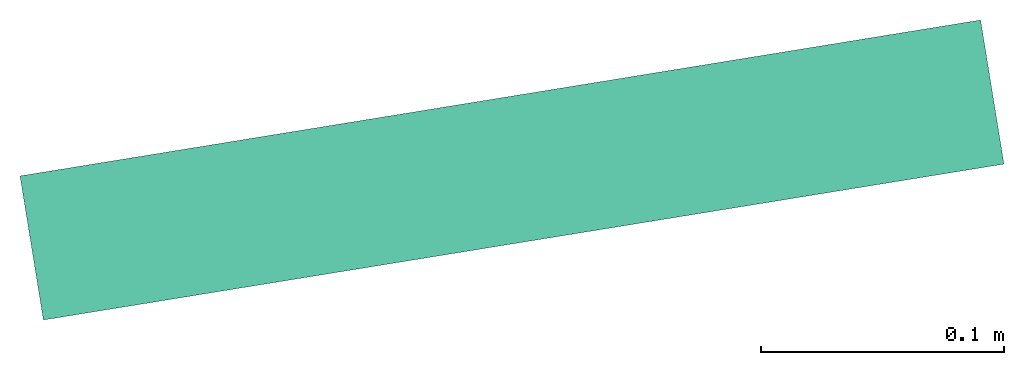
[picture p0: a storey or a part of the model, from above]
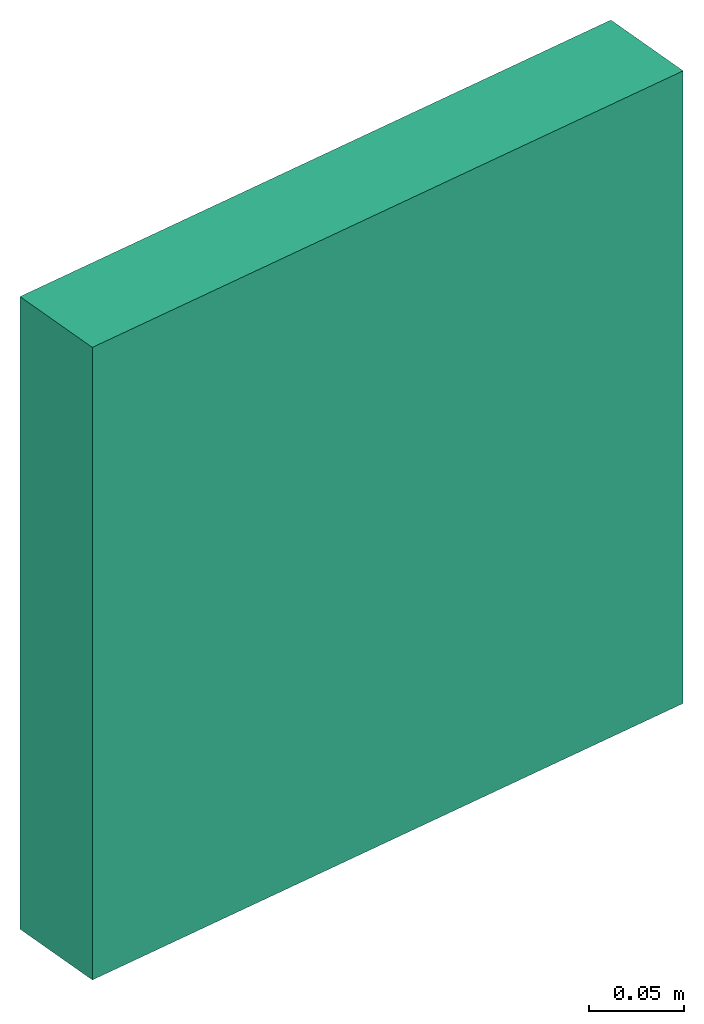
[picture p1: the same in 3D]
Properties of the parts of a building model (IFC2X3), part 2 of 4

# IfcDistributionPort (793)
Name | FlowDirection | Group
InPort_21341210_2 | SINK | 360.PB114 A
OutPort_21351860_0 | SOURCE | 360.PB114 A
InPort_21351860_1 | SINK | 360.PB114 A
OutPort_21351881_1 | SOURCE | 360.PB114 A
InPort_21351860_3 | SINK | 360.PB114 A
OutPort_21435227_1 | SOURCE | 360.PB114 A
InPort_21351881_2 | SINK | 360.PB114 A
OutPort_21351884_0 | SOURCE | 360.PB114 A
InPort_21351884_1 | SINK | 360.PB114 A
OutPort_21351896_2 | SOURCE | 360.PB114 A
InPort_21351896_1 | SINK | 360.PB114 A
OutPort_21374515_0 | SOURCE | 360.PB114 A
InPort_21374540_2 | SINK | 360.PB114 A
OutPort_21354114_0 | SOURCE | 360.PB114 A
InPort_21354114_1 | SINK | 360.PB114 A
OutPort_21374534_2 | SOURCE | 360.PB114 A
InPort_21354114_5 | SINK | 360.PB114 A
OutPort_21374536_1 | SOURCE | 360.PB114 A
InPort_21354114_6 | SINK | 360.PB114 A
OutPort_21374538_1 | SOURCE | 360.PB114 A
InPort_21374068_2 | SINK | 360.PB114 A
OutPort_21354120_0 | SOURCE | 360.PB114 A
InPort_21354120_1 | SINK | 360.PB114 A
OutPort_21354807_1 | SOURCE | 360.PB114 A
InPort_21356076_1 | SINK | 360.PB114 A
OutPort_21354368_0 | SOURCE | 360.PB114 A
InPort_21354368_1 | SINK | 360.PB114 A
OutPort_21620652_1 | SOURCE | 360.PB114 A
InPort_21354684_0 | SINK | 360.PB114 A
OutPort_21355283_2 | SOURCE | 360.PB114 A
InPort_21374536_2 | SINK | 360.PB114 A
OutPort_21354684_1 | SOURCE | 360.PB114 A
InPort_21354807_2 | SINK | 360.PB114 A
OutPort_21354799_0 | SOURCE | 360.PB114 A
InPort_21354799_1 | SINK | 360.PB114 A
OutPort_21354819_2 | SOURCE | 360.PB114 A
InPort_21354819_1 | SINK | 360.PB114 A
OutPort_21354818_1 | SOURCE | 360.PB114 A
InPort_21354961_1 | SINK | 360.PB114 A
OutPort_21354941_1 | SOURCE | 360.PB114 A
InPort_21354941_2 | SINK | 360.PB114 A
OutPort_21373915_1 | SOURCE | 360.PB114 A
InPort_21355283_1 | SINK | 360.PB114 A
OutPort_21356074_1 | SOURCE | 360.PB114 A
InPort_21356074_2 | SINK | 360.PB114 A
OutPort_21356095_0 | SOURCE | 360.PB114 A
InPort_21641322_0 | SINK | 360.PB114 A
OutPort_21356076_2 | SOURCE | 360.PB114 A
InPort_21374534_1 | SINK | 360.PB114 A
OutPort_21373506_0 | SOURCE | 360.PB114 A
InPort_21412093_2 | SINK | 360.PB114 A
OutPort_21373624_0 | SOURCE | 360.PB114 A
InPort_21373624_1 | SINK | 360.PB114 A
OutPort_21373645_1 | SOURCE | 360.PB114 A
InPort_21373645_2 | SINK | 360.PB114 A
OutPort_21373637_0 | SOURCE | 360.PB114 A
InPort_21373637_1 | SINK | 360.PB114 A
OutPort_21373667_1 | SOURCE | 360.PB114 A
InPort_21393195_2 | SINK | 360.PB114 A
OutPort_21373674_0 | SOURCE | 360.PB114 A
InPort_21373703_1 | SINK | 360.PB114 A
OutPort_21412093_1 | SOURCE | 360.PB114 A
InPort_21373705_1 | SINK | 360.PB114 A
OutPort_21373703_2 | SOURCE | 360.PB114 A
InPort_21373915_0 | SINK | 360.PB114 A
OutPort_21374068_1 | SOURCE | 360.PB114 A
InPort_21374515_1 | SINK | 360.PB114 A
OutPort_21374540_1 | SOURCE | 360.PB114 A
InPort_21374515_3 | SINK | 360.PB114 A
OutPort_21412086_1 | SOURCE | 360.PB114 A
InPort_21393105_1 | SINK | 360.PB114 T
OutPort_21393102_1 | SOURCE | 360.PB114 T
InPort_21393119_0 | SINK | 360.PB114 T
OutPort_21393109_2 | SOURCE | 360.PB114 T
InPort_21412070_0 | SINK | 360.PB114 T
OutPort_21393115_2 | SOURCE | 360.PB114 T
InPort_21393123_1 | SINK | 360.PB114 T
OutPort_21393119_1 | SOURCE | 360.PB114 T
InPort_21393121_0 | SINK | 360.PB114 T
OutPort_21393123_2 | SOURCE | 360.PB114 T
InPort_21393133_2 | SINK | 360.PB114 T
OutPort_21393121_1 | SOURCE | 360.PB114 T
InPort_21393131_1 | SINK | 360.PB114 T
OutPort_21408599_0 | SOURCE | 360.PB114 T
InPort_21408594_0 | SINK | 360.PB114 T
OutPort_21393131_2 | SOURCE | 360.PB114 T
InPort_21408599_1 | SINK | 360.PB114 T
OutPort_21393133_1 | SOURCE | 360.PB114 T
InPort_21393164_1 | SINK | 360.PB114 T
OutPort_21393211_1 | SOURCE | 360.PB114 T
InPort_21393181_0 | SINK | 360.PB114 T
OutPort_21412074_2 | SOURCE | 360.PB114 T
InPort_21412091_2 | SINK | 360.PB114 T
OutPort_21393181_1 | SOURCE | 360.PB114 T
InPort_21412086_2 | SINK | 360.PB114 A
OutPort_21393186_0 | SOURCE | 360.PB114 A
InPort_21393186_1 | SINK | 360.PB114 A
OutPort_21412088_2 | SOURCE | 360.PB114 A
InPort_21412088_1 | SINK | 360.PB114 A
OutPort_21393195_1 | SOURCE | 360.PB114 A
InPort_21393197_1 | SINK | 360.PB114 T
OutPort_21412091_1 | SOURCE | 360.PB114 T
InPort_21412084_0 | SINK | 360.PB114 T
OutPort_21393197_2 | SOURCE | 360.PB114 T
InPort_21393211_0 | SINK | 360.PB114 T
OutPort_21412202_1 | SOURCE | 360.PB114 T
InPort_21408593_2 | SINK | 360.PB114 T
OutPort_21408594_1 | SOURCE | 360.PB114 T
InPort_21412074_1 | SINK | 360.PB114 T
OutPort_21408599_3 | SOURCE | 360.PB114 T
InPort_21412098_1 | SINK | 360.PB114 T
OutPort_21412070_1 | SOURCE | 360.PB114 T
InPort_21412348_1 | SINK | 360.PB114 T
OutPort_21412098_2 | SOURCE | 360.PB114 T
InPort_21412350_2 | SINK | 360.PB114 T
OutPort_21412102_1 | SOURCE | 360.PB114 T
InPort_21413433_1 | SINK | 360.PB114 T
OutPort_21412104_1 | SOURCE | 360.PB114 T
InPort_21412104_2 | SINK | 360.PB114 T
OutPort_21412350_1 | SOURCE | 360.PB114 T
InPort_21412110_1 | SINK | 360.PB114 T
OutPort_21412114_0 | SOURCE | 360.PB114 T
InPort_21412112_0 | SINK | 360.PB114 T
OutPort_21415239_2 | SOURCE | 360.PB114 T
InPort_21412145_1 | SINK | 360.PB114 T
OutPort_21412112_1 | SOURCE | 360.PB114 T
InPort_21412114_1 | SINK | 360.PB114 T
OutPort_21449869_1 | SOURCE | 360.PB114 T
InPort_21412122_0 | SINK | 360.PB114 T
OutPort_21412145_2 | SOURCE | 360.PB114 T
InPort_21412147_2 | SINK | 360.PB114 T
OutPort_21412122_1 | SOURCE | 360.PB114 T
InPort_21449827_0 | SINK | 360.PB114 T
OutPort_21412147_1 | SOURCE | 360.PB114 T
InPort_21412194_0 | SINK | 360.PB114 T
OutPort_21412222_1 | SOURCE | 360.PB114 T
InPort_21412202_2 | SINK | 360.PB114 T
OutPort_21412194_1 | SOURCE | 360.PB114 T
InPort_21412222_2 | SINK | 360.PB114 T
OutPort_21412224_1 | SOURCE | 360.PB114 T
InPort_21412369_0 | SINK | 360.PB114 T
OutPort_21412348_2 | SOURCE | 360.PB114 T
InPort_21412734_1 | SINK | 360.PB114 T
OutPort_21414870_0 | SOURCE | 360.PB114 T
InPort_21412935_1 | SINK | 360.PB114 T
OutPort_21416187_0 | SOURCE | 360.PB114 T
InPort_21413009_0 | SINK | 360.PB114 T
OutPort_21415191_2 | SOURCE | 360.PB114 T
InPort_21416366_1 | SINK | 360.PB114 T
OutPort_21413009_1 | SOURCE | 360.PB114 T
InPort_21414922_1 | SINK | 360.PB114 T
OutPort_21413009_4 | SOURCE | 360.PB114 T
InPort_21416350_1 | SINK | 360.PB114 T
OutPort_21413009_5 | SOURCE | 360.PB114 T
InPort_21413280_1 | SINK | 360.PB114 T
OutPort_21415739_0 | SOURCE | 360.PB114 T
InPort_21413285_1 | SINK | 360.PB114 T
OutPort_21415787_0 | SOURCE | 360.PB114 T
InPort_21413347_1 | SINK | 360.PB114 T
OutPort_21416034_1 | SOURCE | 360.PB114 T
InPort_21416765_2 | SINK | 360.PB114 T
OutPort_21413433_0 | SOURCE | 360.PB114 T
InPort_21415191_1 | SINK | 360.PB114 T
OutPort_21413433_2 | SOURCE | 360.PB114 T
InPort_21415239_1 | SINK | 360.PB114 T
OutPort_21413433_3 | SOURCE | 360.PB114 T
InPort_21620652_2 | SINK | 360.PB114 A
OutPort_21413672_0 | SOURCE | 360.PB114 A
InPort_21413672_1 | SINK | 360.PB114 A
OutPort_21620656_1 | SOURCE | 360.PB114 A
InPort_21414870_1 | SINK | 360.PB114 T
OutPort_21414922_2 | SOURCE | 360.PB114 T
InPort_21415028_1 | SINK | 360.PB114 T
OutPort_21416328_0 | SOURCE | 360.PB114 T
InPort_21415651_0 | SINK | 360.PB114 T
OutPort_21415611_1 | SOURCE | 360.PB114 T
InPort_21415611_2 | SINK | 360.PB114 T
OutPort_21416558_0 | SOURCE | 360.PB114 T
InPort_21415930_1 | SINK | 360.PB114 T
OutPort_21415651_1 | SOURCE | 360.PB114 T
InPort_21415857_1 | SINK | 360.PB114 T
OutPort_21415651_2 | SOURCE | 360.PB114 T
InPort_21415739_1 | SINK | 360.PB114 T
OutPort_21415995_2 | SOURCE | 360.PB114 T
InPort_21415787_1 | SINK | 360.PB114 T
OutPort_21415860_2 | SOURCE | 360.PB114 T
InPort_21415849_0 | SINK | 360.PB114 T
OutPort_21415857_2 | SOURCE | 360.PB114 T
InPort_21415860_1 | SINK | 360.PB114 T
OutPort_21415849_1 | SOURCE | 360.PB114 T
InPort_21415922_0 | SINK | 360.PB114 T
OutPort_21415930_2 | SOURCE | 360.PB114 T
InPort_21415995_3 | SINK | 360.PB114 T
OutPort_21415922_1 | SOURCE | 360.PB114 T
InPort_21416034_0 | SINK | 360.PB114 T
OutPort_21415995_1 | SOURCE | 360.PB114 T
InPort_21416187_1 | SINK | 360.PB114 T
OutPort_21416208_1 | SOURCE | 360.PB114 T
InPort_21416195_0 | SINK | 360.PB114 T
OutPort_21416434_2 | SOURCE | 360.PB114 T
InPort_21416208_2 | SINK | 360.PB114 T
OutPort_21416195_1 | SOURCE | 360.PB114 T
InPort_21416328_1 | SINK | 360.PB114 T
OutPort_21416353_1 | SOURCE | 360.PB114 T
InPort_21416344_0 | SINK | 360.PB114 T
OutPort_21416350_2 | SOURCE | 360.PB114 T
InPort_21416353_2 | SINK | 360.PB114 T
OutPort_21416344_1 | SOURCE | 360.PB114 T
InPort_21416434_1 | SINK | 360.PB114 T
OutPort_21416558_2 | SOURCE | 360.PB114 T
InPort_21416558_1 | SINK | 360.PB114 T
OutPort_21416765_1 | SOURCE | 360.PB114 T
InPort_21433908_2 | SINK | 360.PB114 T
OutPort_21434616_0 | SOURCE | 360.PB114 T
InPort_21435031_1 | SINK | 360.PB114 A
InPort_21434616_1 | SINK | 360.PB114 T
OutPort_21434648_1 | SOURCE | 360.PB114 T
InPort_21434648_2 | SINK | 360.PB114 T
OutPort_21434838_0 | SOURCE | 360.PB114 T
InPort_21434656_1 | SINK | 360.PB114 T
OutPort_21434823_1 | SOURCE | 360.PB114 T
InPort_21434664_0 | SINK | 360.PB114 T
OutPort_21434819_2 | SOURCE | 360.PB114 T
InPort_21434823_2 | SINK | 360.PB114 T
OutPort_21434664_1 | SOURCE | 360.PB114 T
InPort_21434704_0 | SINK | 360.PB114 T
OutPort_21434715_2 | SOURCE | 360.PB114 T
InPort_21434819_1 | SINK | 360.PB114 T
OutPort_21434704_1 | SOURCE | 360.PB114 T
InPort_21435229_1 | SINK | 360.PB114 A
OutPort_21435031_0 | SOURCE | 360.PB114 A
InPort_21435214_1 | SINK | 360.PB114 A
OutPort_21435229_2 | SOURCE | 360.PB114 A
InPort_21435227_2 | SINK | 360.PB114 A
OutPort_21435243_0 | SOURCE | 360.PB114 A
InPort_21449869_2 | SINK | 360.PB114 T
OutPort_21449827_1 | SOURCE | 360.PB114 T
Port_12026068_1 | SOURCEANDSINK | 370.PB102 R
Port_20415217_0 | SOURCEANDSINK | 370.PB102 R
Port_12026068_2 | SOURCEANDSINK | 370.PB102 R
Port_12026078_1 | SOURCEANDSINK | 370.PB102 R
Port_12026141_1 | SOURCEANDSINK | 370.PB102 T
Port_12026157_1 | SOURCEANDSINK | 370.PB102 T
Port_12026141_2 | SOURCEANDSINK | 370.PB102 T
Port_20415236_0 | SOURCEANDSINK | 370.PB102 T
Port_20416227_1 | SOURCEANDSINK | 370.PB102 T
Port_20418620_0 | SOURCEANDSINK | 370.PB102 T
Port_20447113_1 | SOURCEANDSINK | 370.PB102 T
Port_20418620_1 | SOURCEANDSINK | 370.PB102 T
Port_20447047_0 | SOURCEANDSINK | 370.PB102 R
Port_20447252_1 | SOURCEANDSINK | 370.PB102 R
Port_20447047_1 | SOURCEANDSINK | 370.PB102 R
Port_20447113_2 | SOURCEANDSINK | 370.PB102 T
Port_20447115_1 | SOURCEANDSINK | 370.PB102 T
Port_20447185_1 | SOURCEANDSINK | 370.PB102 R
Port_20447254_0 | SOURCEANDSINK | 370.PB102 R
Port_20447185_2 | SOURCEANDSINK | 370.PB102 R
Port_20447187_1 | SOURCEANDSINK | 370.PB102 R
Port_20447252_2 | SOURCEANDSINK | 370.PB102 R
Port_20447254_1 | SOURCEANDSINK | 370.PB102 R
Port_22160854_0 | SOURCEANDSINK | 370.PB102 R
Port_22161568_1 | SOURCEANDSINK | 370.PB102 R
Port_22160854_1 | SOURCEANDSINK | 370.PB102 R
Port_22160914_0 | SOURCEANDSINK | 370.PB102 T
Port_22161343_1 | SOURCEANDSINK | 370.PB102 T
Port_22160914_1 | SOURCEANDSINK | 370.PB102 T
Port_22161343_2 | SOURCEANDSINK | 370.PB102 T
Port_22161345_1 | SOURCEANDSINK | 370.PB102 T
Port_22161568_2 | SOURCEANDSINK | 370.PB102 R
Port_22161570_1 | SOURCEANDSINK | 370.PB102 R
Port_22163401_1 | SOURCEANDSINK | 370.PB102 R
Port_22163437_1 | SOURCEANDSINK | 370.PB102 R 2
Port_22163554_0 | SOURCEANDSINK | 370.PB102 R 2
Port_22163809_1 | SOURCEANDSINK | 370.PB102 R 2
Port_22163554_1 | SOURCEANDSINK | 370.PB102 R 2
Port_22163581_0 | SOURCEANDSINK | 370.PB102 T
Port_22163998_1 | SOURCEANDSINK | 370.PB102 T
Port_22163581_1 | SOURCEANDSINK | 370.PB102 T
Port_22163809_2 | SOURCEANDSINK | 370.PB102 R 2
Port_22163815_1 | SOURCEANDSINK | 370.PB102 R 2
Port_22163998_2 | SOURCEANDSINK | 370.PB102 T
Port_22164010_1 | SOURCEANDSINK | 370.PB102 T
Port_22178189_1 | SOURCEANDSINK
Port_22178376_1 | SOURCEANDSINK
Port_23486728_1 | SOURCEANDSINK | K 390
Port_23486729_0 | SOURCEANDSINK | K 390
Port_23486729_1 | SOURCEANDSINK | K 390
Port_23486731_1 | SOURCEANDSINK | K 391
Port_23486732_0 | SOURCEANDSINK | K 391
Port_23486732_1 | SOURCEANDSINK | K 391
Port_23486787_1 | SOURCEANDSINK | K 392
Port_23486788_0 | SOURCEANDSINK | K 392
Port_23486788_1 | SOURCEANDSINK | K 392
Port_23486790_1 | SOURCEANDSINK | K 393
Port_23486791_0 | SOURCEANDSINK | K 393
Port_23486791_1 | SOURCEANDSINK | K 393
Port_14659186_1 | SOURCEANDSINK | 310.TO500 1 (2)
Port_14659541_1 | SOURCEANDSINK | 310.SB801 (1)
Port_15668327_1 | SOURCEANDSINK | 310.TO601
Port_15668424_1 | SOURCEANDSINK | 310.TO601
Port_18596079_0 | SOURCEANDSINK | 310.TO500 1 (2)
Port_18596444_0 | SOURCEANDSINK | 310.TO500 1 (2)
Port_18597003_1 | SOURCEANDSINK | 310.TO100 78
InPort_18816543_1 | SINK | 310.TO100 78
Port_18865206_0 | SOURCEANDSINK | 310.TO100 78
Port_18866135_0 | SOURCEANDSINK | 310.TO200 1
Port_18872565_0 | SOURCEANDSINK | 310.TO500 1 (2)
OutPort_18877703_1 | SOURCE
Port_19021846_0 | SOURCEANDSINK | 310.TO500 1 (2)
Port_19022485_0 | SOURCEANDSINK | 310.TO500 1 (2)
Port_20251201_1 | SOURCEANDSINK | 310.TO100 78
Port_20251403_1 | SOURCEANDSINK | 310.TO100 78
InPort_10504172_1 | SINK | 332.PB001 11
OutPort_10504170_1 | SOURCE | 332.PB001 11
InPort_10504223_1 | SINK | 332.PB001 11
OutPort_10504221_1 | SOURCE | 332.PB001 11
InPort_10504239_1 | SINK | 332.PB001 11
OutPort_10504237_1 | SOURCE | 332.PB001 11
InPort_10504259_1 | SINK | 332.PB001 11
OutPort_10504257_1 | SOURCE | 332.PB001 11
InPort_10504277_1 | SINK | 332.PB001 11
OutPort_10504275_1 | SOURCE | 332.PB001 11
InPort_10504295_1 | SINK | 332.PB001 11
OutPort_10504293_1 | SOURCE | 332.PB001 11
InPort_10504313_1 | SINK | 332.PB001 11
OutPort_10504311_1 | SOURCE | 332.PB001 11
InPort_10504475_1 | SINK | 332.PB001 11
OutPort_10504473_1 | SOURCE | 332.PB001 11
InPort_10504493_1 | SINK | 332.PB001 11
OutPort_10504491_1 | SOURCE | 332.PB001 11
InPort_10504511_1 | SINK | 332.PB001 11
OutPort_10504509_1 | SOURCE | 332.PB001 11
InPort_10504529_1 | SINK | 332.PB001 11
OutPort_10504527_1 | SOURCE | 332.PB001 11
InPort_11541049_0 | SINK | 332.PB001 01 (1)
OutPort_11541048_1 | SOURCE | 332.PB001 01 (1)
InPort_11541601_0 | SINK | 332.PB001 01 (1)
OutPort_11541600_1 | SOURCE | 332.PB001 01 (1)
InPort_12558331_0 | SINK | 332.PB001 01 (1)
OutPort_12558330_1 | SOURCE | 332.PB001 01 (1)
InPort_12558334_0 | SINK | 332.PB001 01 (1)
OutPort_12558333_1 | SOURCE | 332.PB001 01 (1)
InPort_19533646_0 | SINK | 332.PB001 11
OutPort_19474077_1 | SOURCE | 332.PB001 11
InPort_19474137_1 | SINK | 332.PB001 11
OutPort_19474135_1 | SOURCE | 332.PB001 11
InPort_19474199_1 | SINK | 332.PB001 11
OutPort_19474197_1 | SOURCE | 332.PB001 11
InPort_19474288_1 | SINK | 332.PB001 11
OutPort_19474286_1 | SOURCE | 332.PB001 11
InPort_19474469_1 | SINK | 332.PB001 11
OutPort_19474467_1 | SOURCE | 332.PB001 11
InPort_19526418_1 | SINK | 332.PB001 11
OutPort_19526416_1 | SOURCE | 332.PB001 11
InPort_19527913_1 | SINK | 332.PB001 11
OutPort_19527911_1 | SOURCE | 332.PB001 11
InPort_19527921_1 | SINK | 332.PB001 11
OutPort_19527919_1 | SOURCE | 332.PB001 11
InPort_19552282_1 | SINK | 332.PB001 11
OutPort_19552283_0 | SOURCE | 332.PB001 11
Port_6973821_1 | SOURCEANDSINK
Port_6974481_1 | SOURCEANDSINK
Port_6974519_1 | SOURCEANDSINK
Port_7143913_1 | SOURCEANDSINK
Port_7143918_1 | SOURCEANDSINK
Port_7143919_1 | SOURCEANDSINK
Port_7143920_1 | SOURCEANDSINK
Port_7143921_1 | SOURCEANDSINK
Port_7143936_1 | SOURCEANDSINK
Port_7220613_1 | SOURCEANDSINK
Port_9532383_1 | SOURCEANDSINK
Port_9532446_1 | SOURCEANDSINK
Port_9532477_1 | SOURCEANDSINK
Port_9532498_1 | SOURCEANDSINK
Port_9532514_1 | SOURCEANDSINK
Port_9532535_1 | SOURCEANDSINK
Port_9532545_1 | SOURCEANDSINK
Port_9532559_1 | SOURCEANDSINK
Port_9532566_1 | SOURCEANDSINK
Port_9532575_1 | SOURCEANDSINK
Port_9532946_1 | SOURCEANDSINK
Port_9796203_1 | SOURCEANDSINK
Port_10157307_1 | SOURCEANDSINK
Port_10755959_1 | SOURCEANDSINK
Port_10942801_1 | SOURCEANDSINK

# IfcDoor: A200 - Slagdør - Enfløyet:A244 - DI_LSO - 0890 x 2190 mm, A200 - Slagdør - Enfløyet:A244 - DI_LSO - 0890 x 2190 mm:35870863
In: Nivå F
Type - OperationType: SINGLE_SWING_RIGHT; ParameterTakesPrecedence: no; Sizeable: no; Material: _NSW Stål - rustfritt, _NSW Stål, N_Door - Threshold, N_Door - Panel
Type - IfcDoorPanelProperties - PanelOperation: SWINGING
OverallHeight: 2210 mm; OverallWidth: 910 mm
ePset_Simplebim - Assembly Level: Leaf
AVINOR - 05_ID-nummer: +BR003=244.05000-DI0001; 08_Status: S4; 03_Ansvar: 188110; 07_Fase: F50; 02_Prosjekt: 10003898; 01_Lufthavnkode: ENBR
ePset_LocationTool - Splitting: ORIGINAL
ePset_SimplebimBasicQuantities - Height, opening (Simplebim): 2210 mm; Width, opening (Simplebim): 910 mm; Area, opening (Simplebim): 2.0111 m2; Width (Simplebim): 890 mm; Height (Simplebim): 2190 mm; Length, frame (Simplebim): 5270 mm; Area (Simplebim): 1.9491 m2
Pset_DoorCommon - Reference: A200 - Slagdør - Enfløyet:A244 - DI_LSO - 0890 x 2190 mm

# IfcDoor: A200 - Slagdør - Enfløyet:A244 - DI_LSO - 0990 x 2190 mm (4)
In: Nivå F
Type - OperationType: SINGLE_SWING_RIGHT; ParameterTakesPrecedence: no; Sizeable: no; Material: _NSW Stål - rustfritt, _NSW Stål, N_Door - Threshold, N_Door - Panel
Type - IfcDoorPanelProperties - PanelOperation: SWINGING
OverallWidth: 1010 mm
ePset_Simplebim - Assembly Level: Leaf
Pset_DoorCommon - Reference: A200 - Slagdør - Enfløyet:A244 - DI_LSO - 0990 x 2190 mm
ePset_LocationTool - Splitting: ORIGINAL
ePset_SimplebimBasicQuantities - Area (Simplebim): 2.1681 m2; Width, opening (Simplebim): 1010 mm; Width (Simplebim): 990 mm; Height (Simplebim): 2190 mm; Length, frame (Simplebim): 5370 mm
AVINOR - 08_Status: S4; 07_Fase: F90
Name (A200 - Slagdør - Enfløyet:A244 - DI_LSO - 0990 x 2190 mm:...) | OverallHeight (mm) = Height, opening (Simplebim) (mm) | Area, opening (Simplebim) (m2) | 05_ID-nummer
6028097 | 2200 | 2.222 | +BR003=244.06053
6028098 | 2200 | 2.222 | +BR003=244.06054
17754475 | 2200 | 2.222 | +BR003=244.06055
22524766 | 2210 | 2.2321 | +BR003=244.06052

# IfcFlowController: LUFTEPOTTE--:LUFTEPOTTE (4)
In: Nivå F
Type - Material: 2d_hide, Metal - Caleffi - Brass
Classification: D2020300 Domestic Water Supply Equipment (Uniformat)
ePset_Simplebim - Assembly Level: Leaf
AVINOR - 08_Status: S4; 07_Fase: F90
ePset_LocationTool - Splitting: ORIGINAL
Name (LUFTEPOTTE--:LUFTEPOTTE:...) | 05_ID-nummer | Group
23486728 | +BR003=370.PB102-ML003 | K 390
23486731 | +BR003=370.PB102-ML004 | K 391
23486787 | +BR003=370.PB102-ML005 | K 392
23486790 | +BR003=370.PB102-ML006 | K 393

# IfcFlowController: REGULERINGSVENTIL - MANUELL--SV001T:REGULERINGSVENTIL - MANUELL-20-SV001T, REGULERINGSVENTIL - MANUELL--SV001T:REGULERINGSVENTIL - MANUELL-20-SV001T:20447185
In: Nivå F
Type - Material: 2d_hide
ePset_Simplebim - Assembly Level: Leaf
AVINOR - 08_Status: S4; 07_Fase: F90; 05_ID-nummer: +BR003=370.PB102-SV006
ePset_LocationTool - Splitting: ORIGINAL
Group: 370.PB102 R

# IfcFlowController: REGULERINGSVENTIL - MANUELL--SV01T:REGULERINGSVENTIL - MANUELL-32-SV001T (2)
In: Nivå F
Type - Material: 2d_hide
ePset_Simplebim - Assembly Level: Leaf
ePset_LocationTool - Splitting: ORIGINAL
AVINOR - 08_Status: S4; 07_Fase: F90
Name (REGULERINGSVENTIL - MANUELL--SV01T:REGULERINGSVENTIL - MANUELL-32-SV001T:...) | 05_ID-nummer | Group
22161568 | +BR003=370.PB102-SV009 | 370.PB102 R
22163809 | +BR003=370.PB102-SV010 | 370.PB102 R 2

# IfcFlowController: REGULERINGSVENTIL - MANUELL--SV01T:REGULERINGSVENTIL - MANUELL-40-SV001T, REGULERINGSVENTIL - MANUELL--SV01T:REGULERINGSVENTIL - MANUELL-40-SV001T:12026068
In: Nivå F
Type - Material: 2d_hide
ePset_Simplebim - Assembly Level: Leaf
AVINOR - 08_Status: S4; 05_ID-nummer: +BR003=370.PB102-SV002; 07_Fase: F90
ePset_LocationTool - Splitting: ORIGINAL
Group: 370.PB102 R

# IfcFlowController: REGULERINGSVENTIL - MOTORSTYRT- 1-SB001T:REGULERINGSVENTIL - MOTORSTYRT-SB001T, REGULERINGSVENTIL - MOTORSTYRT- 1-SB001T:REGULERINGSVENTIL - MOTORSTYRT-SB001T:20447252
In: Nivå F
Type - Material: 2d_hide
ePset_Simplebim - Assembly Level: Leaf
AVINOR - 08_Status: S4; 07_Fase: F90; 05_ID-nummer: +BR003=370.PB102-SB010
ePset_LocationTool - Splitting: ORIGINAL
Group: 370.PB102 R

# IfcFlowController: STENGEVENTIL - MANUELL - 4 - SM:STENGEVENTIL - MANUELL - 20 - SM01T, STENGEVENTIL - MANUELL - 4 - SM:STENGEVENTIL - MANUELL - 20 - SM01T:18866150
In: Nivå F
Type - Material: <Unnamed>
ePset_Simplebim - Assembly Level: Leaf
ePset_LocationTool - Splitting: ORIGINAL
AVINOR - 08_Status: S4; 07_Fase: F90; 05_ID-nummer: +BR003=310.TO200-SM241

# IfcFlowController: STENGEVENTIL - MANUELL - 4 - SM:STENGEVENTIL - MANUELL - 25 - SM01T, STENGEVENTIL - MANUELL - 4 - SM:STENGEVENTIL - MANUELL - 25 - SM01T:18866161
In: Nivå F
Type - Material: <Unnamed>
ePset_Simplebim - Assembly Level: Leaf
ePset_LocationTool - Splitting: ORIGINAL
AVINOR - 08_Status: S4; 07_Fase: F90; 05_ID-nummer: +BR003=310.TO100-SM194

# IfcFlowController: STENGEVENTIL - MANUELL- 1-SM01T:STENGEVENTIL - MANUELL-20-SM001T, STENGEVENTIL - MANUELL- 1-SM01T:STENGEVENTIL - MANUELL-20-SM001T:20447113
In: Nivå F
Type - Material: <Unnamed>
ePset_Simplebim - Assembly Level: Leaf
ePset_LocationTool - Splitting: ORIGINAL
AVINOR - 08_Status: S4; 07_Fase: F90; 05_ID-nummer: +BR003=370.PB102-SM008
Group: 370.PB102 T

# IfcFlowController: STENGEVENTIL - MANUELL- 1-SM01T:STENGEVENTIL - MANUELL-32-SM001T (2)
In: Nivå F
Type - Material: <Unnamed>
ePset_Simplebim - Assembly Level: Leaf
ePset_LocationTool - Splitting: ORIGINAL
AVINOR - 08_Status: S4; 07_Fase: F90
Group: 370.PB102 T
Name (STENGEVENTIL - MANUELL- 1-SM01T:STENGEVENTIL - MANUELL-32-SM001T:...) | 05_ID-nummer
22161343 | +BR003=370.PB102-SM010
22163998 | +BR003=370.PB102-SM011

# IfcFlowController: STENGEVENTIL - MANUELL- 1-SM01T:STENGEVENTIL - MANUELL-40-SM001T, STENGEVENTIL - MANUELL- 1-SM01T:STENGEVENTIL - MANUELL-40-SM001T:12026141
In: Nivå F
Type - Material: <Unnamed>
ePset_Simplebim - Assembly Level: Leaf
AVINOR - 08_Status: S4; 05_ID-nummer: +BR003=370.PB102-SM002; 07_Fase: F90
ePset_LocationTool - Splitting: ORIGINAL
Group: 370.PB102 T

# IfcFlowController: STENGEVENTIL - MOTORSTYRT - -:STENGEVENTIL - MOTORSTYRT - -, STENGEVENTIL - MOTORSTYRT - -:STENGEVENTIL - MOTORSTYRT - -:18866912
In: Nivå F
Type - Material: 2d_hide
ePset_Simplebim - Assembly Level: Leaf
AVINOR - 08_Status: S4; 07_Fase: F90; 05_ID-nummer: +BR003=310.TO100-SC004
ePset_LocationTool - Splitting: ORIGINAL

# IfcFlowFitting: Endcap 5521:Lindab EPF (2)
Type - Material: DF_Material1
ePset_Simplebim - Assembly Level: Leaf
AVINOR - 08_Status: S4; 07_Fase: F90
ePset_LocationTool - Splitting: ORIGINAL
Name (Endcap 5521:Lindab EPF:...) | In | 05_ID-nummer | Group
14001323 | Nivå E | +BR003=360.PB116-KK001T | 360.PB116 T
21416366 | Nivå F | +BR003=360.PB114-KK001T | 360.PB114 T

# IfcFlowFitting: MC_Ladder Horizontal Tee:10mm Radius (4)
In: Nivå F
Type - Material: <Unnamed>
ePset_Simplebim - Assembly Level: Leaf
AVINOR - 08_Status: S4; 07_Fase: F90; 05_ID-nummer: +BR003=411.OO001-CR001T
ePset_LocationTool - Splitting: ORIGINAL
Name (MC_Ladder Horizontal Tee:10mm Radius:...)
8618442
8618461
8618634
13223399

# IfcFlowFitting: MC_Ladder Vertical Inside Bend_Short:Standard 10mm (10)
Type - Material: <Unnamed>
ePset_Simplebim - Assembly Level: Leaf
ePset_LocationTool - Splitting: ORIGINAL
AVINOR - 08_Status: S4; 07_Fase: F90; 05_ID-nummer: +BR003=411.OO001-CR001T
Name (MC_Ladder Vertical Inside Bend_Short:Standard 10mm:...) | In
5957554 | Nivå B
5957814 | Nivå B
5957949 | Nivå B
8803188 | Nivå F
13268001 | Nivå F
13317116 | Nivå F
13317290 | Nivå F
13317333 | Nivå F
13318069 | Nivå F
13318093 | Nivå F

# IfcFlowFitting: MC_Ladder Vertical Outside Bend:Standard 10mm (10)
Type - Material: <Unnamed>
ePset_Simplebim - Assembly Level: Leaf
ePset_LocationTool - Splitting: ORIGINAL
AVINOR - 08_Status: S4; 07_Fase: F90; 05_ID-nummer: +BR003=411.OO001-CR001T
Name (MC_Ladder Vertical Outside Bend:Standard 10mm:...) | In
5957543 | Nivå B
5957775 | Nivå B
5957940 | Nivå B
13267997 | Nivå B
13267999 | Nivå F
13316142 | Nivå F
13317119 | Nivå F
13317330 | Nivå F
13317912 | Nivå F
13318090 | Nivå F

# IfcFlowFitting: M_Ladder Horizontal Bend:Standard, M_Ladder Horizontal Bend:Standard:8618412
In: Nivå F
Type - Material: <Unnamed>
ePset_Simplebim - Assembly Level: Leaf
ePset_LocationTool - Splitting: ORIGINAL
AVINOR - 08_Status: S4; 07_Fase: F90; 05_ID-nummer: +BR003=411.OO001-CR001T

# IfcFlowFitting: magicirc_elbow_full_radius_1:magicirc_elbow_full_radius_001 (27)
Type - Material: <Unnamed>
ePset_Simplebim - Assembly Level: Leaf
ePset_LocationTool - Splitting: ORIGINAL
AVINOR - 08_Status: S4; 07_Fase: F90; 05_ID-nummer: +BR003=360.PB114-KK001T
Name (magicirc_elbow_full_radius_1:magicirc_elbow_full_radius_001:...) | In | Group
14508763 | Nivå F | 360.PB114 A
18960824 | Nivå E | 360.PB114 A
18960837 | Nivå E | 360.PB114 A
18961123 | Nivå E | 360.PB114 A
18961185 | Nivå E | 360.PB114 A
21351881 | Nivå F | 360.PB114 A
21351896 | Nivå F | 360.PB114 A
21354807 | Nivå F | 360.PB114 A
21355283 | Nivå F | 360.PB114 A
21373645 | Nivå F | 360.PB114 A
21374068 | Nivå F | 360.PB114 A
21393123 | Nivå F | 360.PB114 T
21393131 | Nivå F | 360.PB114 T
21393133 | Nivå F | 360.PB114 T
21393195 | Nivå F | 360.PB114 A
21393197 | Nivå F | 360.PB114 T
21412098 | Nivå F | 360.PB114 T
21412145 | Nivå F | 360.PB114 T
21412147 | Nivå F | 360.PB114 T
21415611 | Nivå F | 360.PB114 T
21415860 | Nivå F | 360.PB114 T
21416208 | Nivå F | 360.PB114 T
21416353 | Nivå F | 360.PB114 T
21434819 | Nivå F | 360.PB114 T
21434823 | Nivå F | 360.PB114 T
21449869 | Nivå F | 360.PB114 T
21620652 | Nivå F | 360.PB114 A

# IfcFlowFitting: magicirc_joint_1:magicirc_joint_001 (4)
Type - Material: <Unnamed>
ePset_Simplebim - Assembly Level: Leaf
ePset_LocationTool - Splitting: ORIGINAL
AVINOR - 08_Status: S4; 07_Fase: F90
Name (magicirc_joint_1:magicirc_joint_001:...) | In | 05_ID-nummer | Group
14508930 | Nivå E | +BR003=360.PB114-KK001T | 360.PB114 T
14551285 | Nivå E | +BR003=360.PB116-KK001T | 360.PB116 A
18182408 | Nivå C | +BR003=360.PB114-KK001T | 360.PB114 A
21341210 | Nivå F | +BR003=360.PB114-KK001T | 360.PB114 A

# IfcFlowFitting: magicirc_multi_shape_trans_001:magicirc_multi_shape_trans_001, magicirc_multi_shape_trans_001:magicirc_multi_shape_trans_001:21620656
In: Nivå F
Type - Material: Material_Duct
ePset_Simplebim - Assembly Level: Leaf
ePset_LocationTool - Splitting: ORIGINAL
AVINOR - 08_Status: S4; 07_Fase: F90; 05_ID-nummer: +BR003=360.PB114-KK001T
Group: 360.PB114 A

# IfcFlowFitting: magicirc_reduction_001:magicirc_reduction_001 (20)
Type - Material: Material_Duct
ePset_Simplebim - Assembly Level: Leaf
ePset_LocationTool - Splitting: ORIGINAL
AVINOR - 08_Status: S4; 07_Fase: F90; 05_ID-nummer: +BR003=360.PB114-KK001T
Name (magicirc_reduction_001:magicirc_reduction_001:...) | In | Group
18968418 | Nivå E | 360.PB114 A
18969051 | Nivå E | 360.PB114 A
19854624 | Nivå E | 360.PB114 A
21354819 | Nivå F | 360.PB114 A
21356074 | Nivå F | 360.PB114 A
21356076 | Nivå F | 360.PB114 A
21374534 | Nivå F | 360.PB114 A
21374540 | Nivå F | 360.PB114 A
21393105 | Nivå F | 360.PB114 T
21393109 | Nivå F | 360.PB114 T
21412088 | Nivå F | 360.PB114 A
21412091 | Nivå F | 360.PB114 T
21412093 | Nivå F | 360.PB114 A
21412202 | Nivå F | 360.PB114 T
21412348 | Nivå F | 360.PB114 T
21412350 | Nivå F | 360.PB114 T
21415930 | Nivå F | 360.PB114 T
21416765 | Nivå F | 360.PB114 T
21434648 | Nivå F | 360.PB114 T
21435229 | Nivå F | 360.PB114 A

# IfcFlowFitting: magicirc_tapoutlet_1:magicirc_tapoutlet_001 (21)
In: Nivå F
Type - Material: <Unnamed>
ePset_Simplebim - Assembly Level: Leaf
ePset_LocationTool - Splitting: ORIGINAL
AVINOR - 08_Status: S4; 07_Fase: F90
Name (magicirc_tapoutlet_1:magicirc_tapoutlet_001:...) | 05_ID-nummer | Group
14508731 | +BR003=360.PB114-KK001T | 360.PB114 A
14508734 | +BR003=360.PB114-KK001T | 360.PB114 A
14508760 | +BR003=360.PB114-KK001T | 360.PB114 A
14508821 | +BR003=360.PB114-KK001T | 360.PB114 T
14508826 | +BR003=360.PB114-KK001T | 360.PB114 T
14551374 | +BR003=360.PB116-KK001T | 360.PB116 A
14551481 | +BR003=360.PB116-KK001T | 360.PB116 A
14551509 | +BR003=360.PB116-KK001T | 360.PB116 A
21374536 | +BR003=360.PB114-KK001T | 360.PB114 A
21374538 | +BR003=360.PB114-KK001T | 360.PB114 A
21393115 | +BR003=360.PB114-KK001T | 360.PB114 T
21412074 | +BR003=360.PB114-KK001T | 360.PB114 T
21412086 | +BR003=360.PB114-KK001T | 360.PB114 A
21414922 | +BR003=360.PB114-KK001T | 360.PB114 T
21415191 | +BR003=360.PB114-KK001T | 360.PB114 T
21415239 | +BR003=360.PB114-KK001T | 360.PB114 T
21415857 | +BR003=360.PB114-KK001T | 360.PB114 T
21416350 | +BR003=360.PB114-KK001T | 360.PB114 T
21416434 | +BR003=360.PB114-KK001T | 360.PB114 T
21434715 | +BR003=360.PB114-KK001T | 360.PB114 T
21435227 | +BR003=360.PB114-KK001T | 360.PB114 A

# IfcFlowFitting: magicirc_tee_centric_90_1:magicirc_tee_centric_90_001 (2)
Type - Material: <Unnamed>
ePset_Simplebim - Assembly Level: Leaf
ePset_LocationTool - Splitting: ORIGINAL
AVINOR - 08_Status: S4; 07_Fase: F90; 05_ID-nummer: +BR003=360.PB114-KK001T
Name (magicirc_tee_centric_90_1:magicirc_tee_centric_90_001:...) | In | Group
18969027 | Nivå E | 360.PB114 A
21415995 | Nivå F | 360.PB114 T

# IfcFlowFitting: magirect_reduction1_001:magirect_reduction1_001 (3)
Type - Material: Material_Duct
ePset_Simplebim - Assembly Level: Leaf
ePset_LocationTool - Splitting: ORIGINAL
AVINOR - 08_Status: S4; 07_Fase: F90; 05_ID-nummer: +BR003=360.PB116-KK002T
Group: 360.PB116 T
Name (magirect_reduction1_001:magirect_reduction1_001:...) | In
14508697 | Nivå E
19881607 | Nivå E
19881609 | Nivå F

# IfcFlowSegment: Cable Tray with Fittings:Armaturskinne (2)
In: Nivå F
Type - PredefinedType: CABLETRAYSEGMENT
ePset_Simplebim - Assembly Level: Leaf
AVINOR - 08_Status: S4; 07_Fase: F90; 05_ID-nummer: +BR003=411.OO001-CR012T
ePset_LocationTool - Splitting: ORIGINAL
ePset_SimplebimBasicQuantities - Height (Simplebim): 50 mm; Width (Simplebim): 100 mm; Length (Simplebim): 2720 mm
Name (Cable Tray with Fittings:Armaturskinne:...)
8666939
8666940

# IfcFlowSegment: Cable Tray with Fittings:Kabelbro (53)
Type - PredefinedType: CABLETRAYSEGMENT
ePset_Simplebim - Assembly Level: Leaf
AVINOR - 08_Status: S4; 07_Fase: F90; 05_ID-nummer: +BR003=411.OO001-CR001T
Name (Cable Tray with Fittings:Kabelbro:...) | In | Length (Simplebim) (mm) | Width (Simplebim) (mm) | Height (Simplebim) (mm) | Splitting
1902943 | Nivå B | 2895 | 60 | 600 | ORIGINAL
1903541 | Nivå B | 2895 | 60 | 400 | ORIGINAL
1903542 | Nivå B | 2895 | 60 | 600 | ORIGINAL
1903543 | Nivå B | 2895 | 60 | 400 | ORIGINAL
1903544 | Nivå B | 2895 | 60 | 600 | ORIGINAL
1903545 | Nivå B | 2895 | 60 | 400 | ORIGINAL
1988257 | Nivå F | 400 | 37.7537 | 60 | ORIGINAL
1988449 | Nivå F | 721.09 | 400 | 60 | ORIGINAL
1988907 | Nivå F | 400 | 37.7537 | 60 | ORIGINAL
1989701 | Nivå F | 10969 | 400 | 60 | ORIGINAL
1990549 | Nivå F | 400 | 147.006 | 60 | ORIGINAL
2405185 | Nivå B | 2895 | 60 | 600 | ORIGINAL
2405336 | Nivå B | 2895 | 60 | 600 | ORIGINAL
2405544 | Nivå B | 2895 | 60 | 600 | ORIGINAL
5957535 | Nivå B | 600 | 60 | 387 | ORIGINAL
5957539 | Nivå B | 600 | 57.0219 | 60 | ORIGINAL
5957546 | Nivå B | 600 | 60 | 302 | ORIGINAL
5957750 | Nivå B | 600 | 60 | 387 | ORIGINAL
5957767 | Nivå B | 600 | 57.0219 | 60 | ORIGINAL
5957778 | Nivå B | 600 | 60 | 302 | ORIGINAL
5957897 | Nivå B | 400 | 60 | 387 | ORIGINAL
5957930 | Nivå B | 400 | 57.0219 | 60 | ORIGINAL
5957943 | Nivå B | 400 | 60 | 302 | ORIGINAL
8091606 | Nivå F | 2895 | 60 | 600 | ORIGINAL
8170513 | Nivå A | 405 | 60 | 400 | ORIGINAL
8170536 | Nivå B | 405 | 60 | 400 | ORIGINAL
8618635 | Nivå F | 1470.27 | 400 | 60 | ORIGINAL
8803181 | Nivå F | 420.072 | 400 | 356.219 | ORIGINAL
8803187 | Nivå F | 3077.64 | 400 | 60 | ORIGINAL
13223280 | Nivå B | 500.449 | 60 | 400.56 | ORIGINAL
13223378 | Nivå F | 421.928 | 400 | 326.204 | ORIGINAL
13223400 | Nivå F | 775.795 | 400 | 60 | ORIGINAL
13224324 | Nivå F | 2783.93 | 400 | 60 | ORIGINAL
13267995 | Nivå F | 1539.15 | 400 | 60 | ORIGINAL
13267996 | Nivå F | 400 | 283.711 | 60 | ORIGINAL
13316070 | Nivå F | 423.868 | 400 | 241.078 | ORIGINAL
13316551 | Nivå F | 1044.9 | 400 | 60 | ORIGINAL
13316600 | Nivå F | 1114.87 | 400 | 60 | ORIGINAL
13316601 | Nivå F | 456.594 | 400 | 286.595 | ORIGINAL
13316832 | Nivå F | 400 | 345.579 | 275.317 | ORIGINAL
13317038 | Nivå F | 400 | 3.58267 | 60 | ORIGINAL
13317825 | Nivå F | 400 | 250 | 60 | ORIGINAL
13317840 | Nivå F | 565.112 | 400 | 60 | ORIGINAL
13317873 | Nivå F | 400 | 171.63 | 134.789 | ORIGINAL
13318005 | Nivå F | 400 | 238.221 | 144.966 | ORIGINAL
16489651 | Nivå F | 2498.94 | 300 | 60 | ORIGINAL
8170543 | Nivå B | 755 | 60 | 600 | RESULT
8170545 | Nivå B | 755 | 60 | 600 | RESULT
8170532 | Nivå B | 755 | 60 | 600 | RESULT
8170534 | Nivå B | 755 | 60 | 600 | RESULT
8170539 | Nivå B | 755 | 60 | 600 | RESULT
8170510 | Nivå B | 600 | 60 | 350 | RESULT
8170511 | Nivå B | 600 | 60 | 350 | RESULT

# IfcFlowSegment: Cable Tray with Fittings:Strømskinne, Cable Tray with Fittings:Strømskinne:8091605
In: Nivå F
Type - PredefinedType: CABLETRAYSEGMENT
ePset_Simplebim - Assembly Level: Leaf
ePset_LocationTool - Splitting: RESULT
ePset_SimplebimBasicQuantities - Width (Simplebim): 250 mm; Height (Simplebim): 250 mm; Length (Simplebim): 3850 mm
AVINOR - 08_Status: S4; 07_Fase: F90; 05_ID-nummer: +BR003=432.OO003-KS003T

# IfcFlowSegment: Cable Tray with Fittings:VEGGKANAL (3)
In: Nivå F
Type - PredefinedType: CABLETRAYSEGMENT
ePset_Simplebim - Assembly Level: Leaf
ePset_LocationTool - Splitting: ORIGINAL
AVINOR - 08_Status: S4; 07_Fase: F90
Name (Cable Tray with Fittings:VEGGKANAL:...) | Width (Simplebim) (mm) | Height (Simplebim) (mm) | Length (Simplebim) (mm) | 05_ID-nummer
13268119 | 72 | 123 | 1994 | +BR003=411.OO001-CR001T
13268120 | 123 | 72 | 1020 | +BR003=411.OO001-CR001T
13339049 | 50 | 100 | 2850 | +BR003=411.OO002-KK001T

# IfcFlowSegment: Conduit without Fittings:Conduit (40)
In: Nivå F
Type - PredefinedType: CONDUITSEGMENT
ePset_Simplebim - Assembly Level: Leaf
ePset_SimplebimBasicQuantities - Height (Simplebim): 25 mm
AVINOR - 05_ID-nummer: +BR003=411.OO003-KQ001T; 08_Status: S4; 07_Fase: F90
Name (Conduit without Fittings:Conduit:...) | Width (Simplebim) (mm) | Length (Simplebim) (mm) | Splitting
4935767 | 1328.81 | 4733.68 | ORIGINAL
4935825 | 1334.78 | 4755.3 | ORIGINAL
4936040 | 4088.87 | 4866.17 | ORIGINAL
4936359 | 3444.21 | 4097.89 | ORIGINAL
5003254 | 25 | 2037.37 | ORIGINAL
5003262 | 25 | 1244.1 | ORIGINAL
5003266 | 25 | 922.184 | ORIGINAL
5003278 | 25 | 918.797 | ORIGINAL
5003288 | 75.6626 | 1169.57 | ORIGINAL
5003290 | 75.7096 | 1170.65 | ORIGINAL
5003292 | 25 | 953.625 | ORIGINAL
5003294 | 397.218 | 1254.13 | ORIGINAL
5003296 | 25 | 973.157 | ORIGINAL
5003297 | 404.701 | 1279.13 | ORIGINAL
8617709 | 25 | 180.077 | ORIGINAL
8617736 | 25 | 180.077 | ORIGINAL
11382414 | 25 | 1480.16 | ORIGINAL
11382415 | 25 | 1494.8 | ORIGINAL
11383766 | 25 | 1189.1 | ORIGINAL
11383767 | 25 | 1214.1 | ORIGINAL
11383836 | 25 | 87.5118 | ORIGINAL
11383837 | 25 | 112.512 | ORIGINAL
11385658 | 25 | 3883.77 | ORIGINAL
11385659 | 25 | 3894.13 | ORIGINAL
13302147 | 2757.73 | 4192.45 | ORIGINAL
13302154 | 6631.9 | 8478.63 | ORIGINAL
13302160 | 5180.13 | 11622.9 | ORIGINAL
13339050 | 750.901 | 1175.73 | ORIGINAL
13339053 | 2738.21 | 4162.66 | ORIGINAL
16970410 | 25 | 1615.19 | ORIGINAL
16970421 | 25 | 425.26 | ORIGINAL
16970431 | 123.744 | 123.744 | ORIGINAL
16970434 | 123.744 | 123.744 | ORIGINAL
16970456 | 25 | 1625.55 | ORIGINAL
16970466 | 25 | 404.549 | ORIGINAL
16970476 | 123.744 | 123.744 | ORIGINAL
16970479 | 123.744 | 123.744 | ORIGINAL
4936360 | 25 | 831 | RESULT
11382660 | 25 | 824 | RESULT
11382661 | 25 | 849 | RESULT

# IfcFlowSegment: Pipe Types:Kobberrør (34)
ePset_Simplebim - Assembly Level: Leaf
AVINOR - 08_Status: S4; 07_Fase: F90
Name (Pipe Types:Kobberrør:...) | In | Splitting | 05_ID-nummer | Width (Simplebim) (mm) | Height (Simplebim) (mm) | Length (Simplebim) (mm)
18597003 | Nivå F | ORIGINAL | +BR003=310.TO100-KR001T | 18 | 18 | 462.695 | Group: 310.TO100 78
18815514 | Nivå F | ORIGINAL | +BR003=310.TO200-KR003T | 28 | 28 | 1259.71
18815516 | Nivå F | ORIGINAL | +BR003=310.TO100-KR001T | 35 | 35 | 1398.71
18815718 | Nivå F | ORIGINAL | +BR003=310.TO200-KR003T | 28 | 28 | 2366
18815720 | Nivå F | ORIGINAL | +BR003=310.TO100-KR001T | 35 | 35 | 2498
18815750 | Nivå F | ORIGINAL | +BR003=310.TO200-KR003T | 28 | 28 | 144
18815784 | Nivå F | ORIGINAL | +BR003=310.TO100-KR001T | 35 | 35 | 130
18816047 | Nivå F | ORIGINAL | +BR003=310.TO200-KR003T | 28 | 28 | 364
18816049 | Nivå F | ORIGINAL | +BR003=310.TO100-KR001T | 35 | 35 | 450
18816281 | Nivå F | ORIGINAL | +BR003=310.TO200-KR003T | 28 | 28 | 878.978
18816283 | Nivå F | ORIGINAL | +BR003=310.TO100-KR001T | 35 | 35 | 714.978
18816344 | Nivå F | ORIGINAL | +BR003=310.TO100-KR001T | 35 | 35 | 280
18816378 | Nivå F | ORIGINAL | +BR003=310.TO200-KR003T | 28 | 28 | 294
18865181 | Nivå F | ORIGINAL | +BR003=310.TO100-KR001T | 28 | 28 | 14.4287
18865190 | Nivå F | ORIGINAL | +BR003=310.TO100-KR001T | 28 | 28 | 166.808
18865206 | Nivå F | ORIGINAL | +BR003=310.TO100-KR001T | 28 | 28 | 1652 | Group: 310.TO100 78
18865250 | Nivå F | ORIGINAL | +BR003=310.TO200-KR003T | 22 | 22 | 51.3799
18866133 | Nivå F | ORIGINAL | +BR003=310.TO200-KR003T | 22 | 22 | 328.808
18866135 | Nivå F | ORIGINAL | +BR003=310.TO200-KR003T | 22 | 22 | 1658 | Group: 310.TO200 1
18866151 | Nivå F | ORIGINAL | +BR003=310.TO200-KR003T | 28 | 28 | 407.539
18866162 | Nivå F | ORIGINAL | +BR003=310.TO100-KR001T | 35 | 35 | 1969.06
18870706 | Nivå F | ORIGINAL | +BR003=310.TO200-KR003T | 28 | 28 | 8686.86
18870750 | Nivå F | ORIGINAL | +BR003=310.TO100-KR001T | 35 | 35 | 8673.86
18870863 | Nivå F | ORIGINAL | +BR003=310.TO200-KR003T | 28 | 28 | 394
18870907 | Nivå F | ORIGINAL | +BR003=310.TO100-KR001T | 35 | 35 | 380
18870947 | Nivå F | ORIGINAL | +BR003=310.TO200-KR003T | 28 | 28 | 394
18870987 | Nivå F | ORIGINAL | +BR003=310.TO100-KR001T | 35 | 35 | 380
19689074 | Nivå F | ORIGINAL | +BR003=310.TO200-KR003T | 28 | 28 | 2342.6
19689364 | Nivå B | ORIGINAL | +BR003=310.TO100-KR001T | 98.8564 | 98.8564 | 28
19689590 | Nivå B | ORIGINAL | +BR003=310.TO100-KR001T | 28 | 28 | 105.885
19689638 | Nivå F | ORIGINAL | +BR003=310.TO100-KR001T | 28 | 88.4958 | 88.4958
19689645 | Nivå F | ORIGINAL | +BR003=310.TO100-KR001T | 35 | 35 | 481.032
19689008 | Nivå F | RESULT | +BR003=310.TO100-KR001T | 28 | 28 | 2157
19689059 | Nivå F | RESULT | +BR003=310.TO200-KR003T | 22 | 22 | 2318

# IfcFlowSegment: Pipe Types:MA (12)
ePset_Simplebim - Assembly Level: Leaf
AVINOR - 08_Status: S4; 07_Fase: F90
ePset_LocationTool - Splitting: ORIGINAL
Name (Pipe Types:MA:...) | In | 05_ID-nummer | Length (Simplebim) (mm) | Width (Simplebim) (mm) | Height (Simplebim) (mm) | Group
14659186 | Nivå F | +BR003=310.TO500-KR006T | 1447.1 | 135 | 135 | 310.TO500 1 (2)
14659313 | Nivå E | +BR003=310.TO500-KR006T | 1182.96 | 135 | 135
14659497 | Nivå E | +BR003=310.SB801-KR007T | 265.481 | 135 | 265.481 | AVINOR - 01_Lufthavnkode: ENBR
14659541 | Nivå F | +BR003=310.SB801-KR007T | 1467.91 | 135 | 135 | 310.SB801 (1) | AVINOR - 01_Lufthavnkode: ENBR
14659671 | Nivå E | +BR003=310.SB801-KR007T | 759.081 | 135 | 135 | AVINOR - 01_Lufthavnkode: ENBR
18596079 | Nivå E | +BR003=310.TO500-KR006T | 1231.25 | 75 | 75 | 310.TO500 1 (2)
18596444 | Nivå E | +BR003=310.TO500-KR006T | 1536.25 | 75 | 75 | 310.TO500 1 (2)
18872565 | Nivå E | +BR003=310.TO500-KR006T | 1618.13 | 75 | 75 | 310.TO500 1 (2)
18873046 | Nivå E | +BR003=310.TO500-KR006T | 144.471 | 75 | 144.471
18873390 | Nivå E | +BR003=310.TO500-KR006T | 5215.69 | 75 | 161.88
19021846 | Nivå E | +BR003=310.TO500-KR006T | 1027.05 | 110 | 110 | 310.TO500 1 (2)
19022485 | Nivå E | +BR003=310.TO500-KR006T | 1476.28 | 110 | 110 | 310.TO500 1 (2)

# IfcFlowSegment: Pipe Types:PEX rør (4)
In: Nivå F
ePset_Simplebim - Assembly Level: Leaf
ePset_LocationTool - Splitting: ORIGINAL
AVINOR - 08_Status: S4; 05_ID-nummer: +BR003=310.TO100-KR015T; 07_Fase: F90
Name (Pipe Types:PEX rør:...) | Width (Simplebim) (mm) | Height (Simplebim) (mm) | Length (Simplebim) (mm)
20251138 | 22 | 22 | 52.6001
20251185 | 2559.64 | 22 | 4593.67
20251201 | 22 | 22 | 760 | Group: 310.TO100 78
20251403 | 18 | 18 | 640 | Group: 310.TO100 78

# IfcFlowSegment: Pipe Types:Rustfrie stålrør (19)
ePset_Simplebim - Assembly Level: Leaf
AVINOR - 08_Status: S4; 07_Fase: F90; 05_ID-nummer: +BR003=310.TO601-KR009T
ePset_LocationTool - Splitting: ORIGINAL
Name (Pipe Types:Rustfrie stålrør:...) | In | Length (Simplebim) (mm) | Height (Simplebim) (mm) | Width (Simplebim) (mm)
14659840 | Nivå F | 306.605 | 125 | 125
14659848 | Nivå F | 196.44 | 196.44 | 125
14659858 | Nivå F | 122.725 | 160 | 160
14659954 | Nivå F | 102.074 | 125 | 125
14659995 | Nivå F | 179.103 | 179.103 | 125
14660011 | Nivå F | 238.777 | 125.681 | 125
14660150 | Nivå F | 1873.73 | 160 | 160
14660180 | Nivå E | 698.807 | 160 | 160
14660379 | Nivå E | 328.39 | 328.39 | 160
15668307 | Nivå F | 195.324 | 195.324 | 125.001
15668327 | Nivå F | 219.698 | 125 | 125 | Group: 310.TO601
15668407 | Nivå F | 190.462 | 190.462 | 125
15668424 | Nivå F | 205.152 | 125 | 125 | Group: 310.TO601
15668590 | Nivå F | 254.993 | 160 | 160
15668809 | Nivå F | 198.146 | 198.146 | 160
18852269 | Nivå E | 3373.3 | 125 | 125
18852277 | Nivå E | 1062.29 | 125 | 125
18852353 | Nivå F | 203.004 | 125.024 | 203.004
18852365 | Nivå F | 533.835 | 125.029 | 125

# IfcFlowSegment: Pipe Types:Stålrør normaltykke (171)
ePset_Simplebim - Assembly Level: Leaf
Name (Pipe Types:Stålrør normaltykke:...) | In | Splitting | Length (Simplebim) (mm) | Width (Simplebim) (mm) | Height (Simplebim) (mm) | 05_ID-nummer | 08_Status | 07_Fase
23486729 | Nivå F | ORIGINAL | 80 | 17.2 | 17.2 | +BR003=370.PB102-KR001T | S4 | F90 | Group: K 390
23486732 | Nivå F | ORIGINAL | 80 | 17.2 | 17.2 | +BR003=370.PB102-KR001T | S4 | F90 | Group: K 391
23486788 | Nivå F | ORIGINAL | 80 | 17.2 | 17.2 | +BR003=370.PB102-KR001T | S4 | F90 | Group: K 392
23486791 | Nivå F | ORIGINAL | 80 | 17.2 | 17.2 | +BR003=370.PB102-KR001T | S4 | F90 | Group: K 393
8932244 | Nivå E | ORIGINAL | 57.748 | 33.7 | 33.7 | +BR003=332.PB001-KR001T | S4 | F90
8932247 | Nivå E | ORIGINAL | 497.683 | 60.3 | 60.3 | +BR003=332.PB001-KR001T | S4 | F90
8932250 | Nivå E | ORIGINAL | 57.748 | 33.7 | 33.7 | +BR003=332.PB001-KR001T | S4 | F90
8932253 | Nivå E | ORIGINAL | 1979.17 | 60.3 | 60.3 | +BR003=332.PB001-KR001T | S4 | F90
8932356 | Nivå E | ORIGINAL | 57.748 | 33.7 | 33.7 | +BR003=332.PB001-KR001T | S4 | F90
8932359 | Nivå E | ORIGINAL | 497.683 | 60.3 | 60.3 | +BR003=332.PB001-KR001T | S4 | F90
8932362 | Nivå E | ORIGINAL | 57.748 | 33.7 | 33.7 | +BR003=332.PB001-KR001T | S4 | F90
8932365 | Nivå E | ORIGINAL | 1219.6 | 60.3 | 60.3 | +BR003=332.PB001-KR001T | S4 | F90
8932468 | Nivå E | ORIGINAL | 57.748 | 33.7 | 33.7 | +BR003=332.PB001-KR001T | S4 | F90
8932471 | Nivå E | ORIGINAL | 497.683 | 60.3 | 60.3 | +BR003=332.PB001-KR001T | S4 | F90
8932474 | Nivå E | ORIGINAL | 57.748 | 33.7 | 33.7 | +BR003=332.PB001-KR001T | S4 | F90
8932477 | Nivå E | ORIGINAL | 2592.4 | 60.3 | 60.3 | +BR003=332.PB001-KR001T | S4 | F90
8932999 | Nivå E | ORIGINAL | 57.748 | 33.7 | 33.7 | +BR003=332.PB001-KR001T | S4 | F90
8933002 | Nivå E | ORIGINAL | 497.683 | 60.3 | 60.3 | +BR003=332.PB001-KR001T | S4 | F90
8933005 | Nivå E | ORIGINAL | 57.748 | 33.7 | 33.7 | +BR003=332.PB001-KR001T | S4 | F90
8933008 | Nivå E | ORIGINAL | 3502.4 | 60.3 | 60.3 | +BR003=332.PB001-KR001T | S4 | F90
8933011 | Nivå E | ORIGINAL | 57.748 | 33.7 | 33.7 | +BR003=332.PB001-KR001T | S4 | F90
8933014 | Nivå E | ORIGINAL | 3572.4 | 60.3 | 60.3 | +BR003=332.PB001-KR001T | S4 | F90
8933087 | Nivå E | ORIGINAL | 57.748 | 33.7 | 33.7 | +BR003=332.PB001-KR001T | S4 | F90
8933090 | Nivå E | ORIGINAL | 497.683 | 60.3 | 60.3 | +BR003=332.PB001-KR001T | S4 | F90
8933093 | Nivå E | ORIGINAL | 57.748 | 33.7 | 33.7 | +BR003=332.PB001-KR001T | S4 | F90
8933096 | Nivå E | ORIGINAL | 3502.4 | 60.3 | 60.3 | +BR003=332.PB001-KR001T | S4 | F90
8933099 | Nivå E | ORIGINAL | 57.748 | 33.7 | 33.7 | +BR003=332.PB001-KR001T | S4 | F90
8933102 | Nivå E | ORIGINAL | 3572.4 | 60.3 | 60.3 | +BR003=332.PB001-KR001T | S4 | F90
8933175 | Nivå E | ORIGINAL | 57.748 | 33.7 | 33.7 | +BR003=332.PB001-KR001T | S4 | F90
8933178 | Nivå E | ORIGINAL | 497.683 | 60.3 | 60.3 | +BR003=332.PB001-KR001T | S4 | F90
8933181 | Nivå E | ORIGINAL | 57.748 | 33.7 | 33.7 | +BR003=332.PB001-KR001T | S4 | F90
8933184 | Nivå E | ORIGINAL | 3502.4 | 60.3 | 60.3 | +BR003=332.PB001-KR001T | S4 | F90
8933187 | Nivå E | ORIGINAL | 57.748 | 33.7 | 33.7 | +BR003=332.PB001-KR001T | S4 | F90
8933190 | Nivå E | ORIGINAL | 3572.4 | 60.3 | 60.3 | +BR003=332.PB001-KR001T | S4 | F90
8933304 | Nivå E | ORIGINAL | 57.748 | 33.7 | 33.7 | +BR003=332.PB001-KR001T | S4 | F90
8933307 | Nivå E | ORIGINAL | 497.683 | 60.3 | 60.3 | +BR003=332.PB001-KR001T | S4 | F90
8933310 | Nivå E | ORIGINAL | 57.748 | 33.7 | 33.7 | +BR003=332.PB001-KR001T | S4 | F90
8933313 | Nivå E | ORIGINAL | 3502.4 | 60.3 | 60.3 | +BR003=332.PB001-KR001T | S4 | F90
8933316 | Nivå E | ORIGINAL | 57.748 | 33.7 | 33.7 | +BR003=332.PB001-KR001T | S4 | F90
8933319 | Nivå E | ORIGINAL | 3572.4 | 60.3 | 60.3 | +BR003=332.PB001-KR001T | S4 | F90
8933392 | Nivå E | ORIGINAL | 57.748 | 33.7 | 33.7 | +BR003=332.PB001-KR001T | S4 | F90
8933395 | Nivå E | ORIGINAL | 497.683 | 60.3 | 60.3 | +BR003=332.PB001-KR001T | S4 | F90
8933398 | Nivå E | ORIGINAL | 57.748 | 33.7 | 33.7 | +BR003=332.PB001-KR001T | S4 | F90
8933401 | Nivå E | ORIGINAL | 3502.4 | 60.3 | 60.3 | +BR003=332.PB001-KR001T | S4 | F90
8933404 | Nivå E | ORIGINAL | 57.748 | 33.7 | 33.7 | +BR003=332.PB001-KR001T | S4 | F90
8933407 | Nivå E | ORIGINAL | 3572.4 | 60.3 | 60.3 | +BR003=332.PB001-KR001T | S4 | F90
8933480 | Nivå E | ORIGINAL | 57.748 | 33.7 | 33.7 | +BR003=332.PB001-KR001T | S4 | F90
8933483 | Nivå E | ORIGINAL | 497.683 | 60.3 | 60.3 | +BR003=332.PB001-KR001T | S4 | F90
8933486 | Nivå E | ORIGINAL | 57.748 | 33.7 | 33.7 | +BR003=332.PB001-KR001T | S4 | F90
8933489 | Nivå E | ORIGINAL | 3502.4 | 60.3 | 60.3 | +BR003=332.PB001-KR001T | S4 | F90
8933492 | Nivå E | ORIGINAL | 57.748 | 33.7 | 33.7 | +BR003=332.PB001-KR001T | S4 | F90
8977928 | Nivå E | ORIGINAL | 108.794 | 60.3 | 60.3 | +BR003=332.PB001-KR001T | S4 | F90
8978600 | Nivå E | ORIGINAL | 55.9059 | 60.3 | 60.3 | +BR003=332.PB001-KR001T | S4 | F90
8978709 | Nivå E | ORIGINAL | 331.535 | 76.1 | 76.1 | +BR003=332.PB001-KR001T | S4 | F90
8978796 | Nivå E | ORIGINAL | 247.6 | 76.1 | 76.1 | +BR003=332.PB001-KR001T | S4 | F90
8978848 | Nivå E | ORIGINAL | 247.6 | 76.1 | 76.1 | +BR003=332.PB001-KR001T | S4 | F90
8979114 | Nivå E | ORIGINAL | 59.1559 | 60.3 | 60.3 | +BR003=332.PB001-KR001T | S4 | F90
8979127 | Nivå E | ORIGINAL | 1276.42 | 60.3 | 60.3 | +BR003=332.PB001-KR001T | S4 | F90
10504172 | Nivå F | ORIGINAL | 258.255 | 33.7 | 33.7 | +BR003=332.PB001-KR001T | S4 | F90 | Group: 332.PB001 11
10504223 | Nivå F | ORIGINAL | 215.943 | 33.7 | 33.7 | +BR003=332.PB001-KR001T | S4 | F90 | Group: 332.PB001 11
10504239 | Nivå F | ORIGINAL | 206.2 | 33.7 | 33.7 | +BR003=332.PB001-KR001T | S4 | F90 | Group: 332.PB001 11
10504259 | Nivå F | ORIGINAL | 576.152 | 33.7 | 33.7 | +BR003=332.PB001-KR001T | S4 | F90 | Group: 332.PB001 11
10504277 | Nivå F | ORIGINAL | 576.152 | 33.7 | 33.7 | +BR003=332.PB001-KR001T | S4 | F90 | Group: 332.PB001 11
10504295 | Nivå F | ORIGINAL | 189.982 | 33.7 | 33.7 | +BR003=332.PB001-KR001T | S4 | F90 | Group: 332.PB001 11
10504313 | Nivå F | ORIGINAL | 576.152 | 33.7 | 33.7 | +BR003=332.PB001-KR001T | S4 | F90 | Group: 332.PB001 11
10504366 | Nivå F | ORIGINAL | 713.152 | 33.7 | 33.7 | +BR003=332.PB001-KR001T | S4 | F90
10504402 | Nivå F | ORIGINAL | 719.602 | 33.7 | 33.7 | +BR003=332.PB001-KR001T | S4 | F90
10504475 | Nivå F | ORIGINAL | 576.152 | 33.7 | 33.7 | +BR003=332.PB001-KR001T | S4 | F90 | Group: 332.PB001 11
10504493 | Nivå F | ORIGINAL | 576.152 | 33.7 | 33.7 | +BR003=332.PB001-KR001T | S4 | F90 | Group: 332.PB001 11
10504511 | Nivå F | ORIGINAL | 576.152 | 33.7 | 33.7 | +BR003=332.PB001-KR001T | S4 | F90 | Group: 332.PB001 11
10504529 | Nivå F | ORIGINAL | 576.152 | 33.7 | 33.7 | +BR003=332.PB001-KR001T | S4 | F90 | Group: 332.PB001 11
10505340 | Nivå F | ORIGINAL | 872.614 | 114.3 | 114.3 | +BR003=332.PB001-KR001T | S4 | F90
10505400 | Nivå F | ORIGINAL | 421.2 | 114.3 | 114.3 | +BR003=332.PB001-KR001T | S4 | F90
10505819 | Nivå F | ORIGINAL | 395.386 | 114.3 | 114.3 | +BR003=332.PB001-KR001T | S4 | F90
10506450 | Nivå F | ORIGINAL | 160.296 | 33.7 | 33.7 | +BR003=332.PB001-KR001T | S4 | F90
10506694 | Nivå F | ORIGINAL | 167.05 | 76.1 | 76.1 | +BR003=332.PB001-KR001T | S4 | F90
10506697 | Nivå F | ORIGINAL | 1777.1 | 114.3 | 114.3 | +BR003=332.PB001-KR001T | S4 | F90
10507212 | Nivå F | ORIGINAL | 2032.4 | 114.3 | 114.3 | +BR003=332.PB001-KR001T | S4 | F90
10507224 | Nivå F | ORIGINAL | 1518.63 | 114.3 | 114.3 | +BR003=332.PB001-KR001T | S4 | F90
10507714 | Nivå F | ORIGINAL | 380.4 | 33.7 | 33.7 | +BR003=332.PB001-KR001T | S4 | F90
10507717 | Nivå F | ORIGINAL | 1807.08 | 114.3 | 114.3 | +BR003=332.PB001-KR001T | S4 | F90
10511384 | Nivå F | ORIGINAL | 219.45 | 33.7 | 33.7 | +BR003=332.PB001-KR001T | S4 | F90
10511387 | Nivå F | ORIGINAL | 278.921 | 88.9 | 88.9 | +BR003=332.PB001-KR001T | S4 | F90
10511496 | Nivå F | ORIGINAL | 2635.6 | 114.3 | 114.3 | +BR003=332.PB001-KR001T | S4 | F90
10511620 | Nivå F | ORIGINAL | 129.634 | 114.3 | 114.3 | +BR003=332.PB001-KR001T | S4 | F90
10511649 | Nivå F | ORIGINAL | 356.7 | 356.7 | 114.3 | +BR003=332.PB001-KR001T | S4 | F90
11540989 | Nivå E | ORIGINAL | 563.212 | 33.7 | 33.7 | +BR003=332.PB001-KR001T | S4 | F90
11541006 | Nivå E | ORIGINAL | 1159.38 | 60.3 | 60.3 | +BR003=332.PB001-KR001T | S4 | F90
11541049 | Nivå E | ORIGINAL | 60.248 | 33.7 | 33.7 | +BR003=332.PB001-KR001T | S4 | F90 | Group: 332.PB001 01 (1)
11541391 | Nivå E | ORIGINAL | 2186.93 | 33.7 | 33.7 | +BR003=332.PB001-KR001T | S4 | F90
11541400 | Nivå E | ORIGINAL | 33.7 | 33.7 | 32.4 | +BR003=332.PB001-KR001T | S4 | F90
11541601 | Nivå E | ORIGINAL | 60.248 | 33.7 | 33.7 | +BR003=332.PB001-KR001T | S4 | F90 | Group: 332.PB001 01 (1)
11541913 | Nivå E | ORIGINAL | 550.684 | 33.7 | 33.7 | +BR003=332.PB001-KR001T | S4 | F90
11541926 | Nivå E | ORIGINAL | 519.377 | 76.1 | 76.1 | +BR003=332.PB001-KR001T | S4 | F90
11541967 | Nivå E | ORIGINAL | 2187.61 | 33.7 | 33.7 | +BR003=332.PB001-KR001T | S4 | F90
11541978 | Nivå E | ORIGINAL | 33.7 | 33.7 | 32.4 | +BR003=332.PB001-KR001T | S4 | F90
12558331 | Nivå E | ORIGINAL | 60.248 | 33.7 | 33.7 | +BR003=332.PB001-KR001T | S4 | F90 | Group: 332.PB001 01 (1)
12558334 | Nivå E | ORIGINAL | 60.248 | 33.7 | 33.7 | +BR003=332.PB001-KR001T | S4 | F90 | Group: 332.PB001 01 (1)
12558338 | Nivå E | ORIGINAL | 57.748 | 33.7 | 33.7 | +BR003=332.PB001-KR001T | S4 | F90
12558739 | Nivå E | ORIGINAL | 1082.48 | 33.7 | 33.7 | +BR003=332.PB001-KR001T | S4 | F90
12558749 | Nivå E | ORIGINAL | 2167.59 | 33.7 | 33.7 | +BR003=332.PB001-KR001T | S4 | F90
12558762 | Nivå E | ORIGINAL | 512.4 | 33.7 | 33.7 | +BR003=332.PB001-KR001T | S4 | F90
12558787 | Nivå E | ORIGINAL | 33.7 | 33.7 | 32.4 | +BR003=332.PB001-KR001T | S4 | F90
12558798 | Nivå E | ORIGINAL | 894.033 | 33.7 | 33.7 | +BR003=332.PB001-KR001T | S4 | F90
12558813 | Nivå E | ORIGINAL | 163.206 | 60.3 | 60.3 | +BR003=332.PB001-KR001T | S4 | F90
16321900 | Nivå E | ORIGINAL | 3572.4 | 60.3 | 60.3 | +BR003=332.PB001-KR001T | S4 | F90
16337146 | Nivå E | ORIGINAL | 27.541 | 33.7 | 33.7 | +BR003=332.PB001-KR001T | S4 | F90
16337172 | Nivå E | ORIGINAL | 545.633 | 60.3 | 60.3 | +BR003=332.PB001-KR001T | S4 | F90
16338767 | Nivå E | ORIGINAL | 1252 | 60.3 | 60.3 | +BR003=332.PB001-KR001T | S4 | F90
16338864 | Nivå E | ORIGINAL | 239.2 | 60.3 | 60.3 | +BR003=332.PB001-KR001T | S4 | F90
16355332 | Nivå E | ORIGINAL | 1125.53 | 33.7 | 33.7 | +BR003=332.PB001-KR001T | S4 | F90
16355520 | Nivå E | ORIGINAL | 27.541 | 33.7 | 33.7 | +BR003=332.PB001-KR001T | S4 | F90
17418001 | Nivå F | ORIGINAL | 371.019 | 33.7 | 33.7 | +BR003=332.PB001-KR001T | S4 | F90
17418141 | Nivå F | ORIGINAL | 300.4 | 33.7 | 33.7 | +BR003=332.PB001-KR001T | S4 | F90
17418379 | Nivå F | ORIGINAL | 1415.03 | 114.3 | 114.3 | +BR003=332.PB001-KR001T | S4 | F90
17418428 | Nivå F | ORIGINAL | 143.808 | 114.3 | 143.808 | +BR003=332.PB001-KR001T | S4 | F90
18238266 | Nivå E | ORIGINAL | 268.283 | 60.3 | 60.3 | +BR003=332.PB001-KR001T | S4 | F90
18238278 | Nivå E | ORIGINAL | 209.2 | 60.3 | 60.3 | +BR003=332.PB001-KR001T | S4 | F90
18238372 | Nivå E | ORIGINAL | 268.283 | 60.3 | 60.3 | +BR003=332.PB001-KR001T | S4 | F90
18238384 | Nivå E | ORIGINAL | 209.2 | 60.3 | 60.3 | +BR003=332.PB001-KR001T | S4 | F90
18238838 | Nivå E | ORIGINAL | 265.619 | 60.3 | 60.3 | +BR003=332.PB001-KR001T | S4 | F90
19171810 | Nivå F | ORIGINAL | 492.4 | 42.4 | 42.4 | +BR003=332.PB001-KR001T | S4 | F90
19171813 | Nivå F | ORIGINAL | 264.418 | 114.3 | 114.3 | +BR003=332.PB001-KR001T | S4 | F90
19474137 | Nivå F | ORIGINAL | 185.943 | 33.7 | 33.7 | +BR003=332.PB001-KR001T | S4 | F90 | Group: 332.PB001 11
19474199 | Nivå F | ORIGINAL | 827.028 | 33.7 | 33.7 | +BR003=332.PB001-KR001T | S4 | F90 | Group: 332.PB001 11
19474202 | Nivå F | ORIGINAL | 445.372 | 33.7 | 33.7 | +BR003=332.PB001-KR001T | S4 | F90
19474205 | Nivå F | ORIGINAL | 921.542 | 33.7 | 33.7 | +BR003=332.PB001-KR001T | S4 | F90
19474288 | Nivå F | ORIGINAL | 345.905 | 33.7 | 33.7 | +BR003=332.PB001-KR001T | S4 | F90 | Group: 332.PB001 11
19474469 | Nivå F | ORIGINAL | 743.152 | 33.7 | 33.7 | +BR003=332.PB001-KR001T | S4 | F90 | Group: 332.PB001 11
19526418 | Nivå F | ORIGINAL | 576.152 | 33.7 | 33.7 | +BR003=332.PB001-KR001T | S4 | F90 | Group: 332.PB001 11
19527913 | Nivå F | ORIGINAL | 187.032 | 33.7 | 33.7 | +BR003=332.PB001-KR001T | S4 | F90 | Group: 332.PB001 11
19527921 | Nivå F | ORIGINAL | 576.152 | 33.7 | 33.7 | +BR003=332.PB001-KR001T | S4 | F90 | Group: 332.PB001 11
19528041 | Nivå F | ORIGINAL | 132.4 | 33.7 | 33.7 | +BR003=332.PB001-KR001T | S4 | F90
19532219 | Nivå F | ORIGINAL | 321.52 | 33.7 | 33.7 | +BR003=332.PB001-KR001T | S4 | F90
19532936 | Nivå F | ORIGINAL | 318.57 | 33.7 | 33.7 | +BR003=332.PB001-KR001T | S4 | F90
19533170 | Nivå F | ORIGINAL | 57.0636 | 114.3 | 114.3 | +BR003=332.PB001-KR001T | S4 | F90
19533266 | Nivå F | ORIGINAL | 411.2 | 114.3 | 114.3 | +BR003=332.PB001-KR001T | S4 | F90
19533454 | Nivå F | ORIGINAL | 271 | 76.1 | 76.1 | +BR003=332.PB001-KR001T | S4 | F90
19533457 | Nivå F | ORIGINAL | 2597.63 | 114.3 | 114.3 | +BR003=332.PB001-KR001T | S4 | F90
19533511 | Nivå F | ORIGINAL | 632.548 | 33.7 | 33.7 | +BR003=332.PB001-KR001T | S4 | F90
19533622 | Nivå F | ORIGINAL | 329.352 | 33.7 | 33.7 | +BR003=332.PB001-KR001T | S4 | F90
19533646 | Nivå F | ORIGINAL | 345.905 | 33.7 | 33.7 | +BR003=332.PB001-KR001T | S4 | F90 | Group: 332.PB001 11
19533654 | Nivå F | ORIGINAL | 612.4 | 33.7 | 33.7 | +BR003=332.PB001-KR001T | S4 | F90
19533822 | Nivå F | ORIGINAL | 662.647 | 33.7 | 33.7 | +BR003=332.PB001-KR001T | S4 | F90
19533831 | Nivå F | ORIGINAL | 171.2 | 33.7 | 33.7 | +BR003=332.PB001-KR001T | S4 | F90
19533885 | Nivå F | ORIGINAL | 619.485 | 33.7 | 33.7 | +BR003=332.PB001-KR001T | S4 | F90
19533893 | Nivå F | ORIGINAL | 558.747 | 33.7 | 33.7 | +BR003=332.PB001-KR001T | S4 | F90
19534249 | Nivå F | ORIGINAL | 517.981 | 33.7 | 33.7 | +BR003=332.PB001-KR001T | S4 | F90
19534341 | Nivå F | ORIGINAL | 33.7 | 32.3185 | 22.2773 | +BR003=332.PB001-KR001T | S4 | F90
19534395 | Nivå F | ORIGINAL | 483.115 | 33.7 | 33.7 | +BR003=332.PB001-KR001T | S4 | F90
19534429 | Nivå F | ORIGINAL | 35.1284 | 33.7 | 27.1441 | +BR003=332.PB001-KR001T | S4 | F90
19534586 | Nivå F | ORIGINAL | 469.352 | 33.7 | 33.7 | +BR003=332.PB001-KR001T | S4 | F90
19534615 | Nivå F | ORIGINAL | 157.128 | 33.7 | 33.7 | +BR003=332.PB001-KR001T | S4 | F90
19536866 | Nivå F | ORIGINAL | 545.929 | 42.4 | 42.4 | +BR003=332.PB001-KR001T | S4 | F90
19536880 | Nivå F | ORIGINAL | 716.051 | 42.4 | 42.4 | +BR003=332.PB001-KR001T | S4 | F90
19536929 | Nivå F | ORIGINAL | 1397.87 | 114.3 | 114.3 | +BR003=332.PB001-KR001T | S4 | F90
19540339 | Nivå F | ORIGINAL | 238.524 | 33.7 | 33.7 | +BR003=332.PB001-KR001T | S4 | F90
19552283 | Nivå F | ORIGINAL | 266.2 | 33.7 | 33.7 | +BR003=332.PB001-KR001T | S4 | F90 | Group: 332.PB001 11
19552313 | Nivå F | ORIGINAL | 134.9 | 33.7 | 33.7 | +BR003=332.PB001-KR001T | S4 | F90
19552325 | Nivå F | ORIGINAL | 259.352 | 33.7 | 33.7 | +BR003=332.PB001-KR001T | S4 | F90
20618740 | Nivå F | ORIGINAL | 52.4 | 33.7 | 33.7
20618754 | Nivå F | ORIGINAL | 108.186 | 33.7 | 33.7
18238444 | Nivå E | RESULT | 170 | 41 | 60 | +BR003=332.PB001-KR001T | S4 | F90
8933196 | Nivå E | RESULT | 533 | 61 | 60 | +BR003=332.PB001-KR001T | S4 | F90
8933020 | Nivå E | RESULT | 533 | 61 | 60 | +BR003=332.PB001-KR001T | S4 | F90
8933108 | Nivå E | RESULT | 533 | 61 | 60 | +BR003=332.PB001-KR001T | S4 | F90
11850080 | Nivå E | RESULT | 4890 | 76 | 76 | +BR003=332.PB001-KR001T | S4 | F90
10511767 | Nivå E | RESULT | 980 | 114 | 114 | +BR003=332.PB001-KR001T | S4 | F90
12558557 | Nivå E | RESULT | 1950 | 34 | 34 | +BR003=332.PB001-KR001T | S4 | F90
10507813 | Nivå F | RESULT | 828 | 88 | 88 | +BR003=332.PB001-KR001T | S4 | F90
8933448 | Nivå E | RESULT | 277 | 41 | 234 | +BR003=332.PB001-KR001T | S4 | F90

# IfcFlowSegment: Pipe Types:Stålrør syrefast AISI 316 (79)
ePset_Simplebim - Assembly Level: Leaf
AVINOR - 08_Status: S4; 07_Fase: F90
Name (Pipe Types:Stålrør syrefast AISI 316:...) | In | Height (Simplebim) (mm) | Width (Simplebim) (mm) | Length (Simplebim) (mm) | 05_ID-nummer | Splitting
12025468 | Nivå E | 48.3 | 48.3 | 1071.6 | +BR003=370.PB102-KR001T | ORIGINAL
12025662 | Nivå F | 48.3 | 48.3 | 2791.6 | +BR003=370.PB102-KR001T | ORIGINAL
12025720 | Nivå E | 48.3 | 48.3 | 1091.6 | +BR003=370.PB102-KR001T | ORIGINAL
12025867 | Nivå F | 48.3 | 48.3 | 2811.6 | +BR003=370.PB102-KR001T | ORIGINAL
12025876 | Nivå F | 48.3 | 48.3 | 24.9521 | +BR003=370.PB102-KR001T | ORIGINAL
12025919 | Nivå F | 48.3 | 48.3 | 24.9521 | +BR003=370.PB102-KR001T | ORIGINAL
12026078 | Nivå F | 48.3 | 48.3 | 197.047 | +BR003=370.PB102-KR001T | ORIGINAL | Group: 370.PB102 R
12026157 | Nivå F | 48.3 | 48.3 | 140 | +BR003=370.PB102-KR001T | ORIGINAL | Group: 370.PB102 T
18572914 | Nivå F | 48.3 | 48.3 | 206.547 | +BR003=370.PB102-KR001T | ORIGINAL
18572931 | Nivå F | 48.3 | 48.3 | 220 | +BR003=370.PB102-KR001T | ORIGINAL
20415217 | Nivå F | 48.3 | 48.3 | 180 | +BR003=370.PB102-KR001T | ORIGINAL | Group: 370.PB102 R
20415236 | Nivå F | 48.3 | 48.3 | 286.5 | +BR003=370.PB102-KR001T | ORIGINAL | Group: 370.PB102 T
20415266 | Nivå F | 48.3 | 48.3 | 434.039 | +BR003=370.PB102-KR001T | ORIGINAL
20415268 | Nivå F | 48.3 | 48.3 | 634.039 | +BR003=370.PB102-KR001T | ORIGINAL
20415320 | Nivå F | 105.801 | 48.3 | 105.801 | +BR003=370.PB102-KR001T | ORIGINAL
20415526 | Nivå F | 105.801 | 48.3 | 105.801 | +BR003=370.PB102-KR001T | ORIGINAL
20416532 | Nivå F | 48.3 | 145.801 | 145.801 | +BR003=370.PB102-KR001T | ORIGINAL
20416734 | Nivå F | 48.3 | 95.8012 | 95.8012 | +BR003=370.PB102-KR001T | ORIGINAL
20417661 | Nivå F | 26.7 | 26.7 | 66.4 | +BR003=370.PB102-KR001T | ORIGINAL
20417666 | Nivå F | 48.3 | 48.3 | 3863.38 | +BR003=370.PB102-KR001T | ORIGINAL
20417964 | Nivå F | 48.3 | 48.3 | 4153.38 | +BR003=370.PB102-KR001T | ORIGINAL
20418610 | Nivå F | 26.7 | 26.7 | 376.4 | +BR003=370.PB102-KR001T | ORIGINAL
20418620 | Nivå F | 26.7 | 26.7 | 101.112 | +BR003=370.PB102-KR001T | ORIGINAL | Group: 370.PB102 T
20445077 | Nivå F | 48.3 | 48.3 | 4675.4 | +BR003=370.PB102-KR001T | ORIGINAL
20445106 | Nivå F | 48.3 | 48.3 | 5089.83 | +BR003=370.PB102-KR001T | ORIGINAL
20445395 | Nivå F | 48.3 | 48.3 | 923.2 | +BR003=370.PB102-KR001T | ORIGINAL
20445442 | Nivå F | 48.3 | 48.3 | 903.2 | +BR003=370.PB102-KR001T | ORIGINAL
20446331 | Nivå F | 48.3 | 48.3 | 2737.46 | +BR003=370.PB102-KR001T | ORIGINAL
20446351 | Nivå F | 48.3 | 48.3 | 2966.34 | +BR003=370.PB102-KR001T | ORIGINAL
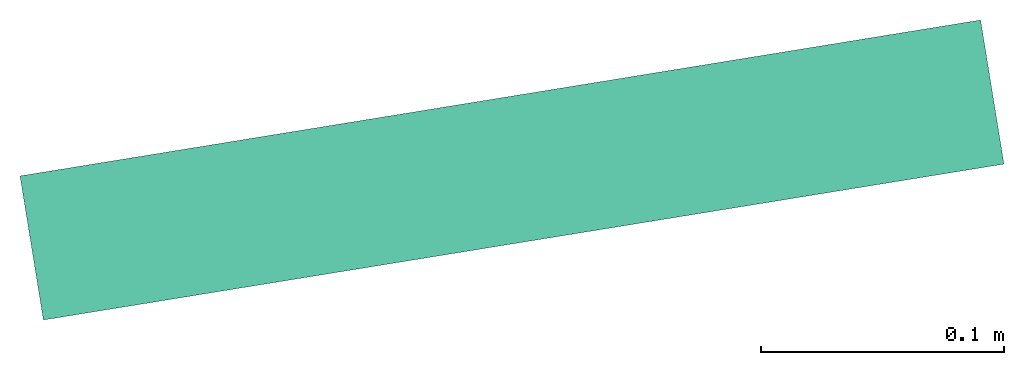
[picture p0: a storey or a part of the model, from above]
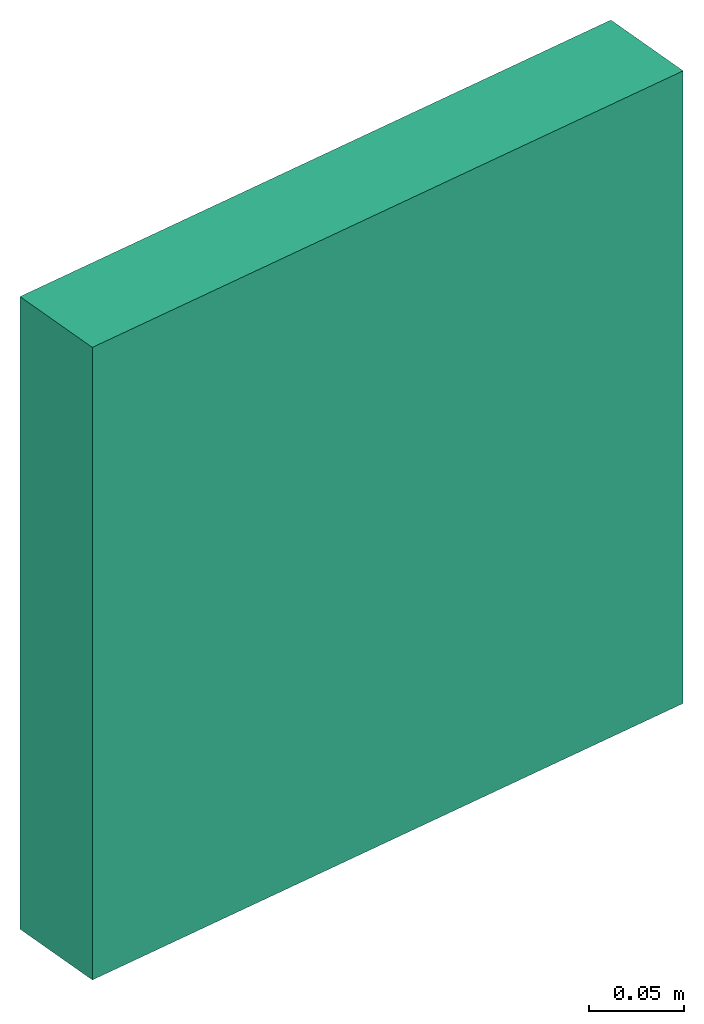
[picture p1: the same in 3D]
Properties of the parts of a building model (IFC2X3), part 3 of 4

# IfcFlowSegment: Pipe Types:Stålrør syrefast AISI 316 (79)
Name (Pipe Types:Stålrør syrefast AISI 316:...) | In | Height (Simplebim) (mm) | Width (Simplebim) (mm) | Length (Simplebim) (mm) | 05_ID-nummer | Splitting
20446388 | Nivå F | 48.3 | 48.3 | 63.2 | +BR003=370.PB102-KR001T | ORIGINAL
20446426 | Nivå F | 48.3 | 48.3 | 63.2 | +BR003=370.PB102-KR001T | ORIGINAL
20446464 | Nivå F | 48.3 | 48.3 | 103.2 | +BR003=370.PB102-KR001T | ORIGINAL
20446504 | Nivå F | 48.3 | 48.3 | 103.2 | +BR003=370.PB102-KR001T | ORIGINAL
20446573 | Nivå F | 48.3 | 48.3 | 316.142 | +BR003=370.PB102-KR001T | ORIGINAL
20446601 | Nivå F | 48.3 | 48.3 | 476.142 | +BR003=370.PB102-KR001T | ORIGINAL
20446704 | Nivå F | 48.3 | 48.3 | 1160.34 | +BR003=370.PB102-KR001T | ORIGINAL
20446705 | Nivå F | 85.8012 | 48.3 | 85.8012 | +BR003=370.PB102-KR001T | ORIGINAL
20446746 | Nivå F | 48.3 | 48.3 | 1150.34 | +BR003=370.PB102-KR001T | ORIGINAL
20446747 | Nivå F | 85.8012 | 48.3 | 85.8012 | +BR003=370.PB102-KR001T | ORIGINAL
20446819 | Nivå F | 26.7 | 26.7 | 156.9 | +BR003=370.PB102-KR001T | ORIGINAL
20446822 | Nivå F | 48.3 | 48.3 | 151.608 | +BR003=370.PB102-KR001T | ORIGINAL
20446943 | Nivå F | 26.7 | 26.7 | 156.9 | +BR003=370.PB102-KR001T | ORIGINAL
20446946 | Nivå F | 48.3 | 48.3 | 400.494 | +BR003=370.PB102-KR001T | ORIGINAL
20447047 | Nivå F | 26.7 | 26.7 | 300.624 | +BR003=370.PB102-KR001T | ORIGINAL | Group: 370.PB102 R
20447115 | Nivå F | 26.7 | 26.7 | 862.975 | +BR003=370.PB102-KR001T | ORIGINAL | Group: 370.PB102 T
20447187 | Nivå F | 26.7 | 26.7 | 178.368 | +BR003=370.PB102-KR001T | ORIGINAL | Group: 370.PB102 R
20447254 | Nivå F | 26.7 | 26.7 | 87.2079 | +BR003=370.PB102-KR001T | ORIGINAL | Group: 370.PB102 R
22158763 | Nivå F | 42.4 | 42.4 | 2095.2 | +BR003=370.PB102-KR001T | ORIGINAL
22159780 | Nivå F | 42.4 | 42.4 | 2095.2 | +BR003=370.PB102-KR001T | ORIGINAL
22160854 | Nivå F | 42.4 | 42.4 | 493.221 | +BR003=370.PB102-KR001T | ORIGINAL | Group: 370.PB102 R
22160914 | Nivå F | 42.4 | 42.4 | 504.501 | +BR003=370.PB102-KR001T | ORIGINAL | Group: 370.PB102 T
22161345 | Nivå F | 42.4 | 42.4 | 1392.1 | +BR003=370.PB102-KR001T | ORIGINAL | Group: 370.PB102 T
22161570 | Nivå F | 42.4 | 42.4 | 1160.38 | +BR003=370.PB102-KR001T | ORIGINAL | Group: 370.PB102 R
22162198 | Nivå F | 42.4 | 42.4 | 687.774 | +BR003=370.PB102-KR001T | ORIGINAL
22162211 | Nivå F | 42.4 | 42.4 | 525.2 | +BR003=370.PB102-KR001T | ORIGINAL
22162252 | Nivå F | 42.4 | 42.4 | 887.774 | +BR003=370.PB102-KR001T | ORIGINAL
22162261 | Nivå F | 42.4 | 42.4 | 525.2 | +BR003=370.PB102-KR001T | ORIGINAL
22162505 | Nivå F | 42.4 | 42.4 | 161.3 | +BR003=370.PB102-KR001T | ORIGINAL
22162508 | Nivå F | 48.3 | 48.3 | 331.948 | +BR003=370.PB102-KR001T | ORIGINAL
22162562 | Nivå F | 42.4 | 42.4 | 161.3 | +BR003=370.PB102-KR001T | ORIGINAL
22162565 | Nivå F | 48.3 | 48.3 | 216.377 | +BR003=370.PB102-KR001T | ORIGINAL
22162788 | Nivå F | 42.813 | 42.4 | 115.504 | +BR003=370.PB102-KR001T | ORIGINAL
22162805 | Nivå F | 42.8611 | 42.4 | 115.522 | +BR003=370.PB102-KR001T | ORIGINAL
22163249 | Nivå F | 42.4 | 42.4 | 2795.2 | +BR003=370.PB102-KR001T | ORIGINAL
22163277 | Nivå F | 42.4 | 42.4 | 5130.81 | +BR003=370.PB102-KR001T | ORIGINAL
22163317 | Nivå F | 42.4 | 42.4 | 155.2 | +BR003=370.PB102-KR001T | ORIGINAL
22163379 | Nivå F | 42.4 | 42.4 | 2975.55 | +BR003=370.PB102-KR001T | ORIGINAL
22163401 | Nivå F | 42.4 | 42.4 | 5777.87 | +BR003=370.PB102-KR001T | ORIGINAL | Group: 370.PB102 R
22163437 | Nivå F | 42.4 | 42.4 | 197.6 | +BR003=370.PB102-KR001T | ORIGINAL | Group: 370.PB102 R 2
22163517 | Nivå F | 42.4 | 177.816 | 177.816 | +BR003=370.PB102-KR001T | ORIGINAL
22163554 | Nivå F | 42.4 | 42.4 | 473.501 | +BR003=370.PB102-KR001T | ORIGINAL | Group: 370.PB102 R 2
22163581 | Nivå F | 42.4 | 42.4 | 452.721 | +BR003=370.PB102-KR001T | ORIGINAL | Group: 370.PB102 T
22163815 | Nivå F | 42.4 | 42.4 | 990.099 | +BR003=370.PB102-KR001T | ORIGINAL | Group: 370.PB102 R 2
22164010 | Nivå F | 42.4 | 42.4 | 1053.88 | +BR003=370.PB102-KR001T | ORIGINAL | Group: 370.PB102 T
23486564 | Nivå F | 26 | 26 | 356 | +BR003=370.PB102-KR001T | RESULT
23486602 | Nivå F | 26 | 26 | 356 | +BR003=370.PB102-KR001T | RESULT
22160248 | Nivå F | 42 | 42 | 349 | +BR003=370.PB102-KR001T | RESULT
17600526 | Nivå E | 60 | 61 | 8270 | +BR003=320.PB001-KR001T | RESULT
17600584 | Nivå E | 60 | 61 | 8270 | +BR003=320.PB001-KR001T | RESULT

# IfcFlowSegment: Rectangular Duct:KK002T - Rektangulære, Forsinket stål (3)
ePset_Simplebim - Assembly Level: Leaf
AVINOR - 08_Status: S4; 07_Fase: F90
ePset_LocationTool - Splitting: ORIGINAL
Name (Rectangular Duct:KK002T - Rektangulære, Forsinket stål:...) | In | Width (Simplebim) (mm) | Height (Simplebim) (mm) | Length (Simplebim) (mm) | 05_ID-nummer | Group
14508688 | Nivå F | 600 | 655 | 900 | +BR003=360.PB116-KK002T | 360.PB116 T
14508693 | Nivå E | 700 | 70 | 1000 | +BR003=360.PB116-KK002T | 360.PB116 T
21339646 | Nivå F | 1300 | 620 | 1400 | +BR003=360.PB114-KK002T | 360.PB114 A

# IfcFlowSegment: Round Duct:KK001T - Spiro kanaler, Forsinket stål (93)
ePset_Simplebim - Assembly Level: Leaf
AVINOR - 08_Status: S4; 07_Fase: F90
Name (Round Duct:KK001T - Spiro kanaler, Forsinket stål:...) | In | Splitting | Length (Simplebim) (mm) | Width (Simplebim) (mm) | Height (Simplebim) (mm) | 05_ID-nummer | Group
2797467 | Nivå F | ORIGINAL | 1579.24 | 630 | 630 | +BR003=360.PB114-KK001T | 360.PB114 T
2801698 | Nivå F | ORIGINAL | 321.491 | 400 | 400 | +BR003=360.PB114-KK001T | 360.PB114 T
12068523 | Nivå C | ORIGINAL | 3576.85 | 630 | 630 | +BR003=360.PB114-KK001T | 360.PB114 A
13302469 | Nivå F | ORIGINAL | 2794.75 | 500 | 500 | +BR003=360.PB114-KK001T | 360.PB114 A
13302501 | Nivå F | ORIGINAL | 3721.25 | 500 | 500 | +BR003=360.PB114-KK001T | 360.PB114 T
13302816 | Nivå F | ORIGINAL | 1199.72 | 500 | 500 | +BR003=360.PB114-KK001T | 360.PB114 A
14508758 | Nivå F | ORIGINAL | 268.142 | 125 | 268.142 | +BR003=360.PB114-KK001T | 360.PB114 A
14508765 | Nivå F | ORIGINAL | 190.732 | 125 | 125 | +BR003=360.PB114-KK001T | 360.PB114 A
14508980 | Nivå F | ORIGINAL | 3560 | 630 | 630 | +BR003=360.PB114-KK001T | 360.PB114 T
14551331 | Nivå F | ORIGINAL | 3183.92 | 1000 | 1000 | +BR003=360.PB116-KK001T | 360.PB116 A
14746962 | Nivå F | ORIGINAL | 26.5 | 500 | 500 | +BR003=360.PB114-KK001T | 360.PB114 A
14747010 | Nivå F | ORIGINAL | 617.529 | 500 | 500 | +BR003=360.PB114-KK001T | 360.PB114 T
14747214 | Nivå F | ORIGINAL | 477.5 | 500 | 500 | +BR003=360.PB114-KK001T | 360.PB114 A
14747252 | Nivå F | ORIGINAL | 337.106 | 500 | 500 | +BR003=360.PB114-KK001T | 360.PB114 T
14775746 | Nivå F | ORIGINAL | 254.029 | 500 | 500 | +BR003=360.PB114-KK001T | 360.PB114 A
14775865 | Nivå F | ORIGINAL | 146.5 | 500 | 500 | +BR003=360.PB114-KK001T | 360.PB114 T
14814017 | Nivå F | ORIGINAL | 125 | 49.6985 | 125 | +BR003=360.PB114-KK001T | 360.PB114 A
14814388 | Nivå A | ORIGINAL | 181.252 | 125 | 125 | +BR003=360.PB114-KK001T | 360.PB114 A
14814404 | Nivå A | ORIGINAL | 217.667 | 125 | 125 | +BR003=360.PB114-KK001T | 360.PB114 A
18182405 | Nivå C | ORIGINAL | 1155.65 | 630 | 630 | +BR003=360.PB114-KK001T | 360.PB114 A
18960790 | Nivå E | ORIGINAL | 160 | 15.2258 | 160 | +BR003=360.PB114-KK001T | 360.PB114 A
18960800 | Nivå E | ORIGINAL | 169.411 | 160 | 169.411 | +BR003=360.PB114-KK001T | 360.PB114 A
18961029 | Nivå E | ORIGINAL | 415 | 125 | 125 | +BR003=360.PB114-KK001T | 360.PB114 A
18961107 | Nivå E | ORIGINAL | 1603.73 | 160 | 160 | +BR003=360.PB114-KK001T | 360.PB114 A
18961165 | Nivå E | ORIGINAL | 588.726 | 160 | 160 | +BR003=360.PB114-KK001T | 360.PB114 A
18961567 | Nivå E | ORIGINAL | 16.6396 | 125 | 125 | +BR003=360.PB114-KK001T | 360.PB114 A
18968580 | Nivå E | ORIGINAL | 125 | 60 | 125 | +BR003=360.PB114-KK001T | 360.PB114 A
19854931 | Nivå E | ORIGINAL | 160 | 60 | 160 | +BR003=360.PB114-KK001T | 360.PB114 A
19854945 | Nivå E | ORIGINAL | 160 | 142.763 | 160 | +BR003=360.PB114-KK001T | 360.PB114 A
19855075 | Nivå E | ORIGINAL | 464.598 | 160 | 160 | +BR003=360.PB114-KK001T | 360.PB114 A
21341093 | Nivå F | ORIGINAL | 628.198 | 400 | 400 | +BR003=360.PB114-KK001T | 360.PB114 A
21341208 | Nivå F | ORIGINAL | 320 | 500 | 500 | +BR003=360.PB114-KK001T | 360.PB114 A
21351860 | Nivå F | ORIGINAL | 1179.5 | 500 | 500 | +BR003=360.PB114-KK001T | 360.PB114 A
21351884 | Nivå F | ORIGINAL | 692.339 | 677.462 | 500 | +BR003=360.PB114-KK001T | 360.PB114 A
21354114 | Nivå F | ORIGINAL | 1655 | 630 | 630 | +BR003=360.PB114-KK001T | 360.PB114 A
21354120 | Nivå F | ORIGINAL | 531.593 | 531.593 | 315 | +BR003=360.PB114-KK001T | 360.PB114 A
21354368 | Nivå F | ORIGINAL | 32 | 315 | 315 | +BR003=360.PB114-KK001T | 360.PB114 A
21354684 | Nivå F | ORIGINAL | 219.125 | 315 | 315 | +BR003=360.PB114-KK001T | 360.PB114 A
21354799 | Nivå F | ORIGINAL | 315 | 315 | 295.97 | +BR003=360.PB114-KK001T | 360.PB114 A
21354961 | Nivå F | ORIGINAL | 1701.87 | 315 | 315 | +BR003=360.PB114-KK001T | 360.PB114 A
21356095 | Nivå F | ORIGINAL | 1047.9 | 250 | 250 | +BR003=360.PB114-KK001T | 360.PB114 A
21373506 | Nivå F | ORIGINAL | 266.866 | 315 | 315 | +BR003=360.PB114-KK001T | 360.PB114 A
21373624 | Nivå F | ORIGINAL | 68.4377 | 160 | 160 | +BR003=360.PB114-KK001T | 360.PB114 A
21373637 | Nivå F | ORIGINAL | 160 | 160 | 50 | +BR003=360.PB114-KK001T | 360.PB114 A
21373674 | Nivå F | ORIGINAL | 125.081 | 85.1363 | 125 | +BR003=360.PB114-KK001T | 360.PB114 A
21373705 | Nivå F | ORIGINAL | 612.781 | 125 | 125 | +BR003=360.PB114-KK001T | 360.PB114 A
21373915 | Nivå F | ORIGINAL | 17.4451 | 315 | 315 | +BR003=360.PB114-KK001T | 360.PB114 A
21374515 | Nivå F | ORIGINAL | 1836.09 | 500 | 500 | +BR003=360.PB114-KK001T | 360.PB114 A
21393102 | Nivå F | ORIGINAL | 1060 | 500 | 500 | +BR003=360.PB114-KK001T | 360.PB114 T
21393119 | Nivå F | ORIGINAL | 506.654 | 400 | 400 | +BR003=360.PB114-KK001T | 360.PB114 T
21393121 | Nivå F | ORIGINAL | 400 | 142.29 | 396.757 | +BR003=360.PB114-KK001T | 360.PB114 T
21393181 | Nivå F | ORIGINAL | 210.981 | 160 | 206.926 | +BR003=360.PB114-KK001T | 360.PB114 T
21393186 | Nivå F | ORIGINAL | 197.734 | 160 | 183.997 | +BR003=360.PB114-KK001T | 360.PB114 A
21393211 | Nivå F | ORIGINAL | 159.785 | 94.4473 | 159.78 | +BR003=360.PB114-KK001T | 360.PB114 T
21408594 | Nivå F | ORIGINAL | 1691.65 | 400 | 400 | +BR003=360.PB114-KK001T | 360.PB114 T
21408599 | Nivå F | ORIGINAL | 8396.14 | 400 | 400 | +BR003=360.PB114-KK001T | 360.PB114 T
21412070 | Nivå F | ORIGINAL | 850 | 500 | 500 | +BR003=360.PB114-KK001T | 360.PB114 T
21412084 | Nivå F | ORIGINAL | 811.772 | 124.832 | 124.828 | +BR003=360.PB114-KK001T | 360.PB114 T
21412102 | Nivå F | ORIGINAL | 17.5 | 400 | 400 | +BR003=360.PB114-KK001T | 360.PB114 T
21412112 | Nivå F | ORIGINAL | 959.028 | 250 | 250 | +BR003=360.PB114-KK001T | 360.PB114 T
21412114 | Nivå F | ORIGINAL | 80.9766 | 250 | 250 | +BR003=360.PB114-KK001T | 360.PB114 T
21412122 | Nivå F | ORIGINAL | 29.6728 | 250 | 250 | +BR003=360.PB114-KK001T | 360.PB114 T
21412194 | Nivå F | ORIGINAL | 125.001 | 57.1437 | 125 | +BR003=360.PB114-KK001T | 360.PB114 T
21412224 | Nivå F | ORIGINAL | 125 | 29.922 | 125 | +BR003=360.PB114-KK001T | 360.PB114 T
21412369 | Nivå F | ORIGINAL | 2073.93 | 400 | 400 | +BR003=360.PB114-KK001T | 360.PB114 T
21413009 | Nivå F | ORIGINAL | 885.972 | 315 | 315 | +BR003=360.PB114-KK001T | 360.PB114 T
21413433 | Nivå F | ORIGINAL | 965 | 500 | 500 | +BR003=360.PB114-KK001T | 360.PB114 T
21413672 | Nivå F | ORIGINAL | 315 | 315 | 120 | +BR003=360.PB114-KK001T | 360.PB114 A
21414870 | Nivå F | ORIGINAL | 2990 | 250 | 250 | +BR003=360.PB114-KK001T | 360.PB114 T
21415651 | Nivå F | ORIGINAL | 1427.5 | 315 | 315 | +BR003=360.PB114-KK001T | 360.PB114 T
21415739 | Nivå F | ORIGINAL | 947.5 | 250 | 250 | +BR003=360.PB114-KK001T | 360.PB114 T
21415787 | Nivå F | ORIGINAL | 270 | 250 | 250 | +BR003=360.PB114-KK001T | 360.PB114 T
21415849 | Nivå F | ORIGINAL | 265 | 250 | 250 | +BR003=360.PB114-KK001T | 360.PB114 T
21415922 | Nivå F | ORIGINAL | 210.972 | 250 | 250 | +BR003=360.PB114-KK001T | 360.PB114 T
21416034 | Nivå F | ORIGINAL | 1142.5 | 250 | 250 | +BR003=360.PB114-KK001T | 360.PB114 T
21416187 | Nivå F | ORIGINAL | 230 | 250 | 250 | +BR003=360.PB114-KK001T | 360.PB114 T
21416195 | Nivå F | ORIGINAL | 20.9719 | 250 | 250 | +BR003=360.PB114-KK001T | 360.PB114 T
21416328 | Nivå F | ORIGINAL | 394.918 | 250 | 250 | +BR003=360.PB114-KK001T | 360.PB114 T
21416344 | Nivå F | ORIGINAL | 70 | 250 | 250 | +BR003=360.PB114-KK001T | 360.PB114 T
21416558 | Nivå F | ORIGINAL | 4915 | 315 | 315 | +BR003=360.PB114-KK001T | 360.PB114 T
21434616 | Nivå F | ORIGINAL | 140 | 160 | 160 | +BR003=360.PB114-KK001T | 360.PB114 T
21434656 | Nivå F | ORIGINAL | 475.588 | 125 | 125 | +BR003=360.PB114-KK001T | 360.PB114 T
21434664 | Nivå F | ORIGINAL | 240.206 | 125 | 220.385 | +BR003=360.PB114-KK001T | 360.PB114 T
21434704 | Nivå F | ORIGINAL | 252.453 | 125 | 191.104 | +BR003=360.PB114-KK001T | 360.PB114 T
21434838 | Nivå F | ORIGINAL | 500 | 125 | 125 | +BR003=360.PB114-KK001T | 360.PB114 T
21435031 | Nivå F | ORIGINAL | 100 | 160 | 160 | +BR003=360.PB114-KK001T | 360.PB114 A
21435214 | Nivå F | ORIGINAL | 622.5 | 125 | 125 | +BR003=360.PB114-KK001T | 360.PB114 A
21435243 | Nivå F | ORIGINAL | 86.8542 | 125 | 125 | +BR003=360.PB114-KK001T | 360.PB114 A
21449827 | Nivå F | ORIGINAL | 336.018 | 250 | 332 | +BR003=360.PB114-KK001T | 360.PB114 T
21641322 | Nivå F | ORIGINAL | 1077.5 | 250 | 250 | +BR003=360.PB114-KK001T | 360.PB114 A
14551282 | Nivå E | RESULT | 1014 | 1000 | 1000 | +BR003=360.PB116-KK001T | 360.PB116 A
5519461 | Nivå E | RESULT | 1000 | 1000 | 390 | +BR003=360.PB116-KK001T | 360.PB116 T
14508927 | Nivå E | RESULT | 980 | 630 | 630 | +BR003=360.PB114-KK001T | 360.PB114 T

# IfcFlowTerminal: BUS Vippe enkel:Switch with one push button, BUS Vippe enkel:Switch with one push button:15203444
In: Nivå F
Type - Material: <Unnamed>
ePset_Simplebim - Assembly Level: Leaf
AVINOR - 08_Status: S4; 07_Fase: F90
ePset_LocationTool - Splitting: ORIGINAL

# IfcFlowTerminal: FRALUFTSVENTIL - - SF001T:FRALUFTSVENTIL - KSO 125 - SF001T (3)
Type - Material: <Unnamed>
ePset_Simplebim - Assembly Level: Leaf
AVINOR - 08_Status: S4; 07_Fase: F90; 05_ID-nummer: +BR003=360.TO001-SF001T
ePset_LocationTool - Splitting: ORIGINAL
Group: 360.PB114 A
Name (FRALUFTSVENTIL - - SF001T:FRALUFTSVENTIL - KSO 125 - SF001T:...) | In
14508769 | Nivå F
18958509 | Nivå E
18958537 | Nivå E

# IfcFlowTerminal: FRALUFTSVENTIL - - SF001T:FRALUFTSVENTIL - KSO 160 - SF001T, FRALUFTSVENTIL - - SF001T:FRALUFTSVENTIL - KSO 160 - SF001T:21373667
In: Nivå F
Type - Material: <Unnamed>
ePset_Simplebim - Assembly Level: Leaf
ePset_LocationTool - Splitting: ORIGINAL
AVINOR - 08_Status: S4; 07_Fase: F90; 05_ID-nummer: +BR003=360.TO001-SF001T
Group: 360.PB114 A

# IfcFlowTerminal: FRALUFTSVENTIL - - SF020T:FRALUFTSVENTIL - Orion-ATV-K-TA-T-400 - SF020T, FRALUFTSVENTIL - - SF020T:FRALUFTSVENTIL - Orion-ATV-K-TA-T-400 - SF020T:21354818
In: Nivå F
Type - Material: <Unnamed>
AVINOR - 08_Status: S4; 07_Fase: F90; 05_ID-nummer: +BR003=360.TO001-SF020T
ePset_Simplebim - Assembly Level: Leaf
ePset_LocationTool - Splitting: ORIGINAL
Group: 360.PB114 A

# IfcFlowTerminal: KJØKKENHETTE - FA:KJØKKENHETTE - Kjøkkenhette 1400x1300 - FA003T, KJØKKENHETTE - FA:KJØKKENHETTE - Kjøkkenhette 1400x1300 - FA003T:21596523
In: Nivå F
Type - Material: <Unnamed>
ePset_Simplebim - Assembly Level: Leaf
ePset_LocationTool - Splitting: ORIGINAL
AVINOR - 08_Status: S4; 07_Fase: F90; 05_ID-nummer: +BR003=360.PB114-FA002
Group: 360.PB114 A

# IfcFlowTerminal: Ledelys bredstrålende LED innfelt:-UN6200 RAL 9010 (2)
In: Nivå F
Type - Material: magi2D, <Unnamed>
ePset_Simplebim - Assembly Level: Leaf
AVINOR - 08_Status: S4; 07_Fase: F90
ePset_LocationTool - Splitting: ORIGINAL
Name (Ledelys bredstrålende LED innfelt:-UN6200 RAL 9010:...) | 05_ID-nummer
13339064 | +BR003=443.PF204-UN404
13339065 | +BR003=443.PF204-UN305

# IfcFlowTerminal: PLUMBING FIXTURE - Ghost object -:ARMATUR - - UB509T, PLUMBING FIXTURE - Ghost object -:ARMATUR - - UB509T:18891232
In: Nivå F
Type - Material: <Unnamed>
ePset_LocationTool - Splitting: ORIGINAL
ePset_Simplebim - Assembly Level: Leaf
AVINOR - 08_Status: S4; 07_Fase: F90; 05_ID-nummer: +BR003=310.TO100-UB509T

# IfcFlowTerminal: PLUMBING FIXTURE - Ghost object -:ARMATUR - - UB510T, PLUMBING FIXTURE - Ghost object -:ARMATUR - - UB510T:18891344
In: Nivå F
Type - Material: <Unnamed>
ePset_Simplebim - Assembly Level: Leaf
ePset_LocationTool - Splitting: ORIGINAL
AVINOR - 05_ID-nummer: +BR003=310.TO100-UB510T; 08_Status: S4; 07_Fase: F90

# IfcFlowTerminal: PLUMBING FIXTURE - Ghost object -:UTSLAGSVASK - - NY503T, PLUMBING FIXTURE - Ghost object -:UTSLAGSVASK - - NY503T:18891158
In: Nivå F
Type - Material: <Unnamed>
ePset_Simplebim - Assembly Level: Leaf
ePset_LocationTool - Splitting: ORIGINAL
AVINOR - 08_Status: S4; 07_Fase: F90; 05_ID-nummer: +BR003=310.TO500-NY503T

# IfcFlowTerminal: PLUMBING FIXTURE - Ghost object -:UTSLAGSVASK - - NY505T, PLUMBING FIXTURE - Ghost object -:UTSLAGSVASK - - NY505T:18891196
In: Nivå F
Type - Material: <Unnamed>
ePset_Simplebim - Assembly Level: Leaf
ePset_LocationTool - Splitting: ORIGINAL
AVINOR - 08_Status: S4; 07_Fase: F90; 05_ID-nummer: +BR003=310.TO500-NY505T

# IfcFlowTerminal: PLUMBING FIXTURE - Ghost object -:VARMTVANNSBEREDER - - NW501T, PLUMBING FIXTURE - Ghost object -:VARMTVANNSBEREDER - - NW501T:18890658
In: Nivå F
Type - Material: <Unnamed>
ePset_Simplebim - Assembly Level: Leaf
ePset_LocationTool - Splitting: ORIGINAL
AVINOR - 08_Status: S4; 07_Fase: F90; 05_ID-nummer: +BR003=310.TO200-NW501T

# IfcFlowTerminal: QLF-0002:TILLUFTSVENTIL - ST907T - ST907T, QLF-0002:TILLUFTSVENTIL - ST907T - ST907T:14984020
In: Nivå F
Type - Material: <Unnamed>
ePset_Simplebim - Assembly Level: Leaf
ePset_LocationTool - Splitting: ORIGINAL
AVINOR - 08_Status: S4; 07_Fase: F90; 05_ID-nummer: +BR003=360.TO001-ST907T
Group: 360.PB116 T

# IfcFlowTerminal: SLUK - flis 1 - KN:SLUK - - KN505T, SLUK - flis 1 - KN:SLUK - - KN505T:18877703
In: Nivå F
Type - Material: <Unnamed>
AVINOR - 08_Status: S4; 07_Fase: F90; 05_ID-nummer: +BR003=310.SB800-KN505T
ePset_Simplebim - Assembly Level: Leaf
ePset_LocationTool - Splitting: ORIGINAL

# IfcFlowTerminal: TILLUFTSVENTIL - - ST072T:TILLUFTSVENTIL - ALE-1000-500 - ST072T, TILLUFTSVENTIL - - ST072T:TILLUFTSVENTIL - ALE-1000-500 - ST072T:18929419
In: Nivå F
Type - Material: <Unnamed>
ePset_Simplebim - Assembly Level: Leaf
ePset_LocationTool - Splitting: ORIGINAL
AVINOR - 08_Status: S4; 07_Fase: F90; 05_ID-nummer: +BR003=360.TO001-ST072T
Group: 360.PB116 T

# IfcFlowTerminal: TILLUFTSVENTIL - 1 - ST004T:TILLUFTSVENTIL - TELLUS-LOV-H-100 - ST004T (2)
In: Nivå F
Type - Material: <Unnamed>
ePset_Simplebim - Assembly Level: Leaf
ePset_LocationTool - Splitting: ORIGINAL
AVINOR - 08_Status: S4; 07_Fase: F90; 05_ID-nummer: +BR003=360.TO001-ST004T
Name (TILLUFTSVENTIL - 1 - ST004T:TILLUFTSVENTIL - TELLUS-LOV-H-100 - ST004T:...)
14364755
14364756

# IfcFlowTerminal: TILLUFTSVENTIL - 1 - ST004T:TILLUFTSVENTIL - TELLUS-LOV-H-125 - ST004T, TILLUFTSVENTIL - 1 - ST004T:TILLUFTSVENTIL - TELLUS-LOV-H-125 - ST004T:14508756
In: Nivå F
Type - Material: <Unnamed>
ePset_Simplebim - Assembly Level: Leaf
AVINOR - 08_Status: S4; 07_Fase: F90; 05_ID-nummer: +BR003=360.TO001-ST004T
ePset_LocationTool - Splitting: ORIGINAL

# IfcFlowTerminal: TILLUFTSVENTIL - 2 - ST003T:TILLUFTSVENTIL - Orion-OPUS-R-160+Luna-160-160 - ST003T, TILLUFTSVENTIL - 2 - ST003T:TILLUFTSVENTIL - Orion-OPUS-R-160+Luna-160-160 - ST003T:21393164
In: Nivå F
Type - Material: <Unnamed>
ePset_Simplebim - Assembly Level: Leaf
ePset_LocationTool - Splitting: ORIGINAL
AVINOR - 05_ID-nummer: +BR003=360.TO001-ST003T; 08_Status: S4; 07_Fase: F90
Group: 360.PB114 T

# IfcFlowTerminal: TILLUFTSVENTIL - 2 - ST003T:TILLUFTSVENTIL - Orion-OPUS-R-315+Luna-250-315 - ST003T (7)
In: Nivå F
Type - Material: <Unnamed>
ePset_LocationTool - Splitting: ORIGINAL
ePset_Simplebim - Assembly Level: Leaf
AVINOR - 05_ID-nummer: +BR003=360.TO001-ST003T; 08_Status: S4; 07_Fase: F90
Group: 360.PB114 T
Name (TILLUFTSVENTIL - 2 - ST003T:TILLUFTSVENTIL - Orion-OPUS-R-315+Luna-250-315 - ST003T:...)
21412110
21412734
21412935
21413280
21413285
21413347
21415028

# IfcFlowTerminal: Teknisk tak utenpåliggende LED4000lm bredstrålende:-UP1113 Teknisk tak LED4000lm WB (2)
In: Nivå F
Type - Material: <Unnamed>
ePset_Simplebim - Assembly Level: Leaf
AVINOR - 08_Status: S4; 07_Fase: F90; 05_ID-nummer: +BR003=442.00001-UP1113T
ePset_LocationTool - Splitting: ORIGINAL
Group: =433.PF111-KW27
Name (Teknisk tak utenpåliggende LED4000lm bredstrålende:-UP1113 Teknisk tak LED4000lm WB:...)
5073298
5073299

# IfcFlowTerminal: Teknisk tak utenpåliggende T5 2x49 CL W_REFL IP44:-UP2110 Teknisk Tak T5 2x49 IP44 (4)
Type - Material: <Unnamed>
ePset_Simplebim - Assembly Level: Leaf
AVINOR - 08_Status: S4; 07_Fase: F90; 05_ID-nummer: +BR003=442.00001-UP2110T
ePset_LocationTool - Splitting: ORIGINAL
Name (Teknisk tak utenpåliggende T5 2x49 CL W_REFL IP44:-UP2110 Teknisk Tak T5 2x49 IP44:...) | In | Group
4317404 | Nivå E | =433.PD111-KW3
4317412 | Nivå F | =433.PF111-KW1
4317618 | Nivå E | =433.PD111-KW4
4317626 | Nivå F | =433.PF111-KW1

# IfcFlowTerminal: Tele-Data gen uttak dobbel:Tele-Dara gen.uttat dobbel, for WiFi (4)
In: Nivå F
Type - Material: <Unnamed>
ePset_Simplebim - Assembly Level: Leaf
AVINOR - 08_Status: S1; 07_Fase: F30
ePset_LocationTool - Splitting: ORIGINAL
Name (Tele-Data gen uttak dobbel:Tele-Dara gen.uttat dobbel, for WiFi:...)
6973821
6974481
6974519
10942801

# IfcFlowTerminal: Tele-Data gen uttak dobbel:Tele-Data gen. uttak dobbel (13)
In: Nivå F
Type - Material: <Unnamed>
ePset_Simplebim - Assembly Level: Leaf
AVINOR - 08_Status: S1; 07_Fase: F30
ePset_LocationTool - Splitting: ORIGINAL
Name (Tele-Data gen uttak dobbel:Tele-Data gen. uttak dobbel:...)
7220613
9532383
9532446
9532477
9532498
9532514
9532535
9532545
9532559
9532566
9532575
9796203
10755959

# IfcFlowTerminal: UZ002T:Dyse/Spreder - UZ002T (4)
In: Nivå E
Type - Material: <Unnamed>
ePset_Simplebim - Assembly Level: Leaf
AVINOR - 08_Status: S4; 07_Fase: F90; 05_ID-nummer: +BR003=332.PB001-UZ002T
ePset_LocationTool - Splitting: ORIGINAL
Group: 332.PB001 01 (1)
Name (UZ002T:Dyse/Spreder - UZ002T:...)
11541048
11541600
12558330
12558333

# IfcFlowTerminal: UZ003T:Dyse/Spreder - UZ003T (19)
In: Nivå F
Type - Material: <Unnamed>
ePset_Simplebim - Assembly Level: Leaf
ePset_LocationTool - Splitting: ORIGINAL
AVINOR - 08_Status: S4; 07_Fase: F90; 05_ID-nummer: +BR003=332.PB001-UZ003T
Group: 332.PB001 11
Name (UZ003T:Dyse/Spreder - UZ003T:...)
10504170
10504221
10504237
10504257
10504275
10504293
10504311
10504473
10504491
10504509
10504527
19474077
19474135
19474197
19474286
19474467
19526416
19527911
19527919

# IfcFlowTerminal: UZ014T:Dyse/Spreder - UZ014T, UZ014T:Dyse/Spreder - UZ014T:19552282
In: Nivå F
Type - Material: 2dsblk
ePset_Simplebim - Assembly Level: Leaf
AVINOR - 08_Status: S4; 07_Fase: F90; 05_ID-nummer: +BR003=332.PB001-UZ014T
ePset_LocationTool - Splitting: ORIGINAL
Group: 332.PB001 11

# IfcMember: Rectangular Mullion:A248-M03 buet kantbeskyt. åpning 210 hovedpav (7)
In: Nivå F
Type - PredefinedType: MULLION; Material: A200 - Metall - Stål
ePset_Simplebim - Assembly Level: Leaf
AVINOR - 08_Status: S4; 07_Fase: F90
ePset_SimplebimBasicQuantities - Height (Simplebim): 5 mm; Width (Simplebim): 210 mm
Pset_MemberCommon - Reference: Rectangular Mullion:A248-M03 buet kantbeskyt. åpning 210 hovedpav
ePset_LocationTool - Splitting: ORIGINAL
Name (Rectangular Mullion:A248-M03 buet kantbeskyt. åpning 210 hovedpav:...) | Area, sides, net (Simplebim) (m2) | Length (Simplebim) (mm) | Weight, as steel (Simplebim) (kg) | Volume, net (Simplebim) (m3)
27627919 | 0.338222 | 809.285 | 6.44265 | 0.00082072
27627920 | 0.338222 | 809.285 | 6.44265 | 0.00082072
27627921 | 0.338222 | 809.285 | 6.44265 | 0.00082072
27627922 | 0.343591 | 807.968 | 6.54574 | 0.000833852
27627923 | 0.338222 | 809.285 | 6.44265 | 0.00082072
27627924 | 0.338222 | 809.285 | 6.44265 | 0.00082072
27627925 | 0.340916 | 808.624 | 6.49442 | 0.000827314

# IfcMember: Rectangular Mullion:A248-M03 kantbeskyt. åpning 210 hovedpav (27)
In: Nivå F
Type - PredefinedType: MULLION; Material: A200 - Metall - Stål
ePset_SimplebimBasicQuantities - Height (Simplebim): 5 mm; Width (Simplebim): 210 mm
ePset_Simplebim - Assembly Level: Leaf
AVINOR - 08_Status: S4; 07_Fase: F90
Pset_MemberCommon - Reference: Rectangular Mullion:A248-M03 kantbeskyt. åpning 210 hovedpav
ePset_LocationTool - Splitting: ORIGINAL
Name (Rectangular Mullion:A248-M03 kantbeskyt. åpning 210 hovedpav:...) | Area, sides, net (Simplebim) (m2) | Length (Simplebim) (mm) | Weight, as steel (Simplebim) (kg) | Volume, net (Simplebim) (m3)
27027415 | 0.25795 | 595 | 4.90429 | 0.00062475
27027418 | 0.2601 | 600 | 4.9455 | 0.00063
27027420 | 0.2601 | 600 | 4.9455 | 0.00063
27027422 | 0.2601 | 600 | 4.9455 | 0.00063
27027423 | 0.2601 | 600 | 4.9455 | 0.00063
27027424 | 0.2601 | 600 | 4.9455 | 0.00063
27627955 | 0.2171 | 500 | 4.12125 | 0.000525
28228012 | 0.2601 | 600 | 4.9455 | 0.00063
28228053 | 0.2601 | 600 | 4.9455 | 0.00063
27027427 | 0.2601 | 600 | 4.9455 | 0.00063
27027430 | 0.2601 | 600 | 4.9455 | 0.00063
27027432 | 0.2601 | 600 | 4.9455 | 0.00063
27027433 | 0.25795 | 595 | 4.90429 | 0.00062475
27027435 | 0.25795 | 595 | 4.90429 | 0.00062475
27027436 | 0.2601 | 600 | 4.9455 | 0.00063
27027438 | 0.2601 | 600 | 4.9455 | 0.00063
27027439 | 0.2601 | 600 | 4.9455 | 0.00063
27027440 | 0.2601 | 600 | 4.9455 | 0.00063
27027441 | 0.2601 | 600 | 4.9455 | 0.00063
27027442 | 0.2601 | 600 | 4.9455 | 0.00063
27027443 | 0.25795 | 595 | 4.90429 | 0.00062475
27627949 | 0.117217 | 274.591 | 2.20659 | 0.000281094
28227342 | 0.2601 | 600 | 4.9455 | 0.00063
28227372 | 0.2601 | 600 | 4.9455 | 0.00063
28227429 | 0.2601 | 600 | 4.9455 | 0.00063
28227516 | 0.2601 | 600 | 4.9455 | 0.00063
28227579 | 0.2601 | 600 | 4.9455 | 0.00063

# IfcMember: Rectangular Mullion:A248-M03 kantbeskyt. åpning 210 hovedpav -høyre (3)
In: Nivå F
Type - PredefinedType: MULLION; Material: A200 - Metall - Stål
ePset_SimplebimBasicQuantities - Width (Simplebim): 5 mm; Length (Simplebim): 210 mm
ePset_Simplebim - Assembly Level: Leaf
AVINOR - 08_Status: S4; 07_Fase: F90
Pset_MemberCommon - Reference: Rectangular Mullion:A248-M03 kantbeskyt. åpning 210 hovedpav -høyre
ePset_LocationTool - Splitting: ORIGINAL
Name (Rectangular Mullion:A248-M03 kantbeskyt. åpning 210 hovedpav -høyre:...) | Area, sides, net (Simplebim) (m2) | Weight, as steel (Simplebim) (kg) | Height (Simplebim) (mm) | Volume, net (Simplebim) (m3)
27027404 | 0.3246 | 6.18188 | 750 | 0.0007875
27027406 | 0.0666 | 1.23638 | 150 | 0.0001575
28226992 | 0.777175 | 14.8571 | 1802.5 | 0.00189262

# IfcMember: Rectangular Mullion:A248-M03 kantbeskyt. åpning 210 hovedpav -venstre (9)
In: Nivå F
Type - PredefinedType: MULLION; Material: A200 - Metall - Stål
ePset_LocationTool - Splitting: ORIGINAL
ePset_SimplebimBasicQuantities - Width (Simplebim): 5 mm; Length (Simplebim): 210 mm
ePset_Simplebim - Assembly Level: Leaf
AVINOR - 08_Status: S4; 07_Fase: F90
Pset_MemberCommon - Reference: Rectangular Mullion:A248-M03 kantbeskyt. åpning 210 hovedpav -venstre
Name (Rectangular Mullion:A248-M03 kantbeskyt. åpning 210 hovedpav -venstre:...) | Area, sides, net (Simplebim) (m2) | Weight, as steel (Simplebim) (kg) | Height (Simplebim) (mm) | Volume, net (Simplebim) (m3)
27027388 | 0.3246 | 6.18188 | 750 | 0.0007875
27027390 | 0.0666 | 1.23638 | 150 | 0.0001575
28227856 | 0.777175 | 14.8571 | 1802.5 | 0.00189262
27027401 | 0.0666 | 1.23638 | 150 | 0.0001575
27027403 | 0.3246 | 6.18188 | 750 | 0.0007875
28226991 | 0.777175 | 14.8571 | 1802.5 | 0.00189262
28227278 | 0.777175 | 14.8571 | 1802.5 | 0.00189262
28227286 | 0.3246 | 6.18188 | 750 | 0.0007875
28227291 | 0.0666 | 1.23638 | 150 | 0.0001575

# IfcMember: Rectangular Mullion:A248-M10 vinkelprofil sokkel (18)
In: Nivå F
Type - PredefinedType: MULLION; Material: A200 - Metall - Stål
ePset_Simplebim - Assembly Level: Leaf
AVINOR - 08_Status: S4; 07_Fase: F90
Pset_MemberCommon - Reference: Rectangular Mullion:A248-M10 vinkelprofil sokkel
ePset_SimplebimBasicQuantities - Height (Simplebim): 5 mm; Width (Simplebim): 10 mm
ePset_LocationTool - Splitting: ORIGINAL
Name (Rectangular Mullion:A248-M10 vinkelprofil sokkel:...) | Weight, as steel (Simplebim) (kg) | Length (Simplebim) (mm) | Area, sides, net (Simplebim) (m2) | Volume, net (Simplebim) (m3)
30282681 | 0.11775 | 300 | 0.0091 | 0.000015
30286838 | 0.233538 | 595 | 0.01795 | 0.00002975
30286853 | 0.114223 | 291.715 | 0.00883234 | 0.0000145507
30286856 | 0.233538 | 595 | 0.01795 | 0.00002975
27026963 | 0.469306 | 1204.6 | 0.0361057 | 0.0000597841
27026964 | 0.35325 | 900 | 0.0271 | 0.000045
27026965 | 0.35325 | 900 | 0.0271 | 0.000045
27026966 | 0.35325 | 900 | 0.0271 | 0.000045
27026967 | 0.35325 | 900 | 0.0271 | 0.000045
27026968 | 0.35325 | 900 | 0.0271 | 0.000045
30282654 | 0.413546 | 1053.62 | 0.0317086 | 0.000052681
30282655 | 0.199835 | 509.834 | 0.0153759 | 0.0000254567
30282656 | 0.558201 | 1431.08 | 0.0429002 | 0.0000711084
30282664 | 0.35325 | 900 | 0.0271 | 0.000045
30282665 | 0.0632713 | 161.902 | 0.00493795 | 0.00000806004
30282666 | 0.182041 | 464.5 | 0.0140159 | 0.00002319
30282674 | 0.417077 | 1063.32 | 0.0319805 | 0.0000531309
30282675 | 0.340072 | 867.126 | 0.0260947 | 0.0000433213

# IfcPlate: A246 - T01 Trespiler-panel 600:A246-T01 Trespiler-panel 600 (32)
In: Nivå F
Type - PredefinedType: CURTAIN_PANEL; Material: A200 - Treverk - Eik
Pset_PlateCommon - Reference: A246 - T01 Trespiler-panel 600:A246-T01 Trespiler-panel 600
ePset_Simplebim - Assembly Level: Leaf
AVINOR - 08_Status: S4; 07_Fase: F90
Name (A246 - T01 Trespiler-panel 600:A246-T01 Trespiler-panel 600:...) | Splitting | Weight, as steel (Simplebim) (kg) | Volume, net (Simplebim) (m3) | Area, largest surface, net (Simplebim) (m2)
24543513 | ORIGINAL | 73.005 | 0.0093 | 0.45
28226806 | ORIGINAL | 73.005 | 0.0093 | 0.45
28226973 | ORIGINAL | 175.212 | 0.02232 | 1.08
28226974 | ORIGINAL | 175.212 | 0.02232 | 1.08
25307186 | RESULT | 77.6286 | 0.009889 | 0.4785
25307187 | RESULT | 77.6286 | 0.009889 | 0.4785
28227427 | RESULT | 77.6286 | 0.009889 | 0.4785
25307188 | RESULT | 77.6286 | 0.009889 | 0.4785
25307189 | RESULT | 77.6286 | 0.009889 | 0.4785
28227368 | RESULT | 77.6286 | 0.009889 | 0.4785
25307190 | RESULT | 77.6286 | 0.009889 | 0.4785
28227340 | RESULT | 77.6286 | 0.009889 | 0.4785
25307191 | RESULT | 77.6286 | 0.009889 | 0.4785
25307193 | RESULT | 77.6286 | 0.009889 | 0.4785
25307194 | RESULT | 77.6286 | 0.009889 | 0.4785
25307195 | RESULT | 77.6286 | 0.009889 | 0.4785
28227577 | RESULT | 77.6286 | 0.009889 | 0.4785
25307196 | RESULT | 77.6286 | 0.009889 | 0.4785
28229938 | RESULT | 65.3871 | 0.00832957 | 0.403043
28229939 | RESULT | 65.3871 | 0.00832957 | 0.403043
28229973 | RESULT | 77.872 | 0.00992 | 0.48
28230026 | RESULT | 77.872 | 0.00992 | 0.48
28230055 | RESULT | 77.872 | 0.00992 | 0.48
28230083 | RESULT | 77.872 | 0.00992 | 0.48
28230105 | RESULT | 77.872 | 0.00992 | 0.48
28230125 | RESULT | 77.872 | 0.00992 | 0.48
28230155 | RESULT | 77.872 | 0.00992 | 0.48
25307184 | RESULT | 77.6286 | 0.009889 | 0.4785
25307185 | RESULT | 77.6286 | 0.009889 | 0.4785
28227514 | RESULT | 77.6286 | 0.009889 | 0.4785
19723400 | RESULT | 61.0705 | 0.00777968 | 0.370799
30281642 | RESULT | 58.6631 | 0.007473 | 0.2385

# IfcPlate: A246 - T01 Trespiler-panel 900:A246-T01 Trespiler-panel 900 (2)
In: Nivå F
Type - PredefinedType: CURTAIN_PANEL; Material: A200 - Treverk - Eik
ePset_Simplebim - Assembly Level: Leaf
AVINOR - 08_Status: S4; 07_Fase: F90
Pset_PlateCommon - Reference: A246 - T01 Trespiler-panel 900:A246-T01 Trespiler-panel 900
ePset_LocationTool - Splitting: RESULT
ePset_SimplebimBasicQuantities - Area, largest surface, net (Simplebim): 0.48 m2; Weight, as steel (Simplebim): 97.968 kg; Volume, net (Simplebim): 0.01248 m3
Name (A246 - T01 Trespiler-panel 900:A246-T01 Trespiler-panel 900:...)
25307192
28226807

# IfcPlate: A246 - T01 Trespiler-panel tilpas:A246-T01 Trespiler-panel tilpas, A246 - T01 Trespiler-panel tilpas:A246-T01 Trespiler-panel tilpas:26153339
In: Nivå F
Type - PredefinedType: CURTAIN_PANEL; Material: A200 - Treverk - Eik
ePset_LocationTool - Splitting: RESULT
ePset_SimplebimBasicQuantities - Weight, as steel (Simplebim): 20.2581 kg; Area, largest surface, net (Simplebim): 0.218464 m2; Volume, net (Simplebim): 0.00258065 m3
ePset_Simplebim - Assembly Level: Leaf
AVINOR - 08_Status: S4; 07_Fase: F90
Pset_PlateCommon - Reference: A246 - T01 Trespiler-panel tilpas:A246-T01 Trespiler-panel tilpas

# IfcPlate: A246 - T05 Trespiler-panel buet 3m radius:A246-T05 Trespiler-panel buet 3m radius (5)
In: Nivå F
Type - PredefinedType: CURTAIN_PANEL; Material: A200 - Treverk - Eik
ePset_Simplebim - Assembly Level: Leaf
ePset_SimplebimBasicQuantities - Area, largest surface, net (Simplebim): 0.21498 m2
AVINOR - 08_Status: S4; 07_Fase: F90
ePset_LocationTool - Splitting: RESULT
Pset_PlateCommon - Reference: A246 - T05 Trespiler-panel buet 3m radius:A246-T05 Trespiler-panel buet 3m radius
Name (A246 - T05 Trespiler-panel buet 3m radius:A246-T05 Trespiler-panel buet 3m radius:...) | Volume, net (Simplebim) (m3) | Weight, as steel (Simplebim) (kg)
27627667 | 0.00826681 | 64.8944
27627668 | 0.0128128 | 100.581
27627669 | 0.0128128 | 100.581
27627670 | 0.0128128 | 100.581
27627671 | 0.0128128 | 100.581

# IfcPlate: A249-S02 - Sokkel veggkledning trespiler:A249-S02 - Sokkel veggkledning trespiler (5)
In: Nivå F
Type - PredefinedType: CURTAIN_PANEL; Material: A249 - S01 _sokkel veggkledning
ePset_Simplebim - Assembly Level: Leaf
Pset_PlateCommon - Reference: A249-S02 - Sokkel veggkledning trespiler:A249-S02 - Sokkel veggkledning trespiler
Name (A249-S02 - Sokkel veggkledning trespiler:A249-S02 - Sokkel veggkledning trespiler:...) | Splitting | 08_Status | 07_Fase | Volume, net (Simplebim) (m3) | Area, largest surface, net (Simplebim) (m2) | Weight, as steel (Simplebim) (kg)
28230153 | ORIGINAL | S4 | F90 | 0.00116211 | 0.0581056 | 9.12258
19706220 | ORIGINAL | S4 | F90 | 0.0036 | 0.18 | 28.26
25312361 | ORIGINAL | S4 | F90 | 0.0171426 | 0.857132 | 134.57
25314426 | ORIGINAL | S4 | F90 | 0.00554504 | 0.277252 | 43.5286
35876733 | RESULT |  |  | 0.00229924 | 0.115364 | 18.049

# IfcPlate: System Panel:A246-M02 - Metallrist tilluft hovedpaviljong (7)
In: Nivå F
Type - PredefinedType: CURTAIN_PANEL; Material: A246 - M02 _veggkledning metalrist tilluft
ePset_Simplebim - Assembly Level: Leaf
AVINOR - 08_Status: S4; 07_Fase: F90
Pset_PlateCommon - Reference: System Panel:A246-M02 - Metallrist tilluft hovedpaviljong
ePset_LocationTool - Splitting: ORIGINAL
Name (System Panel:A246-M02 - Metallrist tilluft hovedpaviljong:...) | Volume, net (Simplebim) (m3) | Weight, as steel (Simplebim) (kg) | Area, largest surface, net (Simplebim) (m2)
25315389 | 0.0683333 | 536.416 | 2.27778
25312377 | 0.0611604 | 480.109 | 2.03868
25312384 | 0.0466082 | 365.874 | 1.55361
25314678 | 0.041634 | 326.827 | 1.3878
25314749 | 0.0398914 | 313.147 | 1.32971
25314779 | 0.0270582 | 212.407 | 0.90194
25314807 | 0.0130687 | 102.589 | 0.435624

# IfcPlate: System Panel:A246-T01 - Trespiler hovedpaviljong (18)
In: Nivå F
Type - PredefinedType: CURTAIN_PANEL; Material: A246 - T _veggkledning trespiler
ePset_Simplebim - Assembly Level: Leaf
AVINOR - 08_Status: S4; 07_Fase: F90
Pset_PlateCommon - Reference: System Panel:A246-T01 - Trespiler hovedpaviljong
Name (System Panel:A246-T01 - Trespiler hovedpaviljong:...) | Splitting | Area, largest surface, net (Simplebim) (m2) | Weight, as steel (Simplebim) (kg) | Volume, net (Simplebim) (m3)
28229801 | ORIGINAL | 0.0431779 | 3.38946 | 0.000431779
28229972 | ORIGINAL | 0.247127 | 19.3994 | 0.00247127
28230025 | ORIGINAL | 0.466257 | 36.6012 | 0.00466257
28230054 | ORIGINAL | 0.685388 | 53.8029 | 0.00685388
28230082 | ORIGINAL | 0.904518 | 71.0047 | 0.00904518
28230104 | ORIGINAL | 1.12365 | 88.2064 | 0.0112365
28230124 | ORIGINAL | 1.34278 | 105.408 | 0.0134278
28230154 | ORIGINAL | 1.51624 | 119.025 | 0.0151624
25313913 | ORIGINAL | 1.02716 | 80.6321 | 0.0102716
25313359 | ORIGINAL | 0.88786 | 69.697 | 0.0088786
25314427 | ORIGINAL | 0.93378 | 73.3017 | 0.0093378
25313367 | ORIGINAL | 1.035 | 81.2475 | 0.01035
25314125 | ORIGINAL | 1.035 | 81.2475 | 0.01035
25314220 | ORIGINAL | 0.930565 | 73.0493 | 0.00930565
25314248 | ORIGINAL | 0.516611 | 40.554 | 0.00516611
28229937 | RESULT | 0.580488 | 45.5683 | 0.00580488
28229940 | RESULT | 0.464867 | 36.4921 | 0.00464867
25313338 | RESULT | 0.9344 | 73.3504 | 0.009344

# IfcPlate: System Panel:A249-S02 - Sokkel veggkledning flush hovedpaviljong, System Panel:A249-S02 - Sokkel veggkledning flush hovedpaviljong:28230431
In: Nivå F
Type - PredefinedType: CURTAIN_PANEL; Material: A249 - S01 _sokkel veggkledning
Pset_PlateCommon - Reference: System Panel:A249-S02 - Sokkel veggkledning flush hovedpaviljong
ePset_Simplebim - Assembly Level: Leaf
ePset_SimplebimBasicQuantities - Weight, as steel (Simplebim): 229.646 kg; Volume, net (Simplebim): 0.0292543 m3; Area, largest surface, net (Simplebim): 1.46272 m2
AVINOR - 08_Status: S4; 07_Fase: F90
ePset_LocationTool - Splitting: RESULT

# IfcRailing: 287-GL06:287-GL06, 287-GL06:287-GL06:32436467
In: Nivå F
Type - Material: A200 - Glass
ePset_Simplebim - Assembly Level: Leaf
ePset_LocationTool - Splitting: ORIGINAL
AVINOR - 08_Status: S4; 07_Fase: F90
Pset_RailingCommon - Reference: 287-GL06:287-GL06
ePset_SimplebimBasicQuantities - Width: 3815.96 mm; Length: 8178.57 mm; Height: 4710.42 mm

# IfcRailing: A287-T02:A287-T02, A287-T02:A287-T02:32431705
In: Nivå F
Type - Material: A200 - Treverk - Eik
ePset_Simplebim - Assembly Level: Leaf
AVINOR - 08_Status: S4; 07_Fase: F90
ePset_SimplebimBasicQuantities - Width: 3921.44 mm; Length: 8892.2 mm; Height: 4071.92 mm
Pset_RailingCommon - Reference: A287-T02:A287-T02
ePset_LocationTool - Splitting: ORIGINAL

# IfcRailing: Railing:A287-S03, Railing:A287-S03:27625946
In: Nivå F
Material: <Unnamed>
ePset_Simplebim - Assembly Level: Leaf
AVINOR - 08_Status: S4; 07_Fase: F90
ePset_SimplebimBasicQuantities - Length: 365.851 mm; Height: 70 mm; Width: 160.791 mm
Pset_RailingCommon - Reference: Railing:A287-S03
ePset_LocationTool - Splitting: ORIGINAL

# IfcSlab: Floor:A252 - Hulldekke 400 mm, Floor:A252 - Hulldekke 400 mm:5224848
In: Nivå F
Type - PredefinedType: FLOOR; Material: _NSW Betong 400 mm
ePset_Simplebim - Assembly Level: Leaf
ePset_LocationTool - Splitting: RESULT
Pset_SlabCommon - Reference: Floor:A252 - Hulldekke 400 mm
AVINOR - 08_Status: S4; 07_Fase: F30
ePset_SimplebimBasicQuantities - Area, top, net (Simplebim): 190.407 m2; Area, largest surface, net (Simplebim): 190.408 m2; Perimeter (Simplebim): 75743.9 mm; Volume, net (Simplebim): 76.1631 m3; Area, sides, net (Simplebim): 30.2976 m2; Thickness (Simplebim): 400 mm

# IfcSlab: Floor:A253 - Betong Påstop 150mm, Floor:A253 - Betong Påstop 150mm:17243837
In: Nivå F
Type - PredefinedType: FLOOR; Material: _NSW Betong 150 mm
ePset_Simplebim - Assembly Level: Leaf
ePset_SimplebimBasicQuantities - Area, sides, net (Simplebim): 11.4533 m2; Thickness (Simplebim): 150 mm; Perimeter (Simplebim): 76355.1 mm; Area, top, net (Simplebim): 212.611 m2; Area, largest surface, net (Simplebim): 212.611 m2; Volume, net (Simplebim): 31.8916 m3
ePset_LocationTool - Splitting: RESULT
Pset_SlabCommon - Reference: Floor:A253 - Betong Påstop 150mm
AVINOR - 08_Status: S4; 07_Fase: F30

# IfcSlab: Floor:A255-B10 Vinylgulv 3mm (KA) (2)
In: Nivå F
Type - PredefinedType: FLOOR; Material: A255 - Vinylbelegg våtrom 3 mm, _NSW Generell Gulv (Floor) 17 mm
ePset_Simplebim - Assembly Level: Leaf
AVINOR - 08_Status: S4; 07_Fase: F90
ePset_LocationTool - Splitting: ORIGINAL
ePset_SimplebimBasicQuantities - Thickness (Simplebim): 20 mm
Pset_SlabCommon - Reference: Floor:A255-B10 Vinylgulv 3mm (KA)
Name (Floor:A255-B10 Vinylgulv 3mm (KA):...) | Area, sides, net (Simplebim) (m2) | Perimeter (Simplebim) (mm) | Area, largest surface, net (Simplebim) (m2) | Area, top, net (Simplebim) (m2) | Volume, net (Simplebim) (m3)
32801032 | 0.33357 | 16678.5 | 7.80958 | 7.80951 | 0.156192
32989509 | 0.271257 | 13562.8 | 10.4068 | 10.4069 | 0.208137

# IfcSlab: Floor:A255-K03 Keramisk flis - Lys 600x600mm, Floor:A255-K03 Keramisk flis - Lys 600x600mm:16728564
In: Nivå F
Type - PredefinedType: FLOOR; Material: A255-Flis Apavisa 600x600 5 mm, A255 - Avretting 65 mm
ePset_Simplebim - Assembly Level: Leaf
AVINOR - 08_Status: S4; 07_Fase: F90
ePset_LocationTool - Splitting: RESULT
Pset_SlabCommon - Reference: Floor:A255-K03 Keramisk flis - Lys 600x600mm
ePset_SimplebimBasicQuantities - Perimeter (Simplebim): 71868.7 mm; Area, largest surface, net (Simplebim): 46.4158 m2; Volume, net (Simplebim): 3.24911 m3; Area, top, net (Simplebim): 46.4158 m2; Thickness (Simplebim): 70 mm; Area, sides, net (Simplebim): 5.03081 m2

# IfcSlab: Floor:A255-K03 Keramisk flis - Lys 600x600mm (KA), Floor:A255-K03 Keramisk flis - Lys 600x600mm (KA):32989207
In: Nivå F
PredefinedType: FLOOR
ePset_Simplebim - Assembly Level: Topmost
ePset_SimplebimBasicQuantities - Length: 1289.5 mm; Height: 84 mm; Volume, net (Simplebim): 0.0992915 m3; Width: 1100 mm
AVINOR - 08_Status: S4; 07_Fase: F90

# IfcSlab: Floor:A255-K03 Keramisk flis - Lys 600x600mm (KA) (6)
In: Nivå F
Type - PredefinedType: FLOOR; Material: A255-Flis Apavisa 600x600 5 mm, A255 - Avretting 65 mm
ePset_Simplebim - Assembly Level: Leaf
AVINOR - 08_Status: S4; 07_Fase: F90
Pset_SlabCommon - Reference: Floor:A255-K03 Keramisk flis - Lys 600x600mm (KA)
ePset_LocationTool - Splitting: ORIGINAL
Name (Floor:A255-K03 Keramisk flis - Lys 600x600mm (KA):...) | Perimeter (Simplebim) (mm) | Area, largest surface, net (Simplebim) (m2) | Area, top, net (Simplebim) (m2) | Area, sides, net (Simplebim) (m2) | Thickness (Simplebim) (mm) | Volume, net (Simplebim) (m3)
32801010 | 48540.6 | 90.2683 | 90.2681 | 3.39784 | 70 | 6.31877
32881432 | 12903.3 | 7.35701 | 7.35703 | 0.903232 | 70 | 0.514991
32989207 | 2002.96 | 0.385037 | 0.385037 | 0.20568 | 102.688 | 0.0269472
32989207 | 2481.76 | 0.538942 | 0.538942 | 0.238171 | 95.9685 | 0.0377206
32989207 | 1369.1 | 0.170598 | 0.170598 | 0.18786 | 137.214 | 0.0119251
32989207 | 2024.82 | 0.324357 | 0.324357 | 0.193821 | 95.7226 | 0.0226986

# IfcSlab: Floor:A255-M01, Floor:A255-M01:30473670
In: Nivå F
Type - PredefinedType: FLOOR; Material: Metal - Rist 30 mm
ePset_Simplebim - Assembly Level: Leaf
AVINOR - 08_Status: S4; 07_Fase: F90
ePset_LocationTool - Splitting: ORIGINAL
ePset_SimplebimBasicQuantities - Area, top, net (Simplebim): 3.77496 m2; Volume, net (Simplebim): 0.11325 m3; Area, sides, net (Simplebim): 0.300983 m2; Thickness (Simplebim): 30 mm; Perimeter (Simplebim): 10032.8 mm; Area, largest surface, net (Simplebim): 3.775 m2
Pset_SlabCommon - Reference: Floor:A255-M01

# IfcSlab: Floor:A255-ML01 Poretettet betong, Floor:A255-ML01 Poretettet betong:12164071
In: Nivå F
Type - PredefinedType: FLOOR; Material: A255 - Avretting 70 mm
ePset_Simplebim - Assembly Level: Leaf
AVINOR - 08_Status: S4; 07_Fase: F90
ePset_LocationTool - Splitting: ORIGINAL
ePset_SimplebimBasicQuantities - Perimeter (Simplebim): 19895.5 mm; Area, largest surface, net (Simplebim): 16.0202 m2; Area, top, net (Simplebim): 16.0202 m2; Thickness (Simplebim): 70 mm; Area, sides, net (Simplebim): 1.39268 m2; Volume, net (Simplebim): 1.12141 m3
Pset_SlabCommon - Reference: Floor:A255-ML01 Poretettet betong

# IfcSlab: Floor:A255-ML06 (2)
In: Nivå F
Type - PredefinedType: FLOOR; Material: A255 - Avretting 2 mm
ePset_SimplebimBasicQuantities - Thickness (Simplebim): 2 mm
ePset_Simplebim - Assembly Level: Leaf
AVINOR - 08_Status: S4; 07_Fase: F90
ePset_LocationTool - Splitting: ORIGINAL
Pset_SlabCommon - Reference: Floor:A255-ML06
Name (Floor:A255-ML06:...) | Area, largest surface, net (Simplebim) (m2) = Area, top, net (Simplebim) (m2) | Area, sides, net (Simplebim) (m2) | Volume, net (Simplebim) (m3) | Perimeter (Simplebim) (mm)
26850548 | 5.99525 | 0.0197667 | 0.0119905 | 9883.35
26850548:2 | 4.86654 | 0.0181562 | 0.00973308 | 9078.11

# IfcSlab: Floor:A258-X07 Varsel & Oppmerksomhetsfelt - taktil (NATURSTEINGULV) (3)
In: Nivå F
Type - PredefinedType: FLOOR; Material: <Unnamed> 20 mm
ePset_Simplebim - Assembly Level: Leaf
AVINOR - 08_Status: S4; 07_Fase: F90
ePset_SimplebimBasicQuantities - Volume, net (Simplebim): 0.00108 m3; Thickness (Simplebim): 20 mm
ePset_LocationTool - Splitting: ORIGINAL
Pset_SlabCommon - Reference: Floor:A258-X07 Varsel & Oppmerksomhetsfelt - taktil (NATURSTEINGULV)
Name (Floor:A258-X07 Varsel & Oppmerksomhetsfelt - taktil (NATURSTEINGULV):25780596:...) | Area, largest surface, net (Simplebim) (m2) | Perimeter (Simplebim) (mm) | Area, sides, net (Simplebim) (m2) | Area, top, net (Simplebim) (m2)
22 | 0.0539979 | 3659.98 | 0.0731996 | 0.0540002
23 | 0.0539975 | 3659.96 | 0.0731992 | 0.0540004
24 | 0.0539975 | 3659.96 | 0.0731992 | 0.0540004

# IfcSlab: Non-Monolithic Landing:Non-Monolithic Landing, Assembled Stair:Stair:14128751 Landing 1
In: Nivå F
Type - PredefinedType: LANDING
Material: A255 - Gummi
ePset_Simplebim - Assembly Level: Leaf
Pset_SlabCommon - Reference: Non-Monolithic Landing:Non-Monolithic Landing
AVINOR - 08_Status: S4; 07_Fase: F90
ePset_LocationTool - Splitting: ORIGINAL
ePset_SimplebimBasicQuantities - Perimeter (Simplebim): 7199.46 mm; Area, sides, net (Simplebim): 0.251981 m2; Area, largest surface, net (Simplebim): 3.24002 m2; Thickness (Simplebim): 35 mm; Area, top, net (Simplebim): 3.24001 m2; Volume, net (Simplebim): 0.1134 m3

# IfcSlab: SurveyMarker rektangulær:Custom (10)
In: Nivå F
Type - PredefinedType: BASESLAB; Material: Black
ePset_SimplebimBasicQuantities - Thickness (Simplebim): 0.8 mm; Volume, net (Simplebim): 0.00000153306 m3
ePset_Simplebim - Assembly Level: Leaf
Pset_SlabCommon - Reference: SurveyMarker rektangulær:Custom
ePset_LocationTool - Splitting: ORIGINAL
Name (SurveyMarker rektangulær:Custom:...) | Perimeter (Simplebim) (mm) | Area, largest surface, net (Simplebim) (m2) | Area, top, net (Simplebim) (m2) | Area, sides, net (Simplebim) (m2)
15028507 | 251.207 | 0.000958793 | 0.00191578 | 0.000200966
15126178 | 251.664 | 0.000958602 | 0.00191559 | 0.000201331
15400477 | 250.009 | 0.000958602 | 0.00191626 | 0.000200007
15400480 | 252.282 | 0.000958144 | 0.00191535 | 0.000201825
15400483 | 249.933 | 0.000958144 | 0.00191629 | 0.000199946
15400486 | 253.851 | 0.000958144 | 0.00191472 | 0.000203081
15400489 | 248.387 | 0.000958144 | 0.0019169 | 0.00019871
15400492 | 252.279 | 0.000958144 | 0.00191535 | 0.000201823
15400495 | 252.015 | 0.000958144 | 0.00191545 | 0.000201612
15400730 | 252.015 | 0.000958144 | 0.00191545 | 0.000201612

# IfcSlab: SurveyMarker:Custom (22)
Type - PredefinedType: BASESLAB; Material: Black
ePset_Simplebim - Assembly Level: Leaf
ePset_LocationTool - Splitting: ORIGINAL
Pset_SlabCommon - Reference: SurveyMarker:Custom
ePset_SimplebimBasicQuantities - Volume, net (Simplebim): 0.00000153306 m3
Name (SurveyMarker:Custom:...) | In | Area, largest surface, net (Simplebim) (m2) | Thickness (Simplebim) (mm) | Perimeter (Simplebim) (mm) | Area, sides, net (Simplebim) (m2) | Area, top, net (Simplebim) (m2)
14814945 | Nivå B | 0.000958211 | 11.8818 | 331.036 | 0.00393331 | 0.0000277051
14815100 | Nivå B | 0.000958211 | 11.5612 | 336.386 | 0.00388901 | 0.0000715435
14815118 | Nivå B | 0.000958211 | 11.5764 | 335.849 | 0.00388793 | 0.00007229
14842714 | Nivå F | 0.00095876 | 0.8 | 247.155 | 0.000197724 | 0.0019174
14842818 | Nivå F | 0.000958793 | 0.8 | 248.158 | 0.000198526 | 0.001917
14842959 | Nivå F | 0.000958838 | 0.8 | 247.157 | 0.000197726 | 0.0019174
14842973 | Nivå F | 0.000958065 | 0.8 | 247.355 | 0.000197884 | 0.00191732
14843097 | Nivå F | 0.000958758 | 0.8 | 247.157 | 0.000197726 | 0.0019174
14843113 | Nivå F | 0.000958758 | 0.8 | 250.968 | 0.000200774 | 0.00191587
15315557 | Nivå F | 0.000958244 | 0.8 | 247.968 | 0.000198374 | 0.00191707
15315602 | Nivå F | 0.000958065 | 0.8 | 248.114 | 0.000198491 | 0.00191701
15315675 | Nivå F | 0.000958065 | 0.8 | 248.798 | 0.000199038 | 0.00191674
15631815 | Nivå A | 0.000958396 | 69.8503 | 55.6658 | 0.00388827 | 0.0000720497
15631993 | Nivå A | 0.000958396 | 69.8446 | 55.6548 | 0.00388718 | 0.0000726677
16042604 | Nivå F | 0.000958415 | 0.8 | 252.509 | 0.000202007 | 0.00191526
16042674 | Nivå F | 0.000959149 | 0.8 | 251.664 | 0.000201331 | 0.00191559
16042707 | Nivå F | 0.00095876 | 0.8 | 252.067 | 0.000201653 | 0.00191543
16042738 | Nivå F | 0.00095876 | 0.8 | 248.505 | 0.000198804 | 0.00191686
16042768 | Nivå F | 0.000958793 | 0.8 | 247.011 | 0.000197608 | 0.00191746
16042796 | Nivå F | 0.000958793 | 0.8 | 249.115 | 0.000199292 | 0.00191661
16042844 | Nivå F | 0.000958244 | 0.8 | 252.067 | 0.000201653 | 0.00191543
16194616 | Nivå F | 0.000958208 | 69.8498 | 56.9337 | 0.00397681 | 0.0000278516

# IfcStair: Assembled Stair:A280 - S01, Assembled Stair:Stair:14128751
In: Nivå F
ePset_SimplebimBasicQuantities - Length: 7879.35 mm; Width: 3725.1 mm; Height: 3850 mm
ePset_Simplebim - Assembly Level: Topmost
AVINOR - 08_Status: S4; 07_Fase: F90

# IfcStairFlight: Non-Monolithic Run:Trapper med gummi belegg (2)
In: Nivå F
Type - PredefinedType: STRAIGHT
RiserHeight: 0.549184 mm; TreadLength: 0.902231 mm; Material: A255 - Gummi, <Unnamed>
ePset_Simplebim - Assembly Level: Leaf
AVINOR - 08_Status: S4; 07_Fase: F90
Pset_StairFlightCommon - Reference: Non-Monolithic Run:Trapper med gummi belegg
ePset_LocationTool - Splitting: ORIGINAL
Name (Assembled Stair:Stair:...) | NumberOfRiser | NumberOfTreads | Volume, net (Simplebim) (m3) | Height (Simplebim) (mm)
14128751 Run 1 | 16 | 15 | 0.283664 | 2643.26
14128751 Run 2 | 7 | 6 | 0.114496 | 1171.74

# IfcWall: Basic Wall:A242 - GG100/100GG (5)
In: Nivå F
Type - PredefinedType: STANDARD; Material: A240 - Gipsplate 12.5 mm, A240 - Gipsplate 12.5 mm, A200 - Isolasjon - Rock Wool 100 mm, A240 - Gipsplate 12.5 mm, A240 - Gipsplate 12.5 mm
ePset_Simplebim - Assembly Level: Leaf
ePset_LocationTool - Splitting: ORIGINAL
Pset_WallCommon - Reference: Basic Wall:A242 - GG100/100GG
ePset_SimplebimBasicQuantities - Thickness (Simplebim): 150 mm
Name (Basic Wall:A242 - GG100/100GG:...) | 08_Status | 07_Fase | Area, side, gross, average (Simplebim) (m2) | Area, side, net, smaller (Simplebim) (m2) | Area, largest surface, net (Simplebim) (m2) | Area, side, net, average (Simplebim) (m2) | Length (Simplebim) (mm) | Area, side, gross, AABB (Simplebim) (m2) | Area, side, gross, smaller (Simplebim) (m2) | Area, side, net, larger (Simplebim) (m2) | Volume, net (Simplebim) (m3) | Height (Simplebim) (mm) | Area, side, gross, larger (Simplebim) (m2)
15193202 | S4 | F90 | 8.82599 | 6.53408 | 6.67302 | 6.60399 | 2556.31 | 8.89595 | 8.75608 | 6.67391 | 0.990552 | 3480 | 8.89591
19854102 | S4 | F90 | 17.4313 | 17.3553 | 17.5073 | 17.4313 | 6082.07 | 22.9902 | 17.3553 | 17.5073 | 2.61469 | 3780 | 17.5073
23468694 | S4 | F90 | 5.86567 | 5.86567 | 5.86567 | 5.86567 | 1615.06 | 6.10492 | 5.86567 | 5.86567 | 0.879851 | 3780 | 5.86567
35869579 |  | F50 | 24.8567 | 24.8192 | 24.8941 | 24.8567 | 6878.05 | 25.5176 | 24.8192 | 24.8941 | 3.59314 | 3710 | 24.8941 | AVINOR - 03_Ansvar: 188110; 02_Prosjekt: 10003898; 05_ID-nummer: +BR003=242.0062; 01_Lufthavnkode: ENBR
35870726 |  | F50 | 3.99969 | 1.8844 | 1.8844 | 1.98859 | 1114.97 | 4.13653 | 3.8955 | 2.09279 | 0.256984 | 3710 | 4.10389 | AVINOR - 03_Ansvar: 188110; 02_Prosjekt: 10003898; 05_ID-nummer: +BR003=242.0062; 01_Lufthavnkode: ENBR

# IfcWall: Basic Wall:A242 - GG120/100GG (2)
In: Nivå F
Type - PredefinedType: STANDARD; Material: A240 - Gipsplate 12.5 mm, A240 - Gipsplate 12.5 mm, A200 - Isolasjon - Rock Wool 120 mm, A240 - Gipsplate 12.5 mm, A240 - Gipsplate 12.5 mm
ePset_Simplebim - Assembly Level: Leaf
AVINOR - 08_Status: S4; 07_Fase: F90
ePset_LocationTool - Splitting: RESULT
ePset_SimplebimBasicQuantities - Thickness (Simplebim): 170 mm
Pset_WallCommon - Reference: Basic Wall:A242 - GG120/100GG
Name (Basic Wall:A242 - GG120/100GG:...) | Area, side, gross, AABB (Simplebim) (m2) | Volume, net (Simplebim) (m3) | Area, side, net, larger (Simplebim) (m2) = Area, side, net, average (Simplebim) (m2) = Area, side, net, smaller (Simplebim) (m2) = Area, side, gross, average (Simplebim) (m2) = Area, largest surface, net (Simplebim) (m2) = Area, side, gross, smaller (Simplebim) (m2) = Area, side, gross, larger (Simplebim) (m2) | Height (Simplebim) (mm) | Length (Simplebim) (mm)
8923046 | 4.40129 | 0.748197 | 4.40116 | 710 | 6199
24683634 | 2.4653 | 0.419101 | 2.4653 | 2770 | 890

# IfcWall: Basic Wall:A242 - GGG100/0, Basic Wall:A242 - GGG100/0:8905003
In: Nivå F
Type - PredefinedType: STANDARD; Material: A240 - Gipsplate 12.5 mm, A240 - Gipsplate 12.5 mm, A240 - Gipsplate 12.5 mm, A240 - Stenderverk - Uisolert 100 mm
ePset_Simplebim - Assembly Level: Leaf
AVINOR - 08_Status: S4; 07_Fase: F90
Pset_WallCommon - Reference: Basic Wall:A242 - GGG100/0
ePset_SimplebimBasicQuantities - Volume, net (Simplebim): 1.5994 m3; Area, side, net, larger (Simplebim): 11.632 m2; Area, side, gross, smaller (Simplebim): 11.632 m2; Area, side, gross, larger (Simplebim): 11.632 m2; Area, side, net, average (Simplebim): 11.632 m2; Area, side, net, smaller (Simplebim): 11.632 m2; Area, side, gross, average (Simplebim): 11.632 m2; Area, largest surface, net (Simplebim): 11.632 m2; Area, side, gross, AABB (Simplebim): 11.6348 m2; Thickness (Simplebim): 138 mm; Length (Simplebim): 3078 mm; Height (Simplebim): 3780 mm
ePset_LocationTool - Splitting: RESULT

# IfcWall: Basic Wall:A242 - GGG75/0 (2)
In: Nivå F
Type - PredefinedType: STANDARD; Material: A240 - Gipsplate 12.5 mm, A240 - Gipsplate 12.5 mm, A240 - Gipsplate 12.5 mm, A240 - Stenderverk - Uisolert 75 mm
Pset_WallCommon - Reference: Basic Wall:A242 - GGG75/0
ePset_Simplebim - Assembly Level: Leaf
AVINOR - 08_Status: S4; 07_Fase: F90
Name (Basic Wall:A242 - GGG75/0:...) | Area, side, net, larger (Simplebim) (m2) = Area, side, gross, larger (Simplebim) (m2) = Area, side, gross, smaller (Simplebim) (m2) = Area, largest surface, net (Simplebim) (m2) = Area, side, gross, average (Simplebim) (m2) = Area, side, net, smaller (Simplebim) (m2) = Area, side, net, average (Simplebim) (m2) | Height (Simplebim) (mm) | Area, side, gross, AABB (Simplebim) (m2) | Volume, net (Simplebim) (m3) | Thickness (Simplebim) (mm) | Length (Simplebim) (mm) | Splitting
24708197 | 10.0434 | 3930.85 | 10.5347 | 1.12989 | 112.5 | 2680 | ORIGINAL
23640311 | 0.843144 | 330 | 0.84315 | 0.0948537 | 112 | 2555 | RESULT

# IfcWall: Basic Wall:A242 - GX (KA) (2)
In: Nivå F
Type - PredefinedType: STANDARD; Material: A240 - Gipsplate 12.5 mm, A240 - X-finer 15 mm
ePset_SimplebimBasicQuantities - Thickness (Simplebim): 27.5 mm
ePset_Simplebim - Assembly Level: Leaf
Pset_WallCommon - Reference: Basic Wall:A242 - GX (KA)
ePset_LocationTool - Splitting: ORIGINAL
AVINOR - 08_Status: S4; 07_Fase: F90
Name (Basic Wall:A242 - GX (KA):...) | Area, side, gross, smaller (Simplebim) (m2) = Area, side, net, smaller (Simplebim) (m2) | Length (Simplebim) (mm) | Volume, net (Simplebim) (m3) | Area, side, gross, larger (Simplebim) (m2) = Area, largest surface, net (Simplebim) (m2) = Area, side, net, larger (Simplebim) (m2) | Height (Simplebim) (mm) | Area, side, gross, average (Simplebim) (m2) = Area, side, net, average (Simplebim) (m2) | Area, side, gross, AABB (Simplebim) (m2)
32858965 | 0.959675 | 374.983 | 0.0271155 | 1.01236 | 2700 | 0.986017 | 1.01245
32871225 | 2.85845 | 3911.25 | 0.0786074 | 2.85845 | 740 | 2.85845 | 2.89433

# IfcWall: Basic Wall:A242 - GX75/0 (KA), Basic Wall:A242 - GX75/0 (KA):32812066
In: Nivå F
Type - PredefinedType: STANDARD; Material: A240 - Gipsplate 12.5 mm, A240 - X-finer 15 mm, A240 - Stenderverk - Uisolert 75 mm
ePset_SimplebimBasicQuantities - Area, side, net, larger (Simplebim): 1.34173 m2; Area, side, gross, larger (Simplebim): 1.34173 m2; Area, side, gross, smaller (Simplebim): 1.34173 m2; Area, side, net, smaller (Simplebim): 1.34173 m2; Area, side, net, average (Simplebim): 1.34173 m2; Area, largest surface, net (Simplebim): 1.34173 m2; Area, side, gross, average (Simplebim): 1.34173 m2; Area, side, gross, AABB (Simplebim): 1.35547 m2; Volume, net (Simplebim): 0.137499 m3; Thickness (Simplebim): 102.5 mm; Height (Simplebim): 550 mm; Length (Simplebim): 2464.5 mm
ePset_Simplebim - Assembly Level: Leaf
Pset_WallCommon - Reference: Basic Wall:A242 - GX75/0 (KA)
AVINOR - 08_Status: S4; 07_Fase: F90
ePset_LocationTool - Splitting: ORIGINAL

# IfcWall: Basic Wall:A242 - Lettklinker - 200 mm (4)
In: Nivå D
Type - PredefinedType: STANDARD; Material: Puss 10 mm, A242 - Lettklinkerblokker 200 mm
ePset_Simplebim - Assembly Level: Leaf
ePset_LocationTool - Splitting: RESULT
AVINOR - 08_Status: S4; 07_Fase: F90
ePset_SimplebimBasicQuantities - Thickness (Simplebim): 210 mm
Pset_WallCommon - Reference: Basic Wall:A242 - Lettklinker - 200 mm
Name (Basic Wall:A242 - Lettklinker - 200 mm:...) | Area, side, net, smaller (Simplebim) (m2) = Area, side, net, average (Simplebim) (m2) = Area, largest surface, net (Simplebim) (m2) = Area, side, gross, average (Simplebim) (m2) = Area, side, gross, larger (Simplebim) (m2) = Area, side, gross, smaller (Simplebim) (m2) = Area, side, net, larger (Simplebim) (m2) | Area, side, gross, AABB (Simplebim) (m2) | Volume, net (Simplebim) (m3) | Height (Simplebim) (mm) | Length (Simplebim) (mm)
6035593 | 3.0381 | 3.0381 | 0.638001 | 780 | 3895
6035592 | 3.0383 | 3.0381 | 0.638042 | 780 | 3895
15590301 | 1.5238 | 1.5238 | 0.319998 | 380 | 4010
23533599 | 1.41835 | 1.41816 | 0.297853 | 380 | 3732

# IfcWallStandardCase: Basic Wall:A242 - GG100/0 (6)
In: Nivå F
Type - PredefinedType: STANDARD; Material: A240 - Gipsplate 12.5 mm, A240 - Gipsplate 12.5 mm, A240 - Stenderverk - Uisolert 100 mm
Pset_WallCommon - Reference: Basic Wall:A242 - GG100/0
ePset_LocationTool - Splitting: ORIGINAL
ePset_Simplebim - Assembly Level: Leaf
AVINOR - 08_Status: S4; 07_Fase: F90
Name (Basic Wall:A242 - GG100/0:...) | Length (Simplebim) (mm) | Volume, net (Simplebim) (m3) | Thickness (Simplebim) (mm) | Height (Simplebim) (mm) | Area, side, gross, AABB (Simplebim) (m2) = Area, largest surface, net (Simplebim) (m2) | Area, side, gross, larger (Simplebim) (m2) = Area, side, net, larger (Simplebim) (m2) | Area, side, gross, smaller (Simplebim) (m2) = Area, side, net, smaller (Simplebim) (m2) | Area, side, gross, average (Simplebim) (m2) = Area, side, net, average (Simplebim) (m2)
27003410 | 4195 | 1.41581 | 125 | 2700 | 11.3265 | 11.3265 | 11.3265 | 11.3265
27003411 | 500 | 0.16875 | 125 | 2700 | 1.35 | 1.35 | 1.35 | 1.35
30775002 | 200.727 | 0.0455931 | 125 | 3480 | 0.698532 | 0.698532 | 0.0309572 | 0.364744
30775531 | 149.745 | 0.065139 | 125 | 3480 | 0.521112 | 0.521112 | 0.521112 | 0.521112
30775532 | 149.745 | 0.065139 | 125 | 3480 | 0.521112 | 0.521112 | 0.521112 | 0.521112
30775533 | 125 | 0.0261 | 60 | 3480 | 0.435 | 0.2088 | 0.2088 | 0.2088

# IfcWallStandardCase: Basic Wall:A242 - GG100/100GG (9)
In: Nivå F
Type - PredefinedType: STANDARD; Material: A240 - Gipsplate 12.5 mm, A240 - Gipsplate 12.5 mm, A200 - Isolasjon - Rock Wool 100 mm, A240 - Gipsplate 12.5 mm, A240 - Gipsplate 12.5 mm
ePset_Simplebim - Assembly Level: Leaf
ePset_LocationTool - Splitting: ORIGINAL
Pset_WallCommon - Reference: Basic Wall:A242 - GG100/100GG
ePset_SimplebimBasicQuantities - Thickness (Simplebim): 150 mm
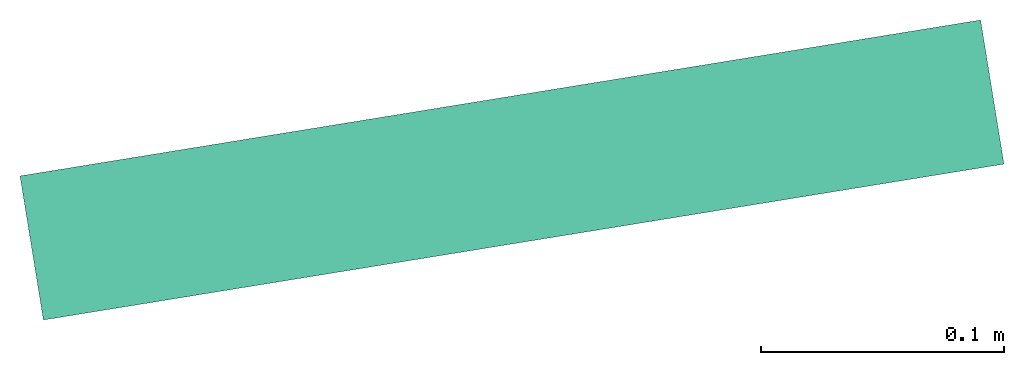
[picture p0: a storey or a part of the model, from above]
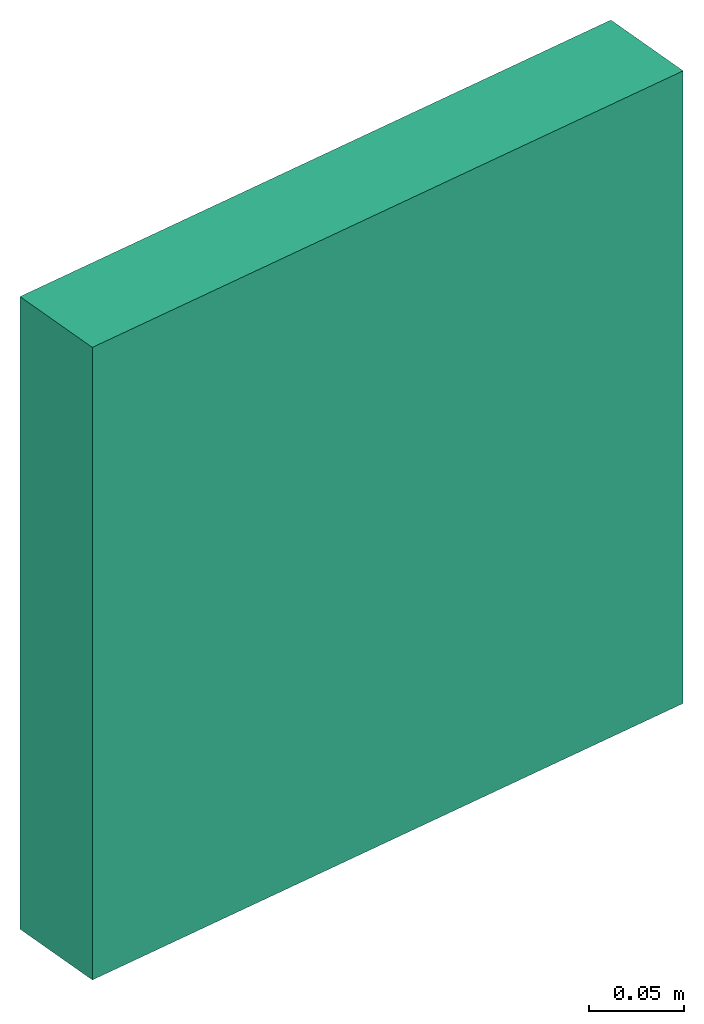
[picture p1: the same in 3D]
Properties of the parts of a building model (IFC2X3), part 4 of 4

# IfcWallStandardCase: Basic Wall:A242 - GG100/100GG (9)
Name (Basic Wall:A242 - GG100/100GG:...) | 08_Status | 07_Fase | Volume, net (Simplebim) (m3) | Length (Simplebim) (mm) | Height (Simplebim) (mm) | Area, side, gross, AABB (Simplebim) (m2) | Area, side, gross, average (Simplebim) (m2) | Area, side, gross, larger (Simplebim) (m2) | Area, side, gross, smaller (Simplebim) (m2) | Area, side, net, smaller (Simplebim) (m2) | Area, side, net, average (Simplebim) (m2) | Area, largest surface, net (Simplebim) (m2) = Area, side, net, larger (Simplebim) (m2)
6028090 | S4 | F90 | 0.6585 | 1900 | 3480 | 6.612 | 6.612 | 6.612 | 6.612 | 4.39 | 4.39 | 4.39
6028092 | S4 | F90 | 1.67393 | 2952.25 | 3780 | 11.1595 | 11.1595 | 11.1595 | 11.1595 | 11.1595 | 11.1595 | 11.1595
6028093 | S4 | F90 | 1.46277 | 2802.25 | 3480 | 9.75183 | 9.75183 | 9.75183 | 9.75183 | 9.75183 | 9.75183 | 9.75183
6292036 | S4 | F90 | 2.29351 | 4045 | 3780 | 15.2901 | 15.2901 | 15.2901 | 15.2901 | 15.2901 | 15.2901 | 15.2901
8905895 | S4 | F90 | 0.477614 | 862.449 | 3780 | 3.26006 | 3.18409 | 3.26006 | 3.10813 | 3.10813 | 3.18409 | 3.26006
15503757 | S4 | F90 | 0.140288 | 725 | 1290 | 0.93525 | 0.93525 | 0.93525 | 0.93525 | 0.93525 | 0.93525 | 0.93525
23628962 | S4 | F90 | 0.792785 | 2157.25 | 3480 | 7.50723 | 9.72923 | 9.72923 | 9.72923 | 5.28523 | 5.28523 | 5.28523
35870012 | S4 | F50 | 0.2475 | 750 | 2200 | 1.65 | 1.65 | 1.65 | 1.65 | 1.65 | 1.65 | 1.65 | AVINOR - 03_Ansvar: 188110; 02_Prosjekt: 10003898; 05_ID-nummer: +BR003=242.0062; 01_Lufthavnkode: ENBR
35870570 |  | F50 | 0.417375 | 750 | 3710 | 2.7825 | 2.7825 | 2.7825 | 2.7825 | 2.7825 | 2.7825 | 2.7825 | AVINOR - 03_Ansvar: 188110; 02_Prosjekt: 10003898; 05_ID-nummer: +BR003=242.0062; 01_Lufthavnkode: ENBR

# IfcWallStandardCase: Basic Wall:A242 - GG120/100GG (8)
In: Nivå F
Type - PredefinedType: STANDARD; Material: A240 - Gipsplate 12.5 mm, A240 - Gipsplate 12.5 mm, A200 - Isolasjon - Rock Wool 120 mm, A240 - Gipsplate 12.5 mm, A240 - Gipsplate 12.5 mm
ePset_Simplebim - Assembly Level: Leaf
ePset_LocationTool - Splitting: ORIGINAL
AVINOR - 08_Status: S4; 07_Fase: F90
Pset_WallCommon - Reference: Basic Wall:A242 - GG120/100GG
Name (Basic Wall:A242 - GG120/100GG:...) | Height (Simplebim) (mm) | Thickness (Simplebim) (mm) | Volume, net (Simplebim) (m3) | Area, side, net, larger (Simplebim) (m2) = Area, side, net, average (Simplebim) (m2) = Area, side, net, smaller (Simplebim) (m2) | Area, side, gross, average (Simplebim) (m2) = Area, side, gross, smaller (Simplebim) (m2) = Area, side, gross, larger (Simplebim) (m2) | Area, largest surface, net (Simplebim) (m2) | Area, side, gross, AABB (Simplebim) (m2) | Length (Simplebim) (mm)
15324380 | 3710 | 170 | 3.7842 | 22.26 | 22.26 | 22.26 | 22.26 | 6000
15503624 |  |  | 0.656114 |  |  | 3.98339
15503634 | 710 | 170 | 1.57431 | 9.26064 | 9.26064 | 9.26064 | 9.26064 | 13043.2
19542554 | 3480 | 170 | 2.10297 | 12.3704 | 27.8854 | 12.3704 | 27.8854 | 8013.04
20418846 | 3480 | 170 | 1.60409 | 9.4358 | 20.0505 | 9.4358 | 29.5778 | 8499.36
24683636 | 2770 | 170 | 0.555662 | 3.2686 | 3.2686 | 3.2686 | 3.2686 | 1180
24683637 | 2770 | 170 | 0.640056 | 3.76504 | 3.76504 | 3.76504 | 3.76504 | 1359.22
32867107 | 3710 | 170 | 3.78105 | 22.2415 | 22.2415 | 22.2415 | 22.2415 | 5995

# IfcWallStandardCase: Basic Wall:A242 - GGG100/0 (2)
In: Nivå F
Type - PredefinedType: STANDARD; Material: A240 - Gipsplate 12.5 mm, A240 - Gipsplate 12.5 mm, A240 - Gipsplate 12.5 mm, A240 - Stenderverk - Uisolert 100 mm
ePset_Simplebim - Assembly Level: Leaf
AVINOR - 08_Status: S4; 07_Fase: F90
Pset_WallCommon - Reference: Basic Wall:A242 - GGG100/0
ePset_SimplebimBasicQuantities - Thickness (Simplebim): 137.5 mm
ePset_LocationTool - Splitting: ORIGINAL
Name (Basic Wall:A242 - GGG100/0:...) | Area, side, net, larger (Simplebim) (m2) = Area, largest surface, net (Simplebim) (m2) = Area, side, net, smaller (Simplebim) (m2) = Area, side, net, average (Simplebim) (m2) | Area, side, gross, larger (Simplebim) (m2) = Area, side, gross, smaller (Simplebim) (m2) = Area, side, gross, average (Simplebim) (m2) = Area, side, gross, AABB (Simplebim) (m2) | Length (Simplebim) (mm) | Volume, net (Simplebim) (m3) | Height (Simplebim) (mm)
10820220 | 11.1604 | 11.1604 | 2952.5 | 1.53456 | 3780
10821330 | 9.88787 | 12.12 | 3482.75 | 1.35958 | 3480

# IfcWallStandardCase: Basic Wall:A242 - GX (KA) (3)
In: Nivå F
Type - PredefinedType: STANDARD; Material: A240 - Gipsplate 12.5 mm, A240 - X-finer 15 mm
ePset_Simplebim - Assembly Level: Leaf
Pset_WallCommon - Reference: Basic Wall:A242 - GX (KA)
AVINOR - 08_Status: S4; 07_Fase: F90
ePset_LocationTool - Splitting: ORIGINAL
ePset_SimplebimBasicQuantities - Thickness (Simplebim): 27.5 mm
Name (Basic Wall:A242 - GX (KA):...) | Area, side, gross, AABB (Simplebim) (m2) = Area, side, gross, larger (Simplebim) (m2) = Area, side, net, larger (Simplebim) (m2) | Area, largest surface, net (Simplebim) (m2) | Volume, net (Simplebim) (m3) | Length (Simplebim) (mm) | Area, side, gross, smaller (Simplebim) (m2) = Area, side, net, smaller (Simplebim) (m2) | Area, side, net, average (Simplebim) (m2) = Area, side, gross, average (Simplebim) (m2) | Height (Simplebim) (mm)
32812387 | 1.63674 | 1.63674 | 0.0424439 | 607.156 | 1.45009 | 1.54341 | 2695.74
32864302 | 0.213596 | 0.213596 | 0.00443728 | 79.1095 | 0.109116 | 0.161356 | 2700
32864343 | 0.108841 | 0.111897 | 0.00184972 | 39.9753 | 0.0256845 | 0.0672625 | 2722.69

# IfcWallStandardCase: Basic Wall:A242 - GX75/0 (KA) (6)
In: Nivå F
Type - PredefinedType: STANDARD; Material: A240 - Gipsplate 12.5 mm, A240 - X-finer 15 mm, A240 - Stenderverk - Uisolert 75 mm
ePset_Simplebim - Assembly Level: Leaf
Pset_WallCommon - Reference: Basic Wall:A242 - GX75/0 (KA)
AVINOR - 08_Status: S4; 07_Fase: F90
ePset_LocationTool - Splitting: ORIGINAL
ePset_SimplebimBasicQuantities - Thickness (Simplebim): 102.5 mm
Name (Basic Wall:A242 - GX75/0 (KA):...) | Area, side, gross, AABB (Simplebim) (m2) = Area, side, gross, larger (Simplebim) (m2) | Area, side, net, smaller (Simplebim) (m2) | Area, side, net, average (Simplebim) (m2) | Area, largest surface, net (Simplebim) (m2) = Area, side, net, larger (Simplebim) (m2) | Area, side, gross, average (Simplebim) (m2) | Area, side, gross, smaller (Simplebim) (m2) | Volume, net (Simplebim) (m3) | Height (Simplebim) (mm) | Length (Simplebim) (mm)
32799079 | 6.9255 | 6.9255 | 6.9255 | 6.9255 | 6.9255 | 6.9255 | 0.709864 | 2700 | 2565
32799081 | 1.026 | 0.964139 | 0.99507 | 1.026 | 0.99507 | 0.964139 | 0.101995 | 2700 | 380
32810915 | 8.0623 | 6.59526 | 6.59526 | 6.59526 | 8.0623 | 8.0623 | 0.676014 | 740 | 10895
32811926 | 1.62532 | 1.56346 | 1.59439 | 1.62532 | 1.59439 | 1.56346 | 0.163425 | 2700 | 601.971
32858898 | 0.5439 | 0.5439 | 0.5439 | 0.5439 | 0.5439 | 0.5439 | 0.0557497 | 700 | 777
32870709 | 0.745198 | 0.745198 | 0.745198 | 0.745198 | 0.745198 | 0.745198 | 0.0763828 | 550 | 1354.9

# IfcWallStandardCase: Basic Wall:A242 - GX75/0XG (KA) (4)
In: Nivå F
Type - PredefinedType: STANDARD; Material: A240 - Gipsplate 12.5 mm, A240 - X-finer 15 mm, A240 - Stenderverk - Uisolert 75 mm, A240 - X-finer 15 mm, A240 - Gipsplate 12.5 mm
ePset_Simplebim - Assembly Level: Leaf
Pset_WallCommon - Reference: Basic Wall:A242 - GX75/0XG (KA)
ePset_SimplebimBasicQuantities - Thickness (Simplebim): 130 mm
ePset_LocationTool - Splitting: ORIGINAL
Name (Basic Wall:A242 - GX75/0XG (KA):...) | 08_Status | 07_Fase | Area, largest surface, net (Simplebim) (m2) = Area, side, gross, average (Simplebim) (m2) = Area, side, net, smaller (Simplebim) (m2) = Area, side, net, average (Simplebim) (m2) = Area, side, gross, larger (Simplebim) (m2) = Area, side, gross, smaller (Simplebim) (m2) = Area, side, net, larger (Simplebim) (m2) = Area, side, gross, AABB (Simplebim) (m2) | Volume, net (Simplebim) (m3) | Length (Simplebim) (mm) | Height (Simplebim) (mm)
32799074 | S4 | F90 | 2.079 | 0.27027 | 770 | 2700
32799076 | S4 | F90 | 8.43075 | 1.096 | 3122.5 | 2700
35868479 |  |  | 2.2815 | 0.296595 | 845 | 2700
35868819 | S4 | F50 | 1.44658 | 0.188055 | 522.23 | 2770 | AVINOR - 03_Ansvar: 188110; 02_Prosjekt: 10003898; 05_ID-nummer: +BR003=242.0063; 01_Lufthavnkode: ENBR

# IfcWallStandardCase: Basic Wall:A246 - Fs04 (4)
In: Nivå F
Type - PredefinedType: STANDARD; Material: A240 - Fibergips (R) 9 mm
Pset_WallCommon - Reference: Basic Wall:A246 - Fs04
ePset_Simplebim - Assembly Level: Leaf
AVINOR - 08_Status: S4; 07_Fase: F90
ePset_LocationTool - Splitting: ORIGINAL
ePset_SimplebimBasicQuantities - Length (Simplebim): 2802.5 mm; Volume, net (Simplebim): 0.095341 m3; Area, side, gross, AABB (Simplebim): 10.5934 m2; Area, side, net, larger (Simplebim): 10.5934 m2; Area, side, gross, larger (Simplebim): 10.5934 m2; Area, side, gross, smaller (Simplebim): 10.5934 m2; Area, largest surface, net (Simplebim): 10.5934 m2; Area, side, gross, average (Simplebim): 10.5934 m2; Area, side, net, smaller (Simplebim): 10.5934 m2; Area, side, net, average (Simplebim): 10.5934 m2; Thickness (Simplebim): 9 mm; Height (Simplebim): 3780 mm
Name (Basic Wall:A246 - Fs04:...)
26668946
26668947
26668948
26668949

# IfcWallStandardCase: Basic Wall:A256 Metal beslag (KA) (3)
In: Nivå F
Type - PredefinedType: STANDARD; Material: A256 - Metall Aluminum beslag 5 mm
ePset_Simplebim - Assembly Level: Leaf
ePset_SimplebimBasicQuantities - Height (Simplebim): 2700 mm; Thickness (Simplebim): 5 mm; Volume, net (Simplebim): 0.00523621 m3; Length (Simplebim): 387.867 mm; Area, side, gross, AABB (Simplebim): 1.04724 m2; Area, side, net, larger (Simplebim): 1.04724 m2; Area, side, gross, larger (Simplebim): 1.04724 m2; Area, side, gross, smaller (Simplebim): 1.04724 m2; Area, largest surface, net (Simplebim): 1.04724 m2; Area, side, gross, average (Simplebim): 1.04724 m2; Area, side, net, smaller (Simplebim): 1.04724 m2; Area, side, net, average (Simplebim): 1.04724 m2
ePset_LocationTool - Splitting: ORIGINAL
AVINOR - 08_Status: S4; 07_Fase: F90
Pset_WallCommon - Reference: Basic Wall:A256 Metal beslag (KA)
Name (Basic Wall:A256 Metal beslag (KA):...)
33774082
33774299
33778087

# IfcWindow: Hullboring Sirkulær:E, Hullboring Sirkulær:E:16194615
In: Nivå F
Type - ParameterTakesPrecedence: no; Sizeable: no; Material: Utsparing
OverallHeight: 200 mm; OverallWidth: 100 mm
ePset_Simplebim - Assembly Level: Leaf
Pset_WindowCommon - Reference: Hullboring Sirkulær:E
AVINOR - 08_Status: S1
ePset_SimplebimBasicQuantities - Perimeter (Simplebim): 720 mm; Length, frame (Simplebim): 620 mm; Height (Simplebim): 260 mm; Width (Simplebim): 100 mm; Area (Simplebim): 0.026 m2
ePset_LocationTool - Splitting: ORIGINAL

# IfcWindow: Hullboring Sirkulær:V (18)
Type - ParameterTakesPrecedence: no; Sizeable: no; Material: Utsparing
ePset_Simplebim - Assembly Level: Leaf
Pset_WindowCommon - Reference: Hullboring Sirkulær:V
ePset_LocationTool - Splitting: ORIGINAL
Name (Hullboring Sirkulær:V:...) | In | OverallHeight (mm) | OverallWidth (mm) | 08_Status | Perimeter (Simplebim) (mm) | Length, frame (Simplebim) (mm) | Height (Simplebim) (mm) | Width (Simplebim) (mm) | Area (Simplebim) (m2)
14814943 | Nivå B | 200 | 100 | S4 | 660 | 580 | 250 | 80 | 0.02
14815099 | Nivå B | 200 | 100 | S4 | 660 | 580 | 250 | 80 | 0.02
14815117 | Nivå B | 200 | 100 | S4 | 660 | 580 | 250 | 80 | 0.02
14842817 | Nivå F | 200 | 160 | S4 | 1920 | 1760 | 800 | 160 | 0.128
14843096 | Nivå F | 200 | 120 | S4 | 1840 | 1720 | 800 | 120 | 0.096
14843112 | Nivå F | 200 | 120 | S4 | 1840 | 1720 | 800 | 120 | 0.096
15315556 | Nivå F | 200 | 200 | S4 | 2000 | 1800 | 800 | 200 | 0.16
15315601 | Nivå F | 200 | 200 | S4 | 2000 | 1800 | 800 | 200 | 0.16
15315674 | Nivå F | 200 | 200 | S4 | 2000 | 1800 | 800 | 200 | 0.16
15631814 | Nivå A | 250 | 250 | S4 | 920 | 670 | 210 | 250 | 0.0525
15631992 | Nivå A | 200 | 180 | S4 | 780 | 600 | 210 | 180 | 0.0378
16042603 | Nivå F | 200 | 160 | S1 | 1920 | 1760 | 800 | 160 | 0.128
16042673 | Nivå F | 200 | 160 | S1 | 1920 | 1760 | 800 | 160 | 0.128
16042706 | Nivå F | 200 | 140 | S1 | 1880 | 1740 | 800 | 140 | 0.112
16042737 | Nivå F | 200 | 140 | S1 | 1880 | 1740 | 800 | 140 | 0.112
16042767 | Nivå F | 200 | 140 | S1 | 1880 | 1740 | 800 | 140 | 0.112
16042795 | Nivå F | 200 | 100 | S1 | 1760 | 1680 | 800 | 80 | 0.064
16042843 | Nivå F | 200 | 160 | S1 | 1920 | 1760 | 800 | 160 | 0.128

# IfcWindow: Utsparing Rektangulær:E (9)
In: Nivå F
Type - ParameterTakesPrecedence: no; Sizeable: no; Material: Utsparing
AVINOR - 08_Status: S4
ePset_Simplebim - Assembly Level: Leaf
ePset_LocationTool - Splitting: ORIGINAL
Pset_WindowCommon - Reference: Utsparing Rektangulær:E
Name (Utsparing Rektangulær:E:...) | OverallHeight (mm) | OverallWidth (mm) | Perimeter (Simplebim) (mm) | Length, frame (Simplebim) (mm) | Height (Simplebim) (mm) | Width (Simplebim) (mm) | Area (Simplebim) (m2)
15028506 | 550 | 550 | 960 | 510 | 30 | 450 | 0.0135
15400476 | 550 | 550 | 1340 | 890 | 220 | 450 | 0.099
15400479 | 700 | 250 | 1640 | 1040 | 220 | 600 | 0.132
15400482 | 1350 | 250 | 2940 | 1690 | 220 | 1250 | 0.275
15400485 | 1200 | 250 | 2640 | 1540 | 220 | 1100 | 0.242
15400488 | 1200 | 250 | 2640 | 1540 | 220 | 1100 | 0.242
15400491 | 700 | 250 | 1640 | 1040 | 220 | 600 | 0.132
15400494 | 700 | 250 | 1640 | 1040 | 220 | 600 | 0.132
15400729 | 550 | 250 | 1340 | 890 | 220 | 450 | 0.099

# IfcWindow: Utsparing Rektangulær:V, Utsparing Rektangulær:V:14843153
In: Nivå F
Type - ParameterTakesPrecedence: no; Sizeable: no; Material: Utsparing
OverallHeight: 750 mm; OverallWidth: 1050 mm
AVINOR - 08_Status: S4
ePset_Simplebim - Assembly Level: Leaf
ePset_SimplebimBasicQuantities - Area (Simplebim): 0.76 m2; Perimeter (Simplebim): 3500 mm; Length, frame (Simplebim): 2550 mm; Height (Simplebim): 800 mm; Width (Simplebim): 950 mm
ePset_LocationTool - Splitting: ORIGINAL
Pset_WindowCommon - Reference: Utsparing Rektangulær:V

# IfcWindow: Utsparing Sirkulær:V (3)
In: Nivå F
Type - ParameterTakesPrecedence: no; Sizeable: no; Material: Utsparing
AVINOR - 08_Status: S4
ePset_Simplebim - Assembly Level: Leaf
ePset_SimplebimBasicQuantities - Height (Simplebim): 800 mm
Pset_WindowCommon - Reference: Utsparing Sirkulær:V
ePset_LocationTool - Splitting: ORIGINAL
Name (Utsparing Sirkulær:V:...) | OverallHeight (mm) = OverallWidth (mm) = Width (Simplebim) (mm) | Area (Simplebim) (m2) | Perimeter (Simplebim) (mm) | Length, frame (Simplebim) (mm)
14842713 | 860 | 0.688 | 3320 | 2460
14842958 | 1060 | 0.848 | 3720 | 2660
14842972 | 860 | 0.688 | 3320 | 2460
